VERSION 5.8 ;
BUSBITCHARS "[]" ;
DIVIDERCHAR "/" ;
UNITS
    DATABASE MICRONS 1000 ;
END UNITS

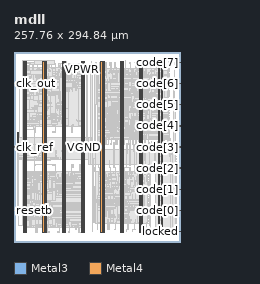
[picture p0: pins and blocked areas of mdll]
MACRO mdll
  FOREIGN mdll 0 0 ;
  CLASS BLOCK ;
  SIZE 257.76 BY 294.84 ;
  PIN clk_out
    DIRECTION OUTPUT ;
    USE SIGNAL ;
    PORT
      LAYER Metal3 ;
        RECT  0 245.5 0.4 245.9 ;
    END
  END clk_out
  PIN clk_ref
    DIRECTION INPUT ;
    USE SIGNAL ;
    PORT
      LAYER Metal3 ;
        RECT  0 147.22 0.4 147.62 ;
    END
  END clk_ref
  PIN code[0]
    DIRECTION OUTPUT ;
    USE SIGNAL ;
    PORT
      LAYER Metal3 ;
        RECT  257.36 48.94 257.76 49.34 ;
    END
  END code[0]
  PIN code[1]
    DIRECTION OUTPUT ;
    USE SIGNAL ;
    PORT
      LAYER Metal3 ;
        RECT  257.36 81.7 257.76 82.1 ;
    END
  END code[1]
  PIN code[2]
    DIRECTION OUTPUT ;
    USE SIGNAL ;
    PORT
      LAYER Metal3 ;
        RECT  257.36 114.46 257.76 114.86 ;
    END
  END code[2]
  PIN code[3]
    DIRECTION OUTPUT ;
    USE SIGNAL ;
    PORT
      LAYER Metal3 ;
        RECT  257.36 147.22 257.76 147.62 ;
    END
  END code[3]
  PIN code[4]
    DIRECTION OUTPUT ;
    USE SIGNAL ;
    PORT
      LAYER Metal3 ;
        RECT  257.36 179.98 257.76 180.38 ;
    END
  END code[4]
  PIN code[5]
    DIRECTION OUTPUT ;
    USE SIGNAL ;
    PORT
      LAYER Metal3 ;
        RECT  257.36 212.74 257.76 213.14 ;
    END
  END code[5]
  PIN code[6]
    DIRECTION OUTPUT ;
    USE SIGNAL ;
    PORT
      LAYER Metal3 ;
        RECT  257.36 245.5 257.76 245.9 ;
    END
  END code[6]
  PIN code[7]
    DIRECTION OUTPUT ;
    USE SIGNAL ;
    PORT
      LAYER Metal3 ;
        RECT  257.36 278.26 257.76 278.66 ;
    END
  END code[7]
  PIN locked
    DIRECTION OUTPUT ;
    USE SIGNAL ;
    PORT
      LAYER Metal3 ;
        RECT  257.36 16.18 257.76 16.58 ;
    END
  END locked
  PIN resetb
    DIRECTION INPUT ;
    USE SIGNAL ;
    PORT
      LAYER Metal3 ;
        RECT  0 48.94 0.4 49.34 ;
    END
  END resetb
  PIN VPWR
    DIRECTION INOUT ;
    USE POWER ;
    PORT
      LAYER Metal4 ;
        RECT  5.92 154.76 7.52 170.32 ;
        RECT  224.96 14.9 226.56 279.94 ;
        RECT  194.96 14.9 196.56 279.94 ;
        RECT  164.96 14.9 166.56 279.94 ;
        RECT  134.96 14.9 136.56 279.94 ;
        RECT  104.96 14.9 106.56 279.94 ;
        RECT  74.96 14.9 76.56 279.94 ;
        RECT  44.96 14.9 46.56 279.94 ;
        RECT  14.96 14.9 16.56 279.94 ;
    END
  END VPWR
  PIN VGND
    DIRECTION INOUT ;
    USE GROUND ;
    PORT
      LAYER Metal4 ;
        RECT  228.16 14.9 229.76 279.94 ;
        RECT  198.16 14.9 199.76 279.94 ;
        RECT  168.16 14.9 169.76 279.94 ;
        RECT  138.16 14.9 139.76 279.94 ;
        RECT  108.16 14.9 109.76 279.94 ;
        RECT  78.16 14.9 79.76 279.94 ;
        RECT  48.16 14.9 49.76 279.94 ;
        RECT  18.16 14.9 19.76 279.94 ;
    END
  END VGND
  OBS
    LAYER GatPoly ;
     RECT  86.2 26.26 92.36 30.24 ;
     RECT  83.8 30.04 92.36 30.44 ;
     RECT  63.64 26.26 69.8 34.22 ;
     RECT  83.8 30.24 89.96 34.22 ;
     RECT  93.88 26.26 100.04 34.22 ;
     RECT  74.2 33.82 80.36 37.8 ;
     RECT  72.28 37.6 80.36 38 ;
     RECT  91 37.6 97.16 41.58 ;
     RECT  72.28 37.8 78.44 41.78 ;
     RECT  91 41.38 100.04 41.78 ;
     RECT  46.36 41.38 52.52 45.36 ;
     RECT  43.96 45.16 52.52 45.56 ;
     RECT  54.04 33.82 60.2 45.56 ;
     RECT  93.88 41.58 100.04 45.56 ;
     RECT  43.96 45.36 50.12 49.14 ;
     RECT  71.32 45.16 77.48 49.14 ;
     RECT  43.96 48.94 53.96 49.34 ;
     RECT  66.52 48.94 77.48 49.34 ;
     RECT  47.8 49.14 53.96 53.12 ;
     RECT  54.04 48.94 60.2 53.12 ;
     RECT  66.52 49.14 72.68 53.12 ;
     RECT  33.88 52.72 40.04 56.9 ;
     RECT  83.8 48.94 89.96 56.9 ;
     RECT  93.88 52.72 100.04 56.9 ;
     RECT  48.76 56.5 54.92 60.68 ;
     RECT  30.52 60.28 36.68 64.46 ;
     RECT  23.8 52.72 29.96 68.24 ;
     RECT  93.88 64.06 100.04 68.24 ;
     RECT  23.8 71.62 29.96 75.6 ;
     RECT  23.8 75.4 30.92 75.8 ;
     RECT  93.88 71.62 100.04 75.8 ;
     RECT  24.76 75.6 30.92 79.38 ;
     RECT  23.8 79.18 30.92 79.58 ;
     RECT  50.68 75.4 56.84 79.58 ;
     RECT  63.64 79.18 69.8 83.36 ;
     RECT  73.24 79.18 79.4 83.36 ;
     RECT  84.76 79.18 90.92 83.36 ;
     RECT  93.88 79.18 100.04 83.36 ;
     RECT  30.52 82.96 36.68 87.14 ;
     RECT  43.96 82.96 50.12 87.14 ;
     RECT  23.8 79.38 29.96 90.72 ;
     RECT  23.8 90.52 32.36 90.92 ;
     RECT  74.2 86.74 80.36 90.92 ;
     RECT  92.92 86.74 99.08 90.92 ;
     RECT  26.2 90.72 32.36 94.5 ;
     RECT  23.8 94.3 32.36 94.7 ;
     RECT  33.88 90.52 40.04 94.7 ;
     RECT  43.96 90.52 50.12 94.7 ;
     RECT  63.64 90.52 69.8 94.7 ;
     RECT  83.8 90.52 89.96 94.7 ;
     RECT  23.8 94.5 29.96 98.28 ;
     RECT  23.8 98.08 32.36 98.48 ;
     RECT  51.16 98.08 57.32 102.06 ;
     RECT  73.72 98.08 79.88 102.06 ;
     RECT  93.88 94.3 100.04 102.06 ;
     RECT  26.2 98.28 32.36 102.26 ;
     RECT  51.16 101.86 60.2 102.26 ;
     RECT  70.36 101.86 79.88 102.26 ;
     RECT  83.8 101.86 100.04 102.26 ;
     RECT  33.88 101.86 40.04 105.84 ;
     RECT  28.6 105.64 40.04 106.04 ;
     RECT  43.96 101.86 50.12 106.04 ;
     RECT  54.04 102.06 60.2 106.04 ;
     RECT  63.64 101.86 69.8 106.04 ;
     RECT  70.36 102.06 76.52 106.04 ;
     RECT  83.8 102.06 95.72 106.04 ;
     RECT  28.6 105.84 34.76 109.82 ;
     RECT  34.84 197.76 40.04 201.74 ;
     RECT  68.92 201.54 74.12 209.3 ;
     RECT  30.04 201.54 40.04 213.28 ;
     RECT  64.12 209.1 78.92 213.28 ;
     RECT  34.84 213.08 40.04 217.06 ;
     RECT  64.12 213.08 74.12 217.06 ;
     RECT  68.92 216.86 74.12 220.84 ;
    LAYER Metal1 ;
     RECT  5.66 135.76 6.035 136.4 ;
     RECT  5.66 143.32 6.035 143.96 ;
     RECT  5.66 150.88 6.035 151.52 ;
     RECT  5.66 158.44 6.035 159.08 ;
     RECT  5.66 131.98 6.045 132.62 ;
     RECT  5.835 134.99 6.045 137.17 ;
     RECT  5.66 139.54 6.045 140.18 ;
     RECT  5.835 142.55 6.045 144.73 ;
     RECT  5.66 147.1 6.045 147.74 ;
     RECT  5.835 150.11 6.045 152.29 ;
     RECT  5.66 154.66 6.045 155.3 ;
     RECT  5.835 157.67 6.045 159.08 ;
     RECT  5.66 128.2 6.075 128.84 ;
     RECT  5.845 131.98 6.075 159.08 ;
     RECT  5.875 128.2 6.1 130.085 ;
     RECT  5.875 131.98 6.1 160.325 ;
     RECT  5.66 162.22 6.1 162.86 ;
     RECT  15.64 44.94 15.97 45.78 ;
     RECT  15.64 48.72 15.97 49.56 ;
     RECT  15.64 52.5 15.97 53.34 ;
     RECT  15.64 56.28 15.97 57.12 ;
     RECT  15.64 101.64 15.97 102.48 ;
     RECT  15.64 105.42 15.97 106.26 ;
     RECT  15.64 224 15.97 224.84 ;
     RECT  15.64 227.78 15.97 228.62 ;
     RECT  15.64 37.38 16.015 38.22 ;
     RECT  15.77 44.94 16.015 57.12 ;
     RECT  15.64 60.06 16.015 60.9 ;
     RECT  15.64 67.62 16.015 68.46 ;
     RECT  15.64 75.18 16.015 76.02 ;
     RECT  15.64 82.74 16.015 83.58 ;
     RECT  15.64 90.3 16.015 91.14 ;
     RECT  15.77 101.64 16.015 106.26 ;
     RECT  15.64 178.64 16.015 179.48 ;
     RECT  15.64 186.2 16.015 187.04 ;
     RECT  15.64 193.76 16.015 194.6 ;
     RECT  15.64 201.32 16.015 202.16 ;
     RECT  15.64 208.88 16.015 209.72 ;
     RECT  15.64 216.44 16.015 217.28 ;
     RECT  15.77 224 16.015 228.62 ;
     RECT  15.64 239.12 16.015 239.96 ;
     RECT  15.64 246.68 16.015 247.52 ;
     RECT  15.64 254.24 16.015 255.08 ;
     RECT  15.64 261.8 16.015 262.64 ;
     RECT  15.64 33.6 16.025 34.44 ;
     RECT  15.815 36.61 16.025 38.22 ;
     RECT  15.64 41.16 16.025 42 ;
     RECT  15.815 44.17 16.025 57.12 ;
     RECT  15.815 60.06 16.025 61.67 ;
     RECT  15.64 63.84 16.025 64.68 ;
     RECT  15.815 67.62 16.025 69.23 ;
     RECT  15.64 71.4 16.025 72.24 ;
     RECT  15.815 74.41 16.025 76.02 ;
     RECT  15.64 78.96 16.025 79.8 ;
     RECT  15.815 81.97 16.025 83.58 ;
     RECT  15.64 86.52 16.025 87.36 ;
     RECT  15.815 89.53 16.025 91.91 ;
     RECT  15.64 94.08 16.025 94.92 ;
     RECT  15.815 101.64 16.025 107.03 ;
     RECT  15.64 109.2 16.025 110.04 ;
     RECT  15.815 178.64 16.025 180.25 ;
     RECT  15.64 182.42 16.025 183.26 ;
     RECT  15.815 185.43 16.025 187.81 ;
     RECT  15.64 189.98 16.025 190.82 ;
     RECT  15.815 192.99 16.025 195.37 ;
     RECT  15.64 197.54 16.025 198.38 ;
     RECT  15.815 200.55 16.025 202.93 ;
     RECT  15.64 205.1 16.025 205.94 ;
     RECT  15.815 208.11 16.025 210.49 ;
     RECT  15.64 212.66 16.025 213.5 ;
     RECT  15.815 215.67 16.025 218.05 ;
     RECT  15.64 220.22 16.025 221.06 ;
     RECT  15.815 223.23 16.025 228.62 ;
     RECT  15.64 235.34 16.025 236.18 ;
     RECT  15.815 238.35 16.025 240.73 ;
     RECT  15.64 242.9 16.025 243.74 ;
     RECT  15.815 245.91 16.025 248.29 ;
     RECT  15.64 250.46 16.025 251.3 ;
     RECT  15.815 253.47 16.025 255.85 ;
     RECT  15.64 258.02 16.025 258.86 ;
     RECT  15.815 261.03 16.025 263.41 ;
     RECT  15.64 265.58 16.025 266.42 ;
     RECT  15.825 33.6 16.195 38.22 ;
     RECT  15.825 41.16 16.195 57.12 ;
     RECT  15.825 235.34 16.535 266.42 ;
     RECT  15.64 269.36 16.535 270.2 ;
     RECT  15.825 178.64 16.64 228.62 ;
     RECT  15.64 231.56 16.64 232.4 ;
     RECT  15.64 22.26 16.935 23.1 ;
     RECT  15.64 26.04 16.935 26.88 ;
     RECT  15.995 33.6 17.005 57.12 ;
     RECT  15.825 60.06 17.005 64.68 ;
     RECT  15.825 67.62 17.005 76.02 ;
     RECT  15.825 78.96 17.005 83.58 ;
     RECT  15.825 86.52 17.005 94.92 ;
     RECT  16.44 178.64 17.005 232.4 ;
     RECT  16.335 235.34 17.005 270.2 ;
     RECT  15.64 29.82 17.155 30.66 ;
     RECT  16.805 33.6 17.155 94.92 ;
     RECT  15.64 97.86 17.155 98.7 ;
     RECT  16.955 29.82 17.545 98.7 ;
     RECT  15.825 101.64 17.545 110.04 ;
     RECT  16.735 22.26 17.615 26.88 ;
     RECT  17.345 29.82 17.615 110.04 ;
     RECT  17.415 22.26 104.23 110.04 ;
     RECT  104.03 22.26 105.19 45.78 ;
     RECT  104.03 48.72 105.19 87.36 ;
     RECT  104.03 90.3 105.19 102.48 ;
     RECT  104.03 105.42 105.19 110.04 ;
     RECT  104.99 22.26 105.32 23.1 ;
     RECT  104.99 26.04 105.32 26.88 ;
     RECT  104.99 29.82 105.32 30.66 ;
     RECT  104.99 33.6 105.32 34.44 ;
     RECT  104.99 37.38 105.32 38.22 ;
     RECT  104.99 41.16 105.32 42 ;
     RECT  104.99 44.94 105.32 45.78 ;
     RECT  104.99 48.72 105.32 49.56 ;
     RECT  104.99 52.5 105.32 53.34 ;
     RECT  104.99 56.28 105.32 57.12 ;
     RECT  104.99 60.06 105.32 60.9 ;
     RECT  104.99 63.84 105.32 64.68 ;
     RECT  104.99 67.62 105.32 68.46 ;
     RECT  104.99 71.4 105.32 72.24 ;
     RECT  104.99 75.18 105.32 76.02 ;
     RECT  104.99 78.96 105.32 79.8 ;
     RECT  104.99 82.74 105.32 83.58 ;
     RECT  104.99 86.52 105.32 87.36 ;
     RECT  104.99 90.3 105.32 91.14 ;
     RECT  104.99 94.08 105.32 94.92 ;
     RECT  104.99 97.86 105.32 98.7 ;
     RECT  104.99 101.64 105.32 102.48 ;
     RECT  104.99 105.42 105.32 106.26 ;
     RECT  104.99 109.2 105.32 110.04 ;
     RECT  16.805 178.64 106.065 270.2 ;
     RECT  105.865 178.64 106.125 266.42 ;
     RECT  105.925 178.64 106.545 202.16 ;
     RECT  105.925 254.24 106.545 266.42 ;
     RECT  105.925 205.1 106.605 243.74 ;
     RECT  105.925 246.68 106.605 251.3 ;
     RECT  106.345 254.24 106.605 262.64 ;
     RECT  106.405 208.88 106.63 221.06 ;
     RECT  106.405 224 106.63 228.62 ;
     RECT  106.345 182.42 107.085 202.16 ;
     RECT  106.885 193.76 107.11 198.38 ;
     RECT  106.43 216.44 107.565 221.06 ;
     RECT  106.405 231.56 107.565 239.96 ;
     RECT  106.885 182.42 107.59 190.82 ;
     RECT  106.43 208.88 107.59 213.5 ;
     RECT  106.345 178.64 107.72 179.48 ;
     RECT  107.39 182.42 107.72 183.26 ;
     RECT  107.39 186.2 107.72 187.04 ;
     RECT  107.39 189.98 107.72 190.82 ;
     RECT  106.91 193.76 107.72 194.6 ;
     RECT  106.91 197.54 107.72 198.38 ;
     RECT  106.885 201.32 107.72 202.16 ;
     RECT  106.405 205.1 107.72 205.94 ;
     RECT  107.39 208.88 107.72 209.72 ;
     RECT  107.39 212.66 107.72 213.5 ;
     RECT  107.365 216.44 107.72 217.28 ;
     RECT  107.365 220.22 107.72 221.06 ;
     RECT  106.43 224 107.72 224.84 ;
     RECT  106.43 227.78 107.72 228.62 ;
     RECT  107.365 231.56 107.72 232.4 ;
     RECT  107.365 235.34 107.72 236.18 ;
     RECT  107.365 239.12 107.72 239.96 ;
     RECT  106.405 242.9 107.72 243.74 ;
     RECT  106.405 246.68 107.72 247.52 ;
     RECT  106.405 250.46 107.72 251.3 ;
     RECT  106.405 254.24 107.72 255.08 ;
     RECT  106.405 258.02 107.72 258.86 ;
     RECT  106.405 261.8 107.72 262.64 ;
     RECT  106.345 265.58 107.72 266.42 ;
     RECT  105.865 269.36 107.72 270.2 ;
     RECT  116.06 120.64 116.435 121.28 ;
     RECT  5.9 128.2 116.435 162.86 ;
     RECT  116.235 120.64 116.445 122.05 ;
     RECT  116.06 124.42 116.445 125.06 ;
     RECT  116.235 127.43 116.445 162.86 ;
     RECT  116.245 120.64 118.495 162.86 ;
     RECT  118.295 160.87 118.505 162.86 ;
     RECT  118.295 120.64 118.53 159.08 ;
     RECT  118.33 147.1 118.66 147.74 ;
     RECT  118.33 150.88 118.66 151.52 ;
     RECT  118.33 154.66 118.66 155.3 ;
     RECT  118.33 158.44 118.66 159.08 ;
     RECT  118.305 162.22 118.66 162.86 ;
     RECT  126.52 28.56 126.85 29.4 ;
     RECT  126.52 32.34 126.85 33.18 ;
     RECT  126.65 28.56 126.895 33.18 ;
     RECT  126.52 39.9 126.895 40.74 ;
     RECT  126.52 47.46 126.895 48.3 ;
     RECT  126.52 55.02 126.895 55.86 ;
     RECT  126.52 62.58 126.895 63.42 ;
     RECT  126.52 70.14 126.895 70.98 ;
     RECT  126.52 77.7 126.895 78.54 ;
     RECT  126.52 85.26 126.895 86.1 ;
     RECT  126.52 92.82 126.895 93.66 ;
     RECT  126.52 100.38 126.895 101.22 ;
     RECT  126.52 107.94 126.895 108.78 ;
     RECT  126.695 28.56 126.905 33.95 ;
     RECT  126.52 36.12 126.905 36.96 ;
     RECT  126.695 39.13 126.905 41.51 ;
     RECT  126.52 43.68 126.905 44.52 ;
     RECT  126.695 46.69 126.905 49.07 ;
     RECT  126.52 51.24 126.905 52.08 ;
     RECT  126.695 54.25 126.905 56.63 ;
     RECT  126.52 58.8 126.905 59.64 ;
     RECT  126.695 62.58 126.905 64.19 ;
     RECT  126.52 66.36 126.905 67.2 ;
     RECT  126.695 69.37 126.905 71.75 ;
     RECT  126.52 73.92 126.905 74.76 ;
     RECT  126.695 76.93 126.905 79.31 ;
     RECT  126.52 81.48 126.905 82.32 ;
     RECT  126.695 84.49 126.905 86.87 ;
     RECT  126.52 89.04 126.905 89.88 ;
     RECT  126.695 92.05 126.905 94.43 ;
     RECT  126.52 96.6 126.905 97.44 ;
     RECT  126.695 99.61 126.905 101.99 ;
     RECT  126.52 104.16 126.905 105 ;
     RECT  126.695 107.17 126.905 108.78 ;
     RECT  126.705 28.56 127.4 59.64 ;
     RECT  126.705 62.58 127.4 108.78 ;
     RECT  129.4 181.02 129.73 181.86 ;
     RECT  129.4 184.8 129.73 185.64 ;
     RECT  129.4 188.58 129.73 189.42 ;
     RECT  129.4 192.36 129.73 193.2 ;
     RECT  129.4 196.14 129.73 196.98 ;
     RECT  129.4 199.92 129.73 200.76 ;
     RECT  129.4 211.26 129.73 212.1 ;
     RECT  129.4 215.04 129.73 215.88 ;
     RECT  129.4 218.82 129.73 219.66 ;
     RECT  129.4 222.6 129.73 223.44 ;
     RECT  129.4 230.16 129.73 231 ;
     RECT  129.4 233.94 129.73 234.78 ;
     RECT  129.4 241.5 129.73 242.34 ;
     RECT  129.4 245.28 129.73 246.12 ;
     RECT  129.4 264.18 129.73 265.02 ;
     RECT  129.4 267.96 129.73 268.8 ;
     RECT  129.4 165.9 129.775 166.74 ;
     RECT  129.4 173.46 129.775 174.3 ;
     RECT  129.53 211.26 129.775 215.88 ;
     RECT  129.53 230.16 129.775 234.78 ;
     RECT  129.4 249.06 129.775 249.9 ;
     RECT  129.4 256.62 129.775 257.46 ;
     RECT  129.53 264.18 129.775 268.8 ;
     RECT  129.4 162.12 129.785 162.96 ;
     RECT  129.575 165.13 129.785 167.51 ;
     RECT  129.4 169.68 129.785 170.52 ;
     RECT  129.575 173.46 129.785 175.07 ;
     RECT  129.4 177.24 129.785 178.08 ;
     RECT  129.4 207.48 129.785 208.32 ;
     RECT  129.575 210.49 129.785 215.88 ;
     RECT  129.575 230.16 129.785 235.55 ;
     RECT  129.4 237.72 129.785 238.56 ;
     RECT  129.53 241.5 129.785 246.12 ;
     RECT  129.575 248.29 129.785 250.67 ;
     RECT  129.4 252.84 129.785 253.68 ;
     RECT  129.575 255.85 129.785 258.23 ;
     RECT  129.4 260.4 129.785 261.24 ;
     RECT  129.575 263.41 129.785 268.8 ;
     RECT  129.4 158.34 129.815 159.18 ;
     RECT  129.585 162.12 129.815 170.52 ;
     RECT  129.585 173.46 129.92 178.08 ;
     RECT  129.53 181.02 129.92 189.42 ;
     RECT  129.585 230.16 129.92 238.56 ;
     RECT  129.585 241.5 129.92 268.8 ;
     RECT  129.4 203.7 129.95 204.54 ;
     RECT  129.585 207.48 129.95 215.88 ;
     RECT  129.53 192.36 130.21 200.76 ;
     RECT  129.75 203.7 130.21 215.88 ;
     RECT  129.615 158.34 130.26 170.52 ;
     RECT  129.72 173.46 130.26 189.42 ;
     RECT  129.4 226.38 130.32 227.22 ;
     RECT  130.01 192.36 130.4 215.88 ;
     RECT  129.53 218.82 130.4 223.44 ;
     RECT  130.12 226.38 130.4 228.21 ;
     RECT  130.2 192.36 130.42 228.21 ;
     RECT  129.72 230.16 130.42 268.8 ;
     RECT  130.06 158.34 131.34 189.42 ;
     RECT  130.22 192.36 131.34 268.8 ;
     RECT  127.2 28.56 207.405 108.78 ;
     RECT  207.205 28.56 207.43 78.54 ;
     RECT  207.205 81.48 207.43 108.78 ;
     RECT  207.23 43.68 207.79 67.2 ;
     RECT  207.23 70.14 207.79 74.76 ;
     RECT  207.23 85.26 207.79 108.78 ;
     RECT  207.23 28.56 207.825 40.74 ;
     RECT  207.59 85.26 207.825 97.44 ;
     RECT  207.59 100.38 207.825 108.78 ;
     RECT  207.625 85.26 207.83 94.29 ;
     RECT  207.625 100.38 207.83 101.85 ;
     RECT  207.59 43.68 207.885 52.08 ;
     RECT  207.625 32.34 207.91 40.74 ;
     RECT  207.625 104.16 208.305 108.78 ;
     RECT  207.63 85.26 208.365 93.66 ;
     RECT  207.71 36.12 208.39 40.74 ;
     RECT  207.685 43.68 208.39 48.3 ;
     RECT  207.59 55.02 208.39 59.64 ;
     RECT  207.59 62.58 208.39 67.2 ;
     RECT  208.165 89.04 208.39 93.66 ;
     RECT  207.625 28.56 208.52 29.4 ;
     RECT  207.71 32.34 208.52 33.18 ;
     RECT  208.19 36.12 208.52 36.96 ;
     RECT  208.19 39.9 208.52 40.74 ;
     RECT  208.19 43.68 208.52 44.52 ;
     RECT  208.19 47.46 208.52 48.3 ;
     RECT  207.685 51.24 208.52 52.08 ;
     RECT  208.19 55.02 208.52 55.86 ;
     RECT  208.19 58.8 208.52 59.64 ;
     RECT  208.19 62.58 208.52 63.42 ;
     RECT  208.19 66.36 208.52 67.2 ;
     RECT  207.59 70.14 208.52 70.98 ;
     RECT  207.59 73.92 208.52 74.76 ;
     RECT  207.23 77.7 208.52 78.54 ;
     RECT  207.23 81.48 208.52 82.32 ;
     RECT  208.165 85.26 208.52 86.1 ;
     RECT  208.19 89.04 208.52 89.88 ;
     RECT  208.19 92.82 208.52 93.66 ;
     RECT  207.625 96.6 208.52 97.44 ;
     RECT  207.63 100.38 208.52 101.22 ;
     RECT  208.105 104.16 208.52 105 ;
     RECT  208.105 107.94 208.52 108.78 ;
     RECT  219.74 14.8 220.115 15.44 ;
     RECT  219.74 22.36 220.115 23 ;
     RECT  219.74 29.92 220.115 30.56 ;
     RECT  219.74 37.48 220.115 38.12 ;
     RECT  219.74 45.04 220.115 45.68 ;
     RECT  219.74 52.6 220.115 53.24 ;
     RECT  219.74 60.16 220.115 60.8 ;
     RECT  219.74 67.72 220.115 68.36 ;
     RECT  219.74 75.28 220.115 75.92 ;
     RECT  219.74 82.84 220.115 83.48 ;
     RECT  219.74 90.4 220.115 91.04 ;
     RECT  219.74 97.96 220.115 98.6 ;
     RECT  219.74 105.52 220.115 106.16 ;
     RECT  219.74 113.08 220.115 113.72 ;
     RECT  118.33 120.64 220.115 143.96 ;
     RECT  219.915 14.8 220.125 16.21 ;
     RECT  219.74 18.58 220.125 19.22 ;
     RECT  219.915 21.59 220.125 23.77 ;
     RECT  219.74 26.14 220.125 26.78 ;
     RECT  219.915 29.15 220.125 31.33 ;
     RECT  219.74 33.7 220.125 34.34 ;
     RECT  219.915 36.71 220.125 38.89 ;
     RECT  219.74 41.26 220.125 41.9 ;
     RECT  219.915 44.27 220.125 46.45 ;
     RECT  219.74 48.82 220.125 49.46 ;
     RECT  219.915 51.83 220.125 54.01 ;
     RECT  219.74 56.38 220.125 57.02 ;
     RECT  219.915 59.39 220.125 61.57 ;
     RECT  219.74 63.94 220.125 64.58 ;
     RECT  219.915 66.95 220.125 69.13 ;
     RECT  219.74 71.5 220.125 72.14 ;
     RECT  219.915 74.51 220.125 76.69 ;
     RECT  219.74 79.06 220.125 79.7 ;
     RECT  219.915 82.07 220.125 84.25 ;
     RECT  219.74 86.62 220.125 87.26 ;
     RECT  219.915 89.63 220.125 91.81 ;
     RECT  219.74 94.18 220.125 94.82 ;
     RECT  219.915 97.19 220.125 99.37 ;
     RECT  219.74 101.74 220.125 102.38 ;
     RECT  219.915 104.75 220.125 106.93 ;
     RECT  219.74 109.3 220.125 109.94 ;
     RECT  219.915 112.31 220.125 114.49 ;
     RECT  219.74 116.86 220.125 117.5 ;
     RECT  219.915 119.87 220.125 143.96 ;
     RECT  131.14 158.34 239.86 268.8 ;
     RECT  239.66 199.92 239.915 268.8 ;
     RECT  239.66 158.34 240.045 196.98 ;
     RECT  239.715 203.7 240.045 268.8 ;
     RECT  239.845 177.24 240.525 196.98 ;
     RECT  239.845 203.7 240.525 208.32 ;
     RECT  239.845 211.26 240.525 215.88 ;
     RECT  239.845 218.82 240.525 234.78 ;
     RECT  239.845 237.72 240.525 268.8 ;
     RECT  240.325 249.06 240.55 261.24 ;
     RECT  240.325 181.02 241.005 193.2 ;
     RECT  240.325 226.38 241.005 234.78 ;
     RECT  240.325 237.72 241.005 246.12 ;
     RECT  239.845 158.34 241.03 174.3 ;
     RECT  240.805 188.58 241.03 193.2 ;
     RECT  240.83 158.34 241.32 170.52 ;
     RECT  241.12 162.12 241.425 170.52 ;
     RECT  240.325 264.18 241.425 268.8 ;
     RECT  240.805 241.5 241.485 246.12 ;
     RECT  240.35 252.84 241.485 261.24 ;
     RECT  241.12 158.34 241.64 159.18 ;
     RECT  241.225 162.12 241.64 162.96 ;
     RECT  241.225 165.9 241.64 166.74 ;
     RECT  241.225 169.68 241.64 170.52 ;
     RECT  240.83 173.46 241.64 174.3 ;
     RECT  240.325 177.24 241.64 178.08 ;
     RECT  240.805 181.02 241.64 181.86 ;
     RECT  240.805 184.8 241.64 185.64 ;
     RECT  240.83 188.58 241.64 189.42 ;
     RECT  240.83 192.36 241.64 193.2 ;
     RECT  240.325 196.14 241.64 196.98 ;
     RECT  239.715 199.92 241.64 200.76 ;
     RECT  240.325 203.7 241.64 204.54 ;
     RECT  240.325 207.48 241.64 208.32 ;
     RECT  240.325 211.26 241.64 212.1 ;
     RECT  240.325 215.04 241.64 215.88 ;
     RECT  240.325 218.82 241.64 219.66 ;
     RECT  240.325 222.6 241.64 223.44 ;
     RECT  240.805 226.38 241.64 227.22 ;
     RECT  240.805 230.16 241.64 231 ;
     RECT  240.805 233.94 241.64 234.78 ;
     RECT  240.805 237.72 241.64 238.56 ;
     RECT  241.285 241.5 241.64 242.34 ;
     RECT  241.285 245.28 241.64 246.12 ;
     RECT  240.35 249.06 241.64 249.9 ;
     RECT  241.285 252.84 241.64 253.68 ;
     RECT  241.285 256.62 241.64 257.46 ;
     RECT  241.285 260.4 241.64 261.24 ;
     RECT  241.225 264.18 241.64 265.02 ;
     RECT  241.225 267.96 241.64 268.8 ;
     RECT  219.925 14.8 243.775 143.96 ;
     RECT  243.575 138.19 243.785 143.96 ;
     RECT  243.575 14.8 245.755 136.4 ;
     RECT  243.585 139.54 245.755 143.96 ;
     RECT  245.555 14.8 250.495 143.96 ;
     RECT  250.295 123.07 250.505 126.41 ;
     RECT  250.295 128.2 250.975 143.96 ;
     RECT  250.775 130.63 250.985 133.97 ;
     RECT  250.295 14.8 251.78 121.28 ;
     RECT  250.775 135.76 251.78 143.96 ;
     RECT  251.58 18.58 251.97 49.46 ;
     RECT  251.58 52.6 251.97 83.48 ;
     RECT  251.58 86.62 251.97 113.72 ;
     RECT  251.58 116.86 251.97 121.28 ;
     RECT  251.58 14.8 252.1 15.44 ;
     RECT  251.77 18.58 252.1 19.22 ;
     RECT  251.77 22.36 252.1 23 ;
     RECT  251.77 26.14 252.1 26.78 ;
     RECT  251.77 29.92 252.1 30.56 ;
     RECT  251.77 33.7 252.1 34.34 ;
     RECT  251.77 37.48 252.1 38.12 ;
     RECT  251.77 41.26 252.1 41.9 ;
     RECT  251.77 45.04 252.1 45.68 ;
     RECT  251.77 48.82 252.1 49.46 ;
     RECT  251.77 52.6 252.1 53.24 ;
     RECT  251.77 56.38 252.1 57.02 ;
     RECT  251.77 60.16 252.1 60.8 ;
     RECT  251.77 63.94 252.1 64.58 ;
     RECT  251.77 67.72 252.1 68.36 ;
     RECT  251.77 71.5 252.1 72.14 ;
     RECT  251.77 75.28 252.1 75.92 ;
     RECT  251.77 79.06 252.1 79.7 ;
     RECT  251.77 82.84 252.1 83.48 ;
     RECT  251.77 86.62 252.1 87.26 ;
     RECT  251.77 90.4 252.1 91.04 ;
     RECT  251.77 94.18 252.1 94.82 ;
     RECT  251.77 97.96 252.1 98.6 ;
     RECT  251.77 101.74 252.1 102.38 ;
     RECT  251.77 105.52 252.1 106.16 ;
     RECT  251.77 109.3 252.1 109.94 ;
     RECT  251.77 113.08 252.1 113.72 ;
     RECT  251.77 116.86 252.1 117.5 ;
     RECT  251.77 120.64 252.1 121.28 ;
     RECT  250.305 124.42 252.1 125.06 ;
     RECT  250.775 128.2 252.1 128.84 ;
     RECT  250.785 131.98 252.1 132.62 ;
     RECT  251.58 135.76 252.1 136.4 ;
     RECT  251.58 139.54 252.1 140.18 ;
     RECT  251.58 143.32 252.1 143.96 ;
    LAYER Metal2 ;
     RECT  195.155 14.455 195.565 14.945 ;
     RECT  84.37 14.455 84.78 15.22 ;
     RECT  100.5 15.02 101.1 15.225 ;
     RECT  102.995 14.875 103.405 15.225 ;
     RECT  100.5 15.025 103.405 15.365 ;
     RECT  203.315 14.875 203.725 15.365 ;
     RECT  228.145 14.875 229.775 15.365 ;
     RECT  67.86 15.02 70.86 15.375 ;
     RECT  84.18 15.02 86.22 15.395 ;
     RECT  18.9 15.02 19.5 15.415 ;
     RECT  35.22 15.02 35.82 15.415 ;
     RECT  51.54 15.02 52.14 15.415 ;
     RECT  100.5 15.165 103.4 15.425 ;
     RECT  16.6 15.215 19.5 15.615 ;
     RECT  32.92 15.215 35.82 15.615 ;
     RECT  51.54 15.215 54.44 15.615 ;
     RECT  67 15.175 70.86 15.84 ;
     RECT  84.175 15.195 86.22 15.885 ;
     RECT  251.32 15.29 251.72 15.915 ;
     RECT  251.315 15.715 251.725 16.205 ;
     RECT  54.035 15.415 54.44 16.335 ;
     RECT  54.035 16.135 54.445 16.625 ;
     RECT  174.515 16.135 174.925 16.625 ;
     RECT  67 15.64 67.405 16.755 ;
     RECT  66.995 16.555 67.405 17.045 ;
     RECT  184.115 16.555 184.525 17.045 ;
     RECT  248.92 16.55 250.765 17.175 ;
     RECT  121.715 16.975 122.125 17.465 ;
     RECT  248.915 16.975 250.765 17.465 ;
     RECT  195.16 14.745 195.56 19 ;
     RECT  174.52 16.425 174.92 19.005 ;
     RECT  176.82 18.8 177.42 19.005 ;
     RECT  184.12 16.845 184.52 19.005 ;
     RECT  186.42 18.8 187.02 19.005 ;
     RECT  203.32 15.165 203.72 19.005 ;
     RECT  205.62 18.8 206.22 19.005 ;
     RECT  224.945 18.655 226.575 19.145 ;
     RECT  166.26 18.8 167.82 19.155 ;
     RECT  138.42 18.8 139.02 19.195 ;
     RECT  148.02 18.8 148.62 19.195 ;
     RECT  157.62 18.8 158.22 19.195 ;
     RECT  174.52 18.805 177.42 19.195 ;
     RECT  184.12 18.805 187.02 19.195 ;
     RECT  195.16 18.8 196.62 19.195 ;
     RECT  203.32 18.805 206.22 19.195 ;
     RECT  174.52 18.995 178.28 19.205 ;
     RECT  184.12 18.995 187.88 19.205 ;
     RECT  203.32 18.995 207.56 19.205 ;
     RECT  195.16 18.995 198.92 19.245 ;
     RECT  155.32 18.995 158.22 19.275 ;
     RECT  186.42 19.005 187.88 19.275 ;
     RECT  136.12 18.995 139.02 19.395 ;
     RECT  145.72 18.995 148.62 19.395 ;
     RECT  155.315 19.075 158.22 19.395 ;
     RECT  196.02 19.045 198.92 19.395 ;
     RECT  155.315 19.195 155.725 19.565 ;
     RECT  186.42 19.075 187.885 19.565 ;
     RECT  100.5 15.225 101.1 20.015 ;
     RECT  95.695 19.815 96.305 20.505 ;
     RECT  100.495 19.815 101.105 20.505 ;
     RECT  198.515 19.195 198.92 20.955 ;
     RECT  198.515 20.755 198.925 21.245 ;
     RECT  219.155 20.755 219.565 21.245 ;
     RECT  205.62 19.005 207.56 21.375 ;
     RECT  205.62 21.175 207.565 21.665 ;
     RECT  211.955 21.175 212.365 21.665 ;
     RECT  18.9 15.415 19.5 22.46 ;
     RECT  85.62 15.685 86.22 22.46 ;
     RECT  228.145 22.435 229.775 22.925 ;
     RECT  95.7 20.305 96.3 23.355 ;
     RECT  18.9 22.26 24.04 23.79 ;
     RECT  16.6 15.415 17 24.215 ;
     RECT  18.9 23.59 24.78 24.215 ;
     RECT  40.04 22.26 44.04 24.215 ;
     RECT  51.54 15.415 52.14 24.215 ;
     RECT  60.04 22.26 64.04 24.215 ;
     RECT  66.9 23.155 67.5 24.215 ;
     RECT  95.7 23.155 97.26 24.215 ;
     RECT  51.54 24.015 52.62 24.26 ;
     RECT  66.9 24.015 68.46 24.26 ;
     RECT  70.26 15.64 70.86 24.26 ;
     RECT  74.58 24.015 76.62 24.26 ;
     RECT  89.46 24.015 90.06 24.26 ;
     RECT  73.14 24.06 76.62 24.68 ;
     RECT  16.6 24.015 26.7 24.705 ;
     RECT  73.14 24.48 78.06 24.705 ;
     RECT  93.78 24.015 98.22 25.05 ;
     RECT  100.04 22.26 104.04 25.05 ;
     RECT  89.46 24.06 90.54 25.055 ;
     RECT  93.78 24.85 104.04 25.055 ;
     RECT  80.04 22.26 86.22 25.125 ;
     RECT  176.82 19.005 178.28 25.155 ;
     RECT  211.96 21.465 212.36 25.155 ;
     RECT  176.82 24.955 178.285 25.445 ;
     RECT  210.515 24.955 212.36 25.445 ;
     RECT  35.22 15.415 35.82 25.475 ;
     RECT  38.1 24.015 44.04 25.475 ;
     RECT  47.22 24.85 47.82 25.475 ;
     RECT  51.54 24.06 53.1 25.475 ;
     RECT  66.9 24.06 70.86 25.475 ;
     RECT  73.14 24.505 73.74 25.475 ;
     RECT  89.455 24.855 90.54 25.475 ;
     RECT  92.335 24.855 104.04 25.475 ;
     RECT  196.02 19.195 196.62 25.52 ;
     RECT  16.6 24.505 24.04 25.545 ;
     RECT  89.455 25.275 104.04 25.545 ;
     RECT  16.6 25.345 17.005 25.575 ;
     RECT  6.515 25.375 6.925 25.865 ;
     RECT  16.595 25.375 17.005 25.865 ;
     RECT  196.02 25.32 197.1 25.92 ;
     RECT  35.22 25.275 47.825 25.965 ;
     RECT  50.575 25.275 53.1 25.965 ;
     RECT  89.46 25.345 104.04 25.965 ;
     RECT  89.46 25.765 98.22 25.97 ;
     RECT  32.92 15.415 33.32 25.995 ;
     RECT  13.715 25.795 14.125 26.285 ;
     RECT  32.915 25.795 33.325 26.285 ;
     RECT  75.54 24.505 78.06 26.315 ;
     RECT  224.945 26.215 226.575 26.705 ;
     RECT  18.9 25.345 24.04 27.62 ;
     RECT  30.42 24.015 31.02 27.62 ;
     RECT  37.62 25.765 44.04 27.995 ;
     RECT  45.78 25.765 46.38 27.995 ;
     RECT  89.94 25.77 98.22 28.205 ;
     RECT  89.7 28.005 98.22 28.315 ;
     RECT  66.9 25.275 73.74 28.415 ;
     RECT  75.54 26.115 78.065 28.415 ;
     RECT  80.04 24.925 85.26 28.415 ;
     RECT  50.58 25.765 53.1 28.46 ;
     RECT  128.82 18.8 129.42 28.76 ;
     RECT  136.12 19.195 136.52 28.76 ;
     RECT  196.5 25.72 197.1 28.76 ;
     RECT  17.46 27.42 24.04 28.835 ;
     RECT  26.1 24.505 26.7 28.835 ;
     RECT  35.22 25.765 35.82 28.835 ;
     RECT  37.62 27.795 46.38 28.835 ;
     RECT  48.18 28.205 48.78 28.835 ;
     RECT  56.34 24.015 64.04 28.835 ;
     RECT  66.9 28.215 85.26 28.835 ;
     RECT  89.46 28.115 98.22 28.835 ;
     RECT  121.72 17.265 122.12 28.935 ;
     RECT  128.82 28.56 136.52 28.935 ;
     RECT  121.235 28.735 122.12 29.225 ;
     RECT  128.82 28.735 136.525 29.225 ;
     RECT  17.46 28.635 26.705 29.325 ;
     RECT  56.335 28.635 64.04 29.325 ;
     RECT  66.9 28.635 85.265 29.325 ;
     RECT  138.42 19.195 139.02 29.675 ;
     RECT  148.02 19.195 148.62 29.675 ;
     RECT  157.62 19.195 158.22 29.675 ;
     RECT  176.82 25.245 177.42 29.675 ;
     RECT  186.42 19.365 187.02 29.675 ;
     RECT  205.62 21.465 206.22 29.675 ;
     RECT  166.26 18.955 168.68 29.775 ;
     RECT  124.115 29.575 124.525 30.065 ;
     RECT  128.82 29.025 134.92 30.12 ;
     RECT  138.42 29.475 139.5 30.12 ;
     RECT  148.02 29.475 149.1 30.12 ;
     RECT  157.62 29.475 158.7 30.12 ;
     RECT  186.42 29.475 187.5 30.12 ;
     RECT  205.62 29.475 206.7 30.12 ;
     RECT  129.3 29.92 134.92 30.165 ;
     RECT  138.9 29.92 139.5 30.165 ;
     RECT  148.5 29.92 149.1 30.165 ;
     RECT  158.1 29.92 158.7 30.165 ;
     RECT  186.9 29.92 187.5 30.165 ;
     RECT  190.92 28.56 197.1 30.165 ;
     RECT  206.1 29.92 206.7 30.165 ;
     RECT  228.145 29.995 229.775 30.485 ;
     RECT  17.46 29.125 24.78 30.51 ;
     RECT  150.92 28.56 154.92 30.515 ;
     RECT  166.26 29.575 168.685 30.515 ;
     RECT  170.92 28.56 174.92 30.515 ;
     RECT  176.82 29.475 177.9 30.515 ;
     RECT  16.98 30.31 24.78 30.935 ;
     RECT  35.22 28.635 48.785 30.935 ;
     RECT  58.26 29.125 64.04 30.935 ;
     RECT  66.9 29.125 84.04 30.935 ;
     RECT  89.455 28.635 98.22 30.935 ;
     RECT  100.04 25.765 104.04 30.935 ;
     RECT  159.055 30.305 159.66 30.935 ;
     RECT  165.3 30.315 177.9 30.935 ;
     RECT  165.3 30.735 180.3 31.005 ;
     RECT  197.455 30.315 198.065 31.005 ;
     RECT  28.5 27.42 31.02 31.2 ;
     RECT  16.975 30.735 24.78 31.35 ;
     RECT  28.02 31 31.02 31.35 ;
     RECT  89.455 30.735 104.04 31.35 ;
     RECT  16.975 31.15 31.02 31.355 ;
     RECT  178.26 30.805 180.3 31.355 ;
     RECT  207.055 30.315 207.66 31.355 ;
     RECT  16.975 31.155 31.025 31.425 ;
     RECT  35.215 30.735 48.785 31.425 ;
     RECT  58.26 30.735 84.04 31.425 ;
     RECT  159.055 30.735 159.665 31.425 ;
     RECT  197.46 30.805 198.06 31.43 ;
     RECT  17.46 31.225 31.025 31.775 ;
     RECT  58.26 31.225 73.745 31.775 ;
     RECT  88.98 31.15 104.04 31.775 ;
     RECT  17.46 31.575 32.94 31.845 ;
     RECT  86.095 31.155 86.705 31.845 ;
     RECT  178.26 31.155 181.265 31.845 ;
     RECT  207.055 31.155 207.665 31.845 ;
     RECT  165.3 30.805 176.46 31.85 ;
     RECT  86.1 31.645 86.705 32.105 ;
     RECT  88.975 31.575 104.04 32.105 ;
     RECT  17.46 31.645 29.1 32.265 ;
     RECT  50.58 28.26 54.06 32.265 ;
     RECT  76.015 31.225 84.04 32.265 ;
     RECT  52.02 32.065 54.06 32.685 ;
     RECT  57.78 31.575 73.745 32.685 ;
     RECT  165.3 31.65 168.305 33.035 ;
     RECT  57.78 32.485 72.78 33.08 ;
     RECT  17.46 32.065 25.74 33.525 ;
     RECT  35.215 31.225 48.78 33.525 ;
     RECT  32.34 31.645 32.94 33.875 ;
     RECT  170.92 31.65 176.46 33.875 ;
     RECT  178.26 31.645 181.26 33.875 ;
     RECT  187.86 30.315 188.46 33.875 ;
     RECT  159.06 31.225 159.66 33.945 ;
     RECT  224.945 33.775 226.575 34.265 ;
     RECT  165.295 32.835 168.305 34.285 ;
     RECT  20.04 33.325 25.74 34.295 ;
     RECT  27.54 32.065 29.1 34.295 ;
     RECT  32.335 33.675 32.945 34.295 ;
     RECT  76.02 32.065 84.04 34.295 ;
     RECT  159.535 34.085 160.14 34.295 ;
     RECT  164.34 34.085 168.305 34.295 ;
     RECT  170.92 33.675 181.745 34.295 ;
     RECT  159.535 34.095 181.745 34.365 ;
     RECT  187.855 33.675 188.465 34.365 ;
     RECT  149.46 30.315 154.92 34.715 ;
     RECT  35.22 33.325 48.78 34.76 ;
     RECT  32.335 34.095 33.425 34.785 ;
     RECT  159.535 34.165 181.74 34.79 ;
     RECT  124.12 29.865 124.52 34.815 ;
     RECT  145.72 19.195 146.12 34.815 ;
     RECT  145.715 34.615 146.125 35.105 ;
     RECT  20.04 34.095 29.1 35.135 ;
     RECT  52.5 32.485 54.06 35.135 ;
     RECT  57.3 32.88 72.78 35.135 ;
     RECT  75.055 34.095 84.04 35.135 ;
     RECT  35.22 34.56 50.22 35.205 ;
     RECT  148.975 34.515 154.92 35.205 ;
     RECT  159.535 34.59 164.945 35.205 ;
     RECT  166.74 34.59 180.78 35.21 ;
     RECT  160.495 35.005 163.5 35.625 ;
     RECT  166.74 35.01 178.86 35.625 ;
     RECT  17.46 33.325 18.06 35.975 ;
     RECT  20.04 34.935 30.06 35.975 ;
     RECT  32.335 34.585 33.42 35.975 ;
     RECT  49.62 35.005 50.22 35.975 ;
     RECT  52.495 34.935 54.06 35.975 ;
     RECT  57.3 34.935 84.04 35.975 ;
     RECT  86.1 31.905 104.04 35.975 ;
     RECT  124.12 34.615 126.445 36 ;
     RECT  57.3 35.775 104.04 36.135 ;
     RECT  124.12 35.8 126.92 36.2 ;
     RECT  20.04 35.775 33.42 36.42 ;
     RECT  17.455 35.775 18.065 36.465 ;
     RECT  30.9 36.22 33.42 36.465 ;
     RECT  35.22 35.005 47.34 36.465 ;
     RECT  49.62 35.775 54.06 36.465 ;
     RECT  35.22 36.265 46.86 36.815 ;
     RECT  35.215 36.615 46.86 37.305 ;
     RECT  79.375 35.935 104.04 37.305 ;
     RECT  228.145 37.555 229.775 38.045 ;
     RECT  166.74 35.425 168.78 38.075 ;
     RECT  148.98 35.005 154.92 38.495 ;
     RECT  160.5 35.425 163.5 38.495 ;
     RECT  166.74 37.875 168.785 38.495 ;
     RECT  170.92 35.425 175.5 38.495 ;
     RECT  178.26 35.425 178.86 38.495 ;
     RECT  16.02 38.295 16.62 38.54 ;
     RECT  16.02 38.34 18.06 38.91 ;
     RECT  20.04 36.22 29.1 38.91 ;
     RECT  49.62 36.265 50.7 38.91 ;
     RECT  30.9 36.265 32.94 38.915 ;
     RECT  35.22 37.105 46.86 38.915 ;
     RECT  147.055 38.295 157.265 38.915 ;
     RECT  16.02 38.71 29.1 38.985 ;
     RECT  147.055 38.715 158.225 38.985 ;
     RECT  35.22 38.715 46.865 39.335 ;
     RECT  49.62 38.71 51.18 39.335 ;
     RECT  52.98 36.265 54.06 39.335 ;
     RECT  57.3 35.935 76.62 39.335 ;
     RECT  79.38 37.105 104.04 39.335 ;
     RECT  30.895 38.715 32.94 39.405 ;
     RECT  35.215 39.135 46.865 39.405 ;
     RECT  147.06 38.785 158.225 39.405 ;
     RECT  160.5 38.295 178.86 39.405 ;
     RECT  147.06 39.205 158.22 39.41 ;
     RECT  167.22 39.205 177.9 39.41 ;
     RECT  35.215 39.205 45.9 39.825 ;
     RECT  49.62 39.135 55.025 39.825 ;
     RECT  157.62 39.21 158.22 39.83 ;
     RECT  57.3 39.135 104.04 39.97 ;
     RECT  31.855 39.205 32.94 40.175 ;
     RECT  139.86 30.315 140.46 40.22 ;
     RECT  16.495 38.785 29.1 40.245 ;
     RECT  139.86 40.02 143.34 40.62 ;
     RECT  147.06 39.21 155.82 40.62 ;
     RECT  39.055 39.625 44.945 40.665 ;
     RECT  57.3 39.77 75.66 41.015 ;
     RECT  31.855 39.975 33.905 41.505 ;
     RECT  56.815 40.815 75.66 41.505 ;
     RECT  224.945 41.335 226.575 41.825 ;
     RECT  149.94 40.42 155.82 41.855 ;
     RECT  160.5 39.205 165.42 41.855 ;
     RECT  167.7 39.21 176.94 41.855 ;
     RECT  31.86 41.305 33.905 42.32 ;
     RECT  149.94 41.655 155.825 42.345 ;
     RECT  160.015 41.655 178.385 42.345 ;
     RECT  31.86 42.12 35.34 42.72 ;
     RECT  39.06 40.465 44.94 42.765 ;
     RECT  160.02 42.145 162.06 42.77 ;
     RECT  165.3 42.145 178.38 42.77 ;
     RECT  56.82 41.305 75.66 43.115 ;
     RECT  77.46 39.77 104.04 43.115 ;
     RECT  18.42 40.045 26.705 43.535 ;
     RECT  28.5 40.045 29.1 43.535 ;
     RECT  31.86 42.52 32.945 43.535 ;
     RECT  18.42 43.335 32.945 43.98 ;
     RECT  18.42 43.78 28.62 44.025 ;
     RECT  30.415 43.78 32.945 44.025 ;
     RECT  39.54 42.565 44.94 44.375 ;
     RECT  39.54 44.175 45.9 44.865 ;
     RECT  56.82 42.915 104.04 44.885 ;
     RECT  49.62 39.625 55.02 45.26 ;
     RECT  56.82 44.685 68.94 45.26 ;
     RECT  228.145 45.115 229.775 45.605 ;
     RECT  167.7 42.57 178.38 46.055 ;
     RECT  39.54 44.665 45.42 46.475 ;
     RECT  49.62 45.06 68.94 46.475 ;
     RECT  34.74 42.52 35.34 46.545 ;
     RECT  167.7 45.855 179.34 46.545 ;
     RECT  18.42 43.825 26.22 46.895 ;
     RECT  70.74 44.685 76.62 46.895 ;
     RECT  37.615 46.275 45.42 46.965 ;
     RECT  47.695 46.275 68.94 46.965 ;
     RECT  167.7 46.345 168.3 46.965 ;
     RECT  170.1 46.345 179.34 46.97 ;
     RECT  18.42 46.695 27.18 47.315 ;
     RECT  30.42 43.825 32.46 47.315 ;
     RECT  18.42 47.115 32.46 47.385 ;
     RECT  47.7 46.765 68.94 47.53 ;
     RECT  70.74 46.695 77.1 47.53 ;
     RECT  26.1 47.185 32.46 48.155 ;
     RECT  37.615 46.765 38.22 48.575 ;
     RECT  190.92 29.965 194.92 48.575 ;
     RECT  182.58 48.375 183.18 48.62 ;
     RECT  187.38 48.375 187.98 48.62 ;
     RECT  190.26 48.375 194.92 48.62 ;
     RECT  26.1 47.955 34.38 48.645 ;
     RECT  40.04 46.765 45.42 48.995 ;
     RECT  130.26 29.965 134.92 49.04 ;
     RECT  136.98 48.795 137.58 49.04 ;
     RECT  26.1 48.445 33.42 49.065 ;
     RECT  36.175 48.375 38.22 49.065 ;
     RECT  6.52 25.665 6.92 49.095 ;
     RECT  182.58 48.42 184.62 49.35 ;
     RECT  6.035 48.895 6.92 49.385 ;
     RECT  224.945 48.895 226.575 49.385 ;
     RECT  251.315 48.895 251.725 49.385 ;
     RECT  130.26 48.84 137.58 49.415 ;
     RECT  142.74 40.42 143.34 49.415 ;
     RECT  147.06 40.42 147.66 49.415 ;
     RECT  187.38 48.42 194.92 49.415 ;
     RECT  177.78 46.77 179.34 49.46 ;
     RECT  182.1 49.15 184.62 49.46 ;
     RECT  186.9 49.215 194.92 49.46 ;
     RECT  130.26 49.215 147.66 49.485 ;
     RECT  40.04 48.795 45.905 49.835 ;
     RECT  49.14 47.33 68.94 49.835 ;
     RECT  76.02 47.33 77.1 49.835 ;
     RECT  78.9 44.685 104.04 49.835 ;
     RECT  177.78 49.26 194.92 49.86 ;
     RECT  183.06 49.66 194.92 49.905 ;
     RECT  251.315 49.185 251.72 50.225 ;
     RECT  40.04 49.635 68.94 50.28 ;
     RECT  187.86 49.705 194.92 50.28 ;
     RECT  70.74 47.33 74.22 50.3 ;
     RECT  76.02 49.635 104.04 50.3 ;
     RECT  36.18 48.865 38.22 50.325 ;
     RECT  40.04 50.08 47.82 50.325 ;
     RECT  137.46 49.285 147.66 50.33 ;
     RECT  18.42 47.185 24.04 50.67 ;
     RECT  26.1 48.865 27.18 50.67 ;
     RECT  149.94 42.145 154.92 50.675 ;
     RECT  141.295 50.13 147.66 50.745 ;
     RECT  210.52 25.245 212.36 50.775 ;
     RECT  250.36 50.15 250.765 50.775 ;
     RECT  49.62 50.08 68.94 50.95 ;
     RECT  70.74 50.1 104.04 50.95 ;
     RECT  210.52 50.575 212.365 51.065 ;
     RECT  250.355 50.575 250.765 51.065 ;
     RECT  49.62 50.75 104.04 51.255 ;
     RECT  18.42 50.47 27.18 51.585 ;
     RECT  59.22 51.055 104.04 51.585 ;
     RECT  26.575 51.385 27.18 51.935 ;
     RECT  30.42 48.865 33.42 51.935 ;
     RECT  26.575 51.735 27.185 52.425 ;
     RECT  30.415 51.735 33.42 52.425 ;
     RECT  60.04 51.385 89.1 52.425 ;
     RECT  141.78 50.545 147.66 52.775 ;
     RECT  149.46 50.475 154.92 52.775 ;
     RECT  170.92 46.77 175.5 52.775 ;
     RECT  177.78 49.66 180.78 52.775 ;
     RECT  183.06 49.705 186.06 52.775 ;
     RECT  141.78 52.575 147.665 52.82 ;
     RECT  149.46 52.575 157.265 52.82 ;
     RECT  170.92 52.575 187.02 52.82 ;
     RECT  188.82 50.08 194.92 52.82 ;
     RECT  228.145 52.675 229.775 53.165 ;
     RECT  60.04 52.225 76.625 53.265 ;
     RECT  141.78 52.62 157.265 53.265 ;
     RECT  207.055 52.575 207.665 53.265 ;
     RECT  40.04 50.125 46.385 53.595 ;
     RECT  40.04 53.395 47.34 53.615 ;
     RECT  49.62 51.055 57.42 53.615 ;
     RECT  130.26 49.285 135.66 53.615 ;
     RECT  137.46 50.13 138.06 53.615 ;
     RECT  141.78 53.065 157.26 53.615 ;
     RECT  78.9 52.225 89.1 53.66 ;
     RECT  90.895 51.385 104.04 53.66 ;
     RECT  170.92 52.62 194.92 53.685 ;
     RECT  207.06 53.065 207.66 53.69 ;
     RECT  37.62 50.125 38.22 54.03 ;
     RECT  40.04 53.415 57.42 54.03 ;
     RECT  187.38 53.485 194.92 54.035 ;
     RECT  196.98 53.415 197.58 54.035 ;
     RECT  170.92 53.485 185.1 54.06 ;
     RECT  179.22 53.86 185.1 54.105 ;
     RECT  18.42 51.385 24.04 54.455 ;
     RECT  183.54 53.905 184.62 54.53 ;
     RECT  18.42 54.255 24.78 54.785 ;
     RECT  27.055 54.255 27.665 54.785 ;
     RECT  37.62 53.83 57.42 54.875 ;
     RECT  18.42 54.585 27.665 54.9 ;
     RECT  18.895 54.7 27.665 54.945 ;
     RECT  30.42 52.225 33.42 54.945 ;
     RECT  37.62 54.675 57.425 54.945 ;
     RECT  37.62 54.745 52.62 55.09 ;
     RECT  78.9 53.46 104.04 55.09 ;
     RECT  160.02 42.57 160.62 55.34 ;
     RECT  38.575 54.89 52.62 55.365 ;
     RECT  54.42 54.745 57.425 55.365 ;
     RECT  179.22 53.905 181.74 56.135 ;
     RECT  183.54 54.33 184.14 56.135 ;
     RECT  130.26 53.415 138.06 56.18 ;
     RECT  141.3 53.415 157.26 56.18 ;
     RECT  159.06 55.14 160.62 56.555 ;
     RECT  224.945 56.455 226.575 56.945 ;
     RECT  159.06 56.355 161.1 56.965 ;
     RECT  159.06 56.765 163.02 56.975 ;
     RECT  165.3 42.57 165.9 56.975 ;
     RECT  170.92 53.86 176.94 56.975 ;
     RECT  179.22 55.935 184.14 56.975 ;
     RECT  16.98 56.77 17.58 57.395 ;
     RECT  19.375 54.745 27.66 57.395 ;
     RECT  30.42 54.745 32.46 57.395 ;
     RECT  78.9 54.89 87.18 57.395 ;
     RECT  88.98 54.89 104.04 57.395 ;
     RECT  130.26 55.98 157.26 57.395 ;
     RECT  159.06 56.775 165.9 57.395 ;
     RECT  167.695 56.775 168.305 57.465 ;
     RECT  187.38 53.835 197.58 57.475 ;
     RECT  16.975 57.195 17.585 57.815 ;
     RECT  19.375 57.195 32.46 57.815 ;
     RECT  78.9 57.195 104.04 57.815 ;
     RECT  78.42 57.615 104.04 57.84 ;
     RECT  60.04 53.065 76.62 57.86 ;
     RECT  78.42 57.64 87.66 57.86 ;
     RECT  16.975 57.615 32.945 57.885 ;
     RECT  60.04 57.66 87.66 57.885 ;
     RECT  130.26 57.195 165.9 57.89 ;
     RECT  170.92 56.775 184.14 57.89 ;
     RECT  38.58 55.165 52.62 58.225 ;
     RECT  54.42 55.165 57.42 58.225 ;
     RECT  178.735 57.69 184.14 58.28 ;
     RECT  18.415 57.685 32.945 58.305 ;
     RECT  178.735 58.08 185.58 58.305 ;
     RECT  18.42 58.105 32.945 58.645 ;
     RECT  178.74 58.105 185.58 58.7 ;
     RECT  187.38 57.275 194.92 58.7 ;
     RECT  18.42 58.445 33.42 59.075 ;
     RECT  38.58 58.025 57.42 59.075 ;
     RECT  170.92 57.69 175.985 59.075 ;
     RECT  18.42 58.875 33.425 59.145 ;
     RECT  38.575 58.875 57.42 59.145 ;
     RECT  130.26 57.69 154.92 59.495 ;
     RECT  167.7 57.265 168.3 59.495 ;
     RECT  170.095 58.875 175.985 59.495 ;
     RECT  30.42 58.945 33.425 59.565 ;
     RECT  38.575 58.945 52.62 59.565 ;
     RECT  207.055 58.875 207.665 59.565 ;
     RECT  54.42 58.945 57.42 59.785 ;
     RECT  54.42 59.585 57.9 59.915 ;
     RECT  60.04 57.685 87.185 59.915 ;
     RECT  89.455 57.64 104.04 59.915 ;
     RECT  129.775 59.295 154.92 59.985 ;
     RECT  157.615 57.69 165.9 59.985 ;
     RECT  157.62 59.785 165.9 60.38 ;
     RECT  167.7 59.295 175.985 60.38 ;
     RECT  207.06 59.365 207.66 60.405 ;
     RECT  228.145 60.235 229.775 60.725 ;
     RECT  33.295 59.585 33.9 60.755 ;
     RECT  126.52 36 126.92 61.175 ;
     RECT  129.775 59.785 141.9 61.175 ;
     RECT  157.62 60.18 175.985 61.175 ;
     RECT  178.74 58.5 194.92 61.175 ;
     RECT  196.98 57.275 197.58 61.22 ;
     RECT  33.295 60.555 33.905 61.245 ;
     RECT  54.42 59.715 104.04 61.245 ;
     RECT  38.58 59.365 52.62 61.595 ;
     RECT  54.42 61.045 55.02 61.595 ;
     RECT  157.62 60.975 194.92 61.595 ;
     RECT  196.98 61.02 199.5 61.595 ;
     RECT  157.62 61.395 199.5 61.62 ;
     RECT  177.3 61.42 199.5 61.665 ;
     RECT  33.775 61.395 34.385 62.015 ;
     RECT  38.58 61.395 55.02 62.015 ;
     RECT  157.62 61.42 174.92 62.015 ;
     RECT  33.775 61.815 36.3 62.06 ;
     RECT  38.1 61.815 55.02 62.06 ;
     RECT  143.7 59.785 154.92 62.06 ;
     RECT  156.66 61.815 174.92 62.06 ;
     RECT  33.775 61.86 55.02 62.085 ;
     RECT  16.975 61.815 17.585 62.505 ;
     RECT  126.52 60.975 141.9 62.505 ;
     RECT  143.7 61.86 174.92 62.505 ;
     RECT  198.415 61.465 199.5 62.505 ;
     RECT  33.78 61.885 55.02 62.925 ;
     RECT  224.945 64.015 226.575 64.505 ;
     RECT  30.42 59.365 31.5 64.535 ;
     RECT  130.26 62.305 141.9 64.535 ;
     RECT  143.7 62.305 160.62 64.535 ;
     RECT  177.3 61.465 196.14 64.535 ;
     RECT  198.42 62.305 199.5 64.535 ;
     RECT  162.9 62.305 174.92 64.955 ;
     RECT  130.26 64.335 160.62 65.025 ;
     RECT  177.3 64.335 199.5 65.025 ;
     RECT  19.38 58.945 27.66 65.375 ;
     RECT  30.42 64.335 31.985 65.375 ;
     RECT  33.78 62.725 44.04 65.375 ;
     RECT  45.775 62.725 55.02 65.375 ;
     RECT  126.52 62.305 127.98 65.375 ;
     RECT  162.895 64.755 174.92 65.375 ;
     RECT  16.98 62.305 17.58 65.42 ;
     RECT  19.38 65.175 55.02 65.42 ;
     RECT  16.98 65.22 55.02 65.445 ;
     RECT  130.26 64.825 155.825 65.445 ;
     RECT  162.895 65.175 175.505 65.445 ;
     RECT  180.655 64.825 199.5 65.445 ;
     RECT  130.26 65.245 146.22 65.45 ;
     RECT  177.78 64.825 178.86 65.45 ;
     RECT  182.58 65.245 199.5 65.82 ;
     RECT  126.52 65.175 127.985 65.865 ;
     RECT  148.975 65.245 155.825 65.865 ;
     RECT  163.375 65.245 175.505 65.865 ;
     RECT  183.54 65.62 186.54 65.865 ;
     RECT  158.1 64.825 160.62 66.215 ;
     RECT  164.82 65.665 175.5 66.285 ;
     RECT  148.98 65.665 155.82 66.29 ;
     RECT  183.54 65.665 185.1 66.29 ;
     RECT  158.1 66.015 160.625 67.52 ;
     RECT  162.42 67.275 163.02 67.52 ;
     RECT  158.1 67.32 163.02 67.94 ;
     RECT  164.82 66.085 168.78 67.94 ;
     RECT  228.145 67.795 229.775 68.285 ;
     RECT  17.94 65.245 55.02 68.735 ;
     RECT  57.3 61.045 104.04 68.735 ;
     RECT  130.26 65.25 145.74 68.735 ;
     RECT  158.1 67.74 168.78 68.735 ;
     RECT  183.54 66.09 184.62 68.735 ;
     RECT  130.26 68.535 145.745 68.805 ;
     RECT  136.98 68.605 145.745 69.225 ;
     RECT  156.655 68.535 168.78 69.225 ;
     RECT  183.54 68.535 184.625 69.225 ;
     RECT  136.98 69.025 141.9 69.65 ;
     RECT  183.54 69.025 184.62 70.02 ;
     RECT  143.7 69.025 145.26 71.255 ;
     RECT  139.38 69.45 141.9 71.3 ;
     RECT  143.7 71.055 145.265 71.3 ;
     RECT  177.78 65.25 178.38 71.3 ;
     RECT  170.92 66.085 175.5 71.67 ;
     RECT  177.3 71.1 178.38 71.67 ;
     RECT  156.66 69.025 167.82 71.675 ;
     RECT  17.94 68.535 104.04 71.745 ;
     RECT  224.945 71.575 226.575 72.065 ;
     RECT  130.26 68.605 134.92 72.095 ;
     RECT  136.98 69.45 137.58 72.095 ;
     RECT  148.98 66.09 154.92 72.095 ;
     RECT  156.66 71.475 168.305 72.095 ;
     RECT  139.38 71.1 145.265 72.14 ;
     RECT  148.495 71.895 168.78 72.14 ;
     RECT  170.92 71.47 178.38 72.14 ;
     RECT  139.38 71.94 146.22 72.515 ;
     RECT  148.02 71.94 168.78 72.515 ;
     RECT  184.02 69.82 184.62 72.515 ;
     RECT  130.255 71.895 137.58 72.585 ;
     RECT  17.94 71.545 66.545 72.96 ;
     RECT  139.38 72.315 168.785 73.005 ;
     RECT  184.015 72.315 184.625 73.005 ;
     RECT  207.055 72.315 207.665 73.005 ;
     RECT  139.38 72.805 168.78 73.01 ;
     RECT  139.38 72.81 165.42 73.38 ;
     RECT  139.38 73.18 157.745 73.425 ;
     RECT  160.02 73.18 165.42 73.425 ;
     RECT  167.215 72.81 168.78 73.425 ;
     RECT  207.06 72.805 207.66 73.43 ;
     RECT  49.62 72.76 66.545 73.845 ;
     RECT  161.94 73.225 165.42 73.845 ;
     RECT  167.22 73.225 168.78 74.64 ;
     RECT  17.94 72.76 47.825 75.455 ;
     RECT  49.62 73.645 66.06 75.455 ;
     RECT  68.34 71.545 104.04 75.455 ;
     RECT  157.135 73.225 157.745 75.525 ;
     RECT  228.145 75.355 229.775 75.845 ;
     RECT  17.94 75.255 66.06 75.9 ;
     RECT  38.575 75.7 66.06 75.945 ;
     RECT  68.335 75.255 104.04 76.295 ;
     RECT  170.92 71.94 180.78 76.295 ;
     RECT  188.34 65.62 199.5 76.295 ;
     RECT  201.3 53.415 201.9 76.295 ;
     RECT  130.92 72.385 137.58 76.715 ;
     RECT  139.38 73.225 154.92 76.715 ;
     RECT  67.86 76.095 104.04 76.785 ;
     RECT  170.92 76.095 181.745 77.21 ;
     RECT  17.94 75.7 36.785 77.55 ;
     RECT  16.98 77.35 36.785 77.625 ;
     RECT  16.98 77.425 30.06 77.975 ;
     RECT  188.34 76.095 201.9 77.975 ;
     RECT  31.86 77.425 36.785 78.045 ;
     RECT  188.34 77.775 201.905 78.395 ;
     RECT  16.975 77.775 30.06 78.465 ;
     RECT  186.895 78.195 201.905 79.23 ;
     RECT  186.895 79.03 202.86 79.235 ;
     RECT  68.34 76.585 104.04 79.305 ;
     RECT  130.92 76.515 154.92 79.305 ;
     RECT  170.92 77.01 179.82 79.305 ;
     RECT  224.945 79.135 226.575 79.625 ;
     RECT  17.94 78.265 30.06 79.655 ;
     RECT  31.86 77.845 36.78 79.655 ;
     RECT  163.86 73.645 165.42 79.655 ;
     RECT  167.22 74.44 167.82 79.655 ;
     RECT  182.575 77.775 183.185 79.655 ;
     RECT  185.455 79.035 202.86 79.655 ;
     RECT  182.575 79.455 203.82 79.7 ;
     RECT  170.92 79.105 175.985 79.725 ;
     RECT  139.86 79.105 154.92 79.73 ;
     RECT  17.94 79.455 36.78 80.075 ;
     RECT  68.34 79.105 74.7 80.075 ;
     RECT  143.22 79.53 154.92 80.145 ;
     RECT  163.86 79.455 167.82 80.145 ;
     RECT  164.34 79.945 164.94 80.57 ;
     RECT  182.1 79.5 203.82 80.57 ;
     RECT  40.04 75.745 66.06 80.905 ;
     RECT  68.335 79.875 74.7 80.905 ;
     RECT  160.02 79.455 160.62 80.915 ;
     RECT  166.74 79.945 167.82 80.915 ;
     RECT  190.92 80.37 203.82 80.985 ;
     RECT  159.54 80.715 160.62 81.755 ;
     RECT  170.92 79.525 175.98 81.755 ;
     RECT  203.215 80.785 203.82 81.755 ;
     RECT  76.5 79.105 104.04 81.83 ;
     RECT  251.315 81.655 251.725 82.145 ;
     RECT  17.94 79.875 38.225 82.175 ;
     RECT  40.04 80.705 74.7 82.175 ;
     RECT  139.86 79.53 140.94 82.175 ;
     RECT  143.7 79.945 154.92 82.175 ;
     RECT  178.74 79.105 179.82 82.175 ;
     RECT  182.1 80.37 188.94 82.175 ;
     RECT  143.7 81.975 155.825 82.245 ;
     RECT  170.92 81.555 176.945 82.245 ;
     RECT  203.215 81.555 203.825 82.245 ;
     RECT  17.94 81.975 74.7 82.25 ;
     RECT  170.92 82.045 176.94 83.085 ;
     RECT  228.145 82.915 229.775 83.405 ;
     RECT  37.14 82.05 74.7 83.435 ;
     RECT  139.855 81.975 140.94 83.845 ;
     RECT  143.7 82.045 148.14 83.845 ;
     RECT  159.055 81.555 160.62 83.845 ;
     RECT  130.92 79.105 137.58 83.855 ;
     RECT  139.855 83.645 148.14 83.855 ;
     RECT  150.92 82.045 155.825 83.855 ;
     RECT  159.055 83.645 162.06 83.855 ;
     RECT  91.375 81.63 104.04 83.925 ;
     RECT  219.16 21.045 219.56 83.955 ;
     RECT  248.92 83.33 249.32 83.955 ;
     RECT  251.315 81.945 251.72 83.955 ;
     RECT  219.155 83.755 219.565 84.245 ;
     RECT  248.915 83.755 251.72 84.245 ;
     RECT  37.14 83.235 74.705 84.27 ;
     RECT  76.5 81.63 89.58 84.27 ;
     RECT  150.92 83.655 162.06 84.275 ;
     RECT  150.92 84.075 162.065 84.345 ;
     RECT  170.92 82.885 175.98 84.345 ;
     RECT  17.94 82.05 35.34 84.695 ;
     RECT  37.14 84.07 89.58 84.695 ;
     RECT  178.74 81.975 188.94 84.72 ;
     RECT  130.92 83.655 148.14 84.765 ;
     RECT  157.14 84.145 162.065 84.765 ;
     RECT  178.74 84.52 184.14 84.765 ;
     RECT  166.74 80.715 168.3 85.115 ;
     RECT  190.92 80.785 200.94 85.115 ;
     RECT  190.92 84.915 200.945 85.14 ;
     RECT  16.975 84.495 89.58 85.185 ;
     RECT  40.04 84.985 89.58 85.33 ;
     RECT  250.36 84.045 250.76 85.505 ;
     RECT  49.62 85.13 89.58 85.605 ;
     RECT  197.94 84.94 200.945 85.605 ;
     RECT  16.98 84.985 17.58 86.025 ;
     RECT  33.3 84.985 38.22 86.025 ;
     RECT  170.92 84.145 175.505 86.375 ;
     RECT  121.24 29.025 122.12 86.4 ;
     RECT  124.12 36 124.52 86.4 ;
     RECT  170.92 86.175 176.46 86.42 ;
     RECT  178.74 84.565 181.26 86.42 ;
     RECT  121.24 86.2 124.52 86.6 ;
     RECT  49.62 85.405 68.945 86.865 ;
     RECT  170.92 86.22 181.26 86.865 ;
     RECT  224.945 86.695 226.575 87.185 ;
     RECT  157.14 84.565 162.06 87.215 ;
     RECT  165.295 84.915 168.3 87.215 ;
     RECT  170.92 86.665 175.505 87.215 ;
     RECT  185.94 84.52 188.94 87.215 ;
     RECT  20.04 84.985 31.5 87.26 ;
     RECT  33.3 85.825 35.345 87.26 ;
     RECT  143.7 84.565 148.14 87.635 ;
     RECT  150.92 84.145 154.92 87.635 ;
     RECT  157.14 87.015 175.505 87.635 ;
     RECT  49.62 86.665 68.94 87.68 ;
     RECT  150.92 87.435 175.505 87.705 ;
     RECT  177.295 86.665 181.26 87.705 ;
     RECT  185.935 87.015 188.94 87.705 ;
     RECT  40.04 85.13 47.34 88.045 ;
     RECT  49.14 87.48 68.94 88.045 ;
     RECT  20.04 87.06 35.345 88.05 ;
     RECT  37.14 85.825 38.22 88.05 ;
     RECT  71.22 85.405 89.58 88.05 ;
     RECT  91.38 83.725 104.04 88.05 ;
     RECT  143.7 87.435 148.145 88.125 ;
     RECT  150.92 87.505 161.585 88.125 ;
     RECT  163.38 87.505 175.505 88.125 ;
     RECT  177.3 87.505 177.9 88.13 ;
     RECT  180.18 87.505 181.26 88.545 ;
     RECT  163.38 87.925 175.5 88.55 ;
     RECT  20.04 87.85 38.22 88.895 ;
     RECT  40.04 87.845 68.94 88.895 ;
     RECT  20.04 88.695 68.94 89.36 ;
     RECT  71.22 87.85 104.04 89.36 ;
     RECT  20.04 89.16 104.04 89.385 ;
     RECT  150.92 87.925 161.58 89.39 ;
     RECT  163.38 88.35 174.92 90.6 ;
     RECT  130.92 84.565 140.94 90.645 ;
     RECT  164.34 90.4 174.92 90.645 ;
     RECT  228.145 90.475 229.775 90.965 ;
     RECT  136.98 90.445 140.94 91.415 ;
     RECT  143.7 87.925 146.22 91.415 ;
     RECT  190.92 84.94 194.92 91.415 ;
     RECT  197.94 85.405 199.98 91.415 ;
     RECT  20.04 89.185 28.145 91.485 ;
     RECT  29.94 89.185 91.98 91.835 ;
     RECT  29.94 91.635 91.985 91.905 ;
     RECT  143.7 91.215 148.14 91.905 ;
     RECT  190.92 91.215 202.86 92.325 ;
     RECT  164.82 90.445 174.92 92.7 ;
     RECT  36.18 91.705 45.42 92.745 ;
     RECT  47.7 91.705 91.985 92.745 ;
     RECT  165.78 92.5 174.92 92.745 ;
     RECT  52.975 92.545 91.985 92.955 ;
     RECT  47.7 92.545 50.7 93.585 ;
     RECT  130.92 90.445 134.92 93.935 ;
     RECT  136.98 91.215 141.9 93.935 ;
     RECT  143.7 91.705 147.18 93.935 ;
     RECT  67.38 92.755 91.985 93.98 ;
     RECT  93.78 89.185 104.04 93.98 ;
     RECT  130.92 93.735 141.905 94.425 ;
     RECT  143.695 93.735 147.665 94.425 ;
     RECT  160.98 89.19 161.58 94.425 ;
     RECT  167.22 92.545 174.92 94.425 ;
     RECT  180.18 88.345 180.78 94.425 ;
     RECT  224.945 94.255 226.575 94.745 ;
     RECT  145.14 94.225 147.665 94.765 ;
     RECT  20.04 91.285 27.18 94.77 ;
     RECT  29.94 91.705 34.38 94.775 ;
     RECT  36.18 92.545 38.22 94.775 ;
     RECT  145.14 94.565 148.14 94.775 ;
     RECT  150.92 89.19 157.74 94.775 ;
     RECT  182.575 94.155 183.185 94.775 ;
     RECT  186.42 87.505 188.94 94.775 ;
     RECT  190.92 92.125 197.1 94.775 ;
     RECT  181.135 94.575 183.185 94.845 ;
     RECT  130.92 94.225 140.945 94.85 ;
     RECT  18.9 94.57 27.18 95.195 ;
     RECT  52.975 92.755 65.58 95.195 ;
     RECT  67.38 93.78 104.04 95.195 ;
     RECT  145.14 94.575 158.705 95.265 ;
     RECT  168.655 94.225 174.92 95.265 ;
     RECT  181.135 94.645 183.18 95.265 ;
     RECT  181.14 95.065 183.18 95.275 ;
     RECT  205.14 94.575 207.66 95.615 ;
     RECT  145.14 95.065 158.7 95.685 ;
     RECT  149.46 95.485 158.7 95.69 ;
     RECT  168.66 95.065 174.92 95.69 ;
     RECT  181.14 95.075 181.74 95.69 ;
     RECT  52.015 94.995 104.04 95.78 ;
     RECT  47.7 93.385 49.26 96.035 ;
     RECT  29.94 94.575 38.22 96.08 ;
     RECT  40.04 92.545 45.42 96.08 ;
     RECT  186.42 94.575 197.1 96.105 ;
     RECT  205.14 95.415 207.665 96.105 ;
     RECT  17.455 94.995 27.18 96.455 ;
     RECT  67.86 95.58 104.04 96.525 ;
     RECT  190.26 95.905 197.1 96.875 ;
     RECT  198.9 92.125 202.86 96.875 ;
     RECT  17.455 96.255 27.185 96.945 ;
     RECT  52.015 95.58 66.065 96.945 ;
     RECT  17.455 96.745 18.06 97.295 ;
     RECT  198.9 96.675 202.865 97.295 ;
     RECT  52.015 96.745 52.625 97.365 ;
     RECT  54.415 96.745 66.06 97.365 ;
     RECT  68.34 96.325 104.04 97.365 ;
     RECT  198.895 97.095 202.865 97.365 ;
     RECT  161.46 94.575 162.06 97.715 ;
     RECT  168.175 97.095 168.785 97.715 ;
     RECT  136.98 94.65 140.945 97.76 ;
     RECT  145.14 95.485 147.18 97.76 ;
     RECT  16.98 97.095 18.06 97.785 ;
     RECT  198.895 97.165 201.9 97.785 ;
     RECT  47.695 95.835 49.26 97.895 ;
     RECT  161.455 97.515 162.065 98.205 ;
     RECT  186.42 95.905 187.5 98.205 ;
     RECT  205.14 95.905 207.66 98.205 ;
     RECT  228.145 98.035 229.775 98.525 ;
     RECT  136.98 97.56 147.18 98.555 ;
     RECT  29.94 95.88 45.42 98.625 ;
     RECT  167.215 97.515 168.785 98.63 ;
     RECT  29.94 98.425 32.94 98.975 ;
     RECT  52.015 97.165 52.62 98.975 ;
     RECT  136.975 98.355 147.18 98.975 ;
     RECT  168.175 98.43 168.785 98.975 ;
     RECT  170.92 95.49 174.92 98.975 ;
     RECT  186.42 98.005 187.025 98.975 ;
     RECT  190.26 96.675 197.105 98.975 ;
     RECT  205.14 98.005 207.18 98.975 ;
     RECT  136.975 98.775 148.62 99.045 ;
     RECT  168.175 98.775 174.92 99.045 ;
     RECT  68.34 97.165 97.26 99.13 ;
     RECT  68.34 98.93 70.38 99.175 ;
     RECT  47.695 97.695 48.785 99.39 ;
     RECT  145.135 98.845 148.62 99.395 ;
     RECT  168.18 98.845 174.92 99.395 ;
     RECT  176.815 98.775 177.425 99.395 ;
     RECT  29.935 98.775 32.94 99.465 ;
     RECT  47.22 99.19 48.785 99.465 ;
     RECT  51.535 98.775 52.62 99.465 ;
     RECT  165.295 98.775 165.905 99.465 ;
     RECT  168.18 99.195 177.425 99.465 ;
     RECT  180.175 98.775 181.74 99.465 ;
     RECT  186.415 98.775 187.025 99.465 ;
     RECT  190.26 98.775 197.585 99.465 ;
     RECT  200.82 97.585 201.9 99.465 ;
     RECT  205.135 98.775 207.18 99.465 ;
     RECT  137.94 98.845 142.865 99.47 ;
     RECT  72.18 98.93 97.26 99.475 ;
     RECT  47.22 99.265 48.78 99.75 ;
     RECT  47.22 99.55 48.3 99.815 ;
     RECT  100.04 97.165 104.04 99.815 ;
     RECT  145.135 99.195 149.105 99.815 ;
     RECT  150.92 95.49 158.7 99.815 ;
     RECT  168.18 99.265 177.42 99.89 ;
     RECT  190.26 99.265 197.58 99.89 ;
     RECT  55.38 97.165 66.06 100.145 ;
     RECT  29.94 99.265 32.94 100.26 ;
     RECT  17.46 97.585 18.06 100.305 ;
     RECT  29.94 100.06 31.98 100.305 ;
     RECT  34.74 98.425 45.42 100.305 ;
     RECT  47.215 99.615 48.3 100.305 ;
     RECT  54.9 99.945 66.06 100.305 ;
     RECT  68.34 98.975 69.905 100.305 ;
     RECT  73.14 99.275 97.26 100.305 ;
     RECT  99.055 99.615 104.04 100.305 ;
     RECT  142.255 99.27 142.865 100.305 ;
     RECT  145.135 99.615 158.7 100.305 ;
     RECT  168.18 99.69 175.5 100.305 ;
     RECT  76.98 100.105 92.94 100.405 ;
     RECT  95.7 100.105 97.26 100.45 ;
     RECT  20.04 96.745 27.18 100.65 ;
     RECT  36.66 100.105 45.42 100.65 ;
     RECT  73.14 100.105 75.18 100.725 ;
     RECT  68.34 100.105 69.42 101.075 ;
     RECT  18.895 100.45 27.18 101.565 ;
     RECT  36.66 100.45 46.385 101.565 ;
     RECT  67.38 100.875 69.42 101.565 ;
     RECT  77.46 100.205 92.94 101.565 ;
     RECT  130.92 94.65 134.92 101.915 ;
     RECT  137.94 99.27 139.98 101.915 ;
     RECT  142.26 100.105 142.865 101.915 ;
     RECT  161.46 98.005 162.06 101.915 ;
     RECT  165.3 99.265 165.9 101.915 ;
     RECT  180.18 99.265 181.74 101.915 ;
     RECT  200.82 99.265 201.42 101.915 ;
     RECT  130.92 101.715 139.98 101.985 ;
     RECT  146.58 100.105 158.7 101.985 ;
     RECT  190.26 99.69 197.1 101.985 ;
     RECT  224.945 101.815 226.575 102.305 ;
     RECT  77.46 101.365 85.265 102.33 ;
     RECT  168.18 100.105 168.78 102.335 ;
     RECT  170.92 100.105 175.5 102.335 ;
     RECT  180.18 101.715 181.745 102.335 ;
     RECT  205.14 99.265 207.18 102.335 ;
     RECT  87.055 101.365 92.94 102.38 ;
     RECT  96.18 100.25 97.26 102.38 ;
     RECT  130.92 101.785 136.625 102.405 ;
     RECT  138.415 101.785 139.98 102.405 ;
     RECT  142.26 101.715 144.305 102.405 ;
     RECT  146.58 101.785 157.74 102.405 ;
     RECT  161.455 101.715 162.065 102.405 ;
     RECT  163.855 101.715 165.9 102.405 ;
     RECT  184.495 101.715 185.105 102.405 ;
     RECT  200.815 101.715 201.425 102.405 ;
     RECT  36.66 101.365 45.42 102.755 ;
     RECT  54.9 100.105 64.04 102.755 ;
     RECT  76.98 102.13 85.265 102.755 ;
     RECT  87.055 102.18 97.26 102.78 ;
     RECT  168.18 102.135 175.98 102.825 ;
     RECT  205.14 102.135 207.66 102.825 ;
     RECT  142.26 102.205 144.3 102.835 ;
     RECT  163.86 102.205 165.9 102.835 ;
     RECT  184.5 102.205 185.1 102.835 ;
     RECT  200.82 102.205 201.42 102.835 ;
     RECT  51.54 99.265 52.62 103.175 ;
     RECT  178.26 102.135 181.745 103.22 ;
     RECT  87.055 102.58 91.5 103.245 ;
     RECT  68.82 101.365 69.42 103.585 ;
     RECT  93.295 102.58 97.26 103.59 ;
     RECT  99.06 100.105 104.04 103.59 ;
     RECT  178.26 103.02 182.7 103.62 ;
     RECT  190.92 101.785 197.1 103.62 ;
     RECT  29.94 100.105 31.5 103.64 ;
     RECT  76.975 102.555 85.265 103.665 ;
     RECT  19.375 101.365 27.18 104.015 ;
     RECT  29.94 103.44 31.98 104.015 ;
     RECT  36.655 102.555 45.42 104.015 ;
     RECT  47.7 103.385 48.3 104.015 ;
     RECT  50.1 102.975 52.62 104.015 ;
     RECT  54.895 102.555 64.04 104.015 ;
     RECT  67.38 103.385 69.42 104.015 ;
     RECT  73.62 100.525 75.18 104.015 ;
     RECT  76.975 103.465 84.04 104.015 ;
     RECT  190.92 103.42 196.86 104.04 ;
     RECT  93.295 103.39 104.04 104.085 ;
     RECT  54.42 103.815 64.04 104.175 ;
     RECT  130.92 102.205 136.62 104.435 ;
     RECT  142.26 102.635 142.865 104.435 ;
     RECT  47.695 103.815 52.62 104.46 ;
     RECT  19.375 103.815 27.185 104.505 ;
     RECT  29.935 103.815 31.98 104.505 ;
     RECT  36.175 103.815 45.42 104.505 ;
     RECT  47.695 104.26 49.74 104.505 ;
     RECT  51.54 104.26 52.62 104.505 ;
     RECT  67.375 103.815 69.42 104.505 ;
     RECT  73.62 103.815 84.04 104.505 ;
     RECT  87.535 103.045 91.5 104.505 ;
     RECT  36.18 104.305 38.22 104.515 ;
     RECT  93.3 103.885 104.04 104.515 ;
     RECT  19.375 104.305 27.18 104.855 ;
     RECT  90.415 104.305 91.5 104.855 ;
     RECT  18.42 104.655 27.18 104.9 ;
     RECT  78.415 104.305 84.04 104.925 ;
     RECT  130.92 104.235 137.585 104.925 ;
     RECT  142.255 104.235 142.865 104.925 ;
     RECT  54.42 103.975 55.02 105.145 ;
     RECT  170.1 102.625 175.98 105.275 ;
     RECT  16.98 104.7 27.18 105.345 ;
     RECT  73.62 104.305 76.62 105.345 ;
     RECT  87.535 104.305 88.62 105.345 ;
     RECT  90.415 104.655 91.505 105.345 ;
     RECT  79.38 104.725 84.04 105.365 ;
     RECT  146.58 102.205 149.1 105.72 ;
     RECT  52.495 104.945 55.02 105.765 ;
     RECT  90.415 105.145 91.025 105.765 ;
     RECT  147.06 105.52 149.1 105.765 ;
     RECT  150.92 102.205 157.74 105.765 ;
     RECT  179.215 103.42 179.825 105.765 ;
     RECT  182.1 103.42 182.7 105.765 ;
     RECT  52.5 105.565 55.02 106.065 ;
     RECT  228.145 105.595 229.775 106.085 ;
     RECT  56.82 103.975 64.04 106.11 ;
     RECT  150.92 105.565 154.92 106.115 ;
     RECT  161.46 102.205 162.06 106.115 ;
     RECT  165.3 102.635 165.9 106.115 ;
     RECT  170.1 105.075 175.985 106.115 ;
     RECT  179.22 105.565 179.825 106.115 ;
     RECT  190.92 103.84 195.665 106.115 ;
     RECT  203.22 105.495 203.82 106.115 ;
     RECT  206.58 102.625 207.66 106.115 ;
     RECT  187.86 105.915 188.46 106.16 ;
     RECT  202.26 105.915 203.82 106.16 ;
     RECT  206.58 105.915 208.14 106.16 ;
     RECT  210.52 50.865 212.36 106.16 ;
     RECT  179.22 105.915 180.78 106.19 ;
     RECT  31.38 104.305 31.98 106.535 ;
     RECT  33.78 100.875 34.38 106.535 ;
     RECT  56.82 105.91 64.62 106.535 ;
     RECT  73.62 105.145 74.225 106.535 ;
     RECT  76.015 105.145 76.62 106.535 ;
     RECT  139.38 102.205 139.98 106.535 ;
     RECT  161.46 105.915 165.9 106.535 ;
     RECT  187.38 105.96 188.46 106.535 ;
     RECT  201.78 105.96 212.36 106.56 ;
     RECT  169.14 105.915 176.465 106.605 ;
     RECT  179.7 105.99 180.78 106.605 ;
     RECT  186.895 106.335 188.46 106.605 ;
     RECT  190.92 105.915 196.62 106.605 ;
     RECT  201.78 106.36 202.86 106.605 ;
     RECT  207.54 106.36 212.36 106.605 ;
     RECT  160.98 106.335 165.9 106.945 ;
     RECT  160.98 106.745 167.825 106.98 ;
     RECT  36.18 104.315 37.26 107.025 ;
     RECT  73.615 106.335 74.225 107.025 ;
     RECT  76.015 106.335 76.625 107.025 ;
     RECT  87.54 105.145 88.62 107.025 ;
     RECT  130.92 104.725 137.58 107.025 ;
     RECT  139.38 106.335 141.905 107.025 ;
     RECT  160.98 106.78 161.58 107.025 ;
     RECT  163.38 106.78 167.825 107.025 ;
     RECT  182.575 106.335 183.185 107.025 ;
     RECT  186.895 106.405 187.98 107.025 ;
     RECT  170.1 106.405 176.46 107.03 ;
     RECT  139.38 106.825 141.9 107.4 ;
     RECT  140.34 107.2 141.9 107.45 ;
     RECT  182.58 106.825 183.18 107.45 ;
     RECT  56.815 106.335 64.625 107.795 ;
     RECT  93.78 104.315 104.04 107.795 ;
     RECT  20.04 105.145 27.18 107.82 ;
     RECT  31.38 106.335 34.38 107.865 ;
     RECT  36.66 106.825 37.26 107.865 ;
     RECT  56.815 107.595 65.58 107.865 ;
     RECT  92.82 107.595 104.04 107.865 ;
     RECT  167.215 106.825 167.825 107.865 ;
     RECT  170.1 106.83 175.505 107.865 ;
     RECT  186.9 106.825 187.98 107.865 ;
     RECT  201.78 106.405 202.38 107.895 ;
     RECT  209.46 106.405 212.36 107.895 ;
     RECT  31.38 107.665 32.94 108.01 ;
     RECT  199.955 107.695 202.38 108.185 ;
     RECT  209.46 107.695 212.365 108.185 ;
     RECT  88.5 107.595 90.06 108.21 ;
     RECT  92.82 107.665 96.3 108.24 ;
     RECT  54.42 105.865 55.02 108.26 ;
     RECT  56.815 107.665 57.42 108.26 ;
     RECT  60.04 107.665 65.58 108.285 ;
     RECT  74.58 107.595 75.66 108.285 ;
     RECT  95.7 108.04 96.3 108.285 ;
     RECT  170.1 107.665 175.5 108.29 ;
     RECT  88.5 108.01 91.02 108.635 ;
     RECT  92.82 108.04 93.425 108.635 ;
     RECT  20.04 107.62 26.22 108.66 ;
     RECT  54.42 108.06 57.42 108.66 ;
     RECT  20.04 108.46 24.78 108.705 ;
     RECT  56.82 108.46 57.42 108.705 ;
     RECT  99.06 107.665 104.04 108.705 ;
     RECT  130.92 106.825 135.66 108.78 ;
     RECT  149.46 105.915 154.92 108.78 ;
     RECT  170.1 108.09 174.92 108.78 ;
     RECT  190.92 106.405 195.66 108.78 ;
     RECT  88.5 108.435 91.025 109.125 ;
     RECT  92.815 108.435 93.425 109.125 ;
     RECT  88.5 108.925 89.58 109.475 ;
     RECT  126.52 65.665 126.92 109.475 ;
     RECT  135.055 108.58 135.66 109.475 ;
     RECT  224.945 109.375 226.575 109.865 ;
     RECT  88.495 109.275 89.58 109.965 ;
     RECT  124.975 109.275 126.92 109.965 ;
     RECT  135.055 109.275 135.665 109.965 ;
     RECT  20.04 108.505 24.04 110.04 ;
     RECT  40.04 104.305 45.42 110.04 ;
     RECT  60.04 108.085 64.62 110.04 ;
     RECT  80.04 105.165 84.04 110.04 ;
     RECT  100.04 108.505 104.04 110.04 ;
     RECT  170.1 108.58 170.7 110.78 ;
     RECT  170.1 110.58 171.66 111.18 ;
     RECT  228.145 113.155 229.775 113.645 ;
     RECT  251.32 113.57 251.72 114.195 ;
     RECT  251.315 113.995 251.725 114.485 ;
     RECT  179.7 106.405 180.3 114.98 ;
     RECT  187.38 107.665 187.98 114.98 ;
     RECT  195.06 108.58 195.66 114.98 ;
     RECT  178.74 114.78 180.3 115.38 ;
     RECT  186.42 114.78 187.98 115.38 ;
     RECT  149.46 108.58 150.06 115.4 ;
     RECT  157.14 105.565 157.74 115.4 ;
     RECT  91.475 115.255 91.885 115.745 ;
     RECT  121.24 86.4 122.6 115.815 ;
     RECT  124.98 109.765 126.92 115.815 ;
     RECT  132.66 108.58 133.26 115.815 ;
     RECT  155.7 115.2 157.74 115.815 ;
     RECT  171.06 110.98 171.66 115.815 ;
     RECT  178.74 115.18 179.34 115.815 ;
     RECT  194.1 114.78 195.66 115.815 ;
     RECT  199.96 107.985 202.38 115.815 ;
     RECT  219.16 84.045 219.56 115.875 ;
     RECT  121.24 115.615 126.92 116.015 ;
     RECT  130.36 115.615 133.26 116.015 ;
     RECT  171.06 115.615 179.34 116.015 ;
     RECT  194.1 115.615 197 116.015 ;
     RECT  199.96 115.615 204.68 116.015 ;
     RECT  124.98 115.815 126.92 116.02 ;
     RECT  132.66 115.815 133.26 116.02 ;
     RECT  140.34 107.25 140.94 116.02 ;
     RECT  148.02 115.2 150.06 116.02 ;
     RECT  154.84 115.615 157.74 116.02 ;
     RECT  163.38 106.825 163.98 116.02 ;
     RECT  171.06 115.815 174.44 116.02 ;
     RECT  178.74 115.815 179.34 116.02 ;
     RECT  186.42 115.18 187.02 116.02 ;
     RECT  194.1 115.815 194.7 116.02 ;
     RECT  199.96 115.815 202.38 116.02 ;
     RECT  209.46 107.985 210.92 116.02 ;
     RECT  172.595 115.82 174.44 116.165 ;
     RECT  218.195 115.675 219.56 116.165 ;
     RECT  224.945 116.935 226.575 117.425 ;
     RECT  59.315 118.195 59.725 118.685 ;
     RECT  59.32 118.485 59.725 118.76 ;
     RECT  250.36 115.255 250.76 118.815 ;
     RECT  105.875 118.615 106.285 119.105 ;
     RECT  179.795 118.615 180.205 119.105 ;
     RECT  189.395 118.615 189.805 119.105 ;
     RECT  250.355 118.615 250.765 119.105 ;
     RECT  44.82 109.84 45.42 119.135 ;
     RECT  101.94 109.84 102.54 119.135 ;
     RECT  59.32 118.56 61.74 119.18 ;
     RECT  64.02 109.84 64.62 119.18 ;
     RECT  121.24 115.815 123.08 119.235 ;
     RECT  88.98 109.765 89.58 119.49 ;
     RECT  91.48 115.545 91.88 119.49 ;
     RECT  101.935 118.935 103.985 119.495 ;
     RECT  105.875 118.905 106.28 119.495 ;
     RECT  121.235 119.035 123.08 119.525 ;
     RECT  166.835 119.035 167.245 119.525 ;
     RECT  59.32 118.98 64.62 119.58 ;
     RECT  44.815 118.935 46.385 119.625 ;
     RECT  101.935 119.295 106.28 119.625 ;
     RECT  31.38 107.81 31.98 119.655 ;
     RECT  13.72 26.085 14.12 119.685 ;
     RECT  16.98 105.145 17.58 119.685 ;
     RECT  59.32 119.38 63.66 119.69 ;
     RECT  88.98 119.29 91.88 119.69 ;
     RECT  103.38 119.425 106.28 119.695 ;
     RECT  13.72 119.485 17.58 119.885 ;
     RECT  16.98 119.685 17.58 119.89 ;
     RECT  31.38 119.455 33.325 119.89 ;
     RECT  45.78 119.425 46.38 119.89 ;
     RECT  60.18 119.49 63.66 119.89 ;
     RECT  74.58 108.085 75.18 119.89 ;
     RECT  88.98 119.49 89.58 119.89 ;
     RECT  103.38 119.495 104.84 119.89 ;
     RECT  31.48 119.69 33.325 119.945 ;
     RECT  130.36 115.815 130.76 120.075 ;
     RECT  130.355 119.875 130.765 120.365 ;
     RECT  103.535 119.69 104.84 120.74 ;
     RECT  45.97 119.69 46.38 120.785 ;
     RECT  118.355 120.295 118.765 120.785 ;
     RECT  126.52 115.82 126.92 120.915 ;
     RECT  74.77 119.69 75.18 121.205 ;
     RECT  126.515 120.715 126.925 121.205 ;
     RECT  228.145 120.715 229.775 121.205 ;
     RECT  224.945 124.495 226.575 124.985 ;
     RECT  13.72 119.685 15.08 125.955 ;
     RECT  148.12 115.82 148.52 125.955 ;
     RECT  204.28 115.815 204.68 125.955 ;
     RECT  13.715 125.755 15.08 126.245 ;
     RECT  56.435 125.755 56.845 126.245 ;
     RECT  148.115 125.755 148.525 126.245 ;
     RECT  202.355 125.755 204.68 126.245 ;
     RECT  140.44 115.82 140.84 128.475 ;
     RECT  166.84 119.325 167.24 128.475 ;
     RECT  196.6 115.815 197 128.475 ;
     RECT  199.96 115.82 200.36 128.475 ;
     RECT  138.145 128.275 140.84 128.765 ;
     RECT  166.84 128.275 169.775 128.765 ;
     RECT  196.6 128.275 200.36 128.765 ;
     RECT  228.145 128.275 229.775 128.765 ;
     RECT  6.04 49.185 6.92 129.735 ;
     RECT  14.68 126.045 15.08 129.735 ;
     RECT  56.44 126.045 56.84 129.735 ;
     RECT  66.04 129.11 66.44 129.735 ;
     RECT  121.72 119.325 123.08 129.735 ;
     RECT  126.52 121.005 126.92 129.735 ;
     RECT  5.075 129.535 6.92 130.025 ;
     RECT  14.675 129.535 15.085 130.025 ;
     RECT  56.435 129.535 56.845 130.025 ;
     RECT  66.035 129.535 66.445 130.025 ;
     RECT  78.995 129.535 79.405 130.025 ;
     RECT  43.48 129.53 43.88 130.155 ;
     RECT  72.28 129.53 72.68 130.155 ;
     RECT  34.355 129.955 34.765 130.445 ;
     RECT  41.08 129.955 45.8 130.445 ;
     RECT  49.72 129.955 51.085 130.445 ;
     RECT  65.555 129.955 65.965 130.445 ;
     RECT  72.275 129.955 72.685 130.445 ;
     RECT  5.08 129.825 6.92 130.575 ;
     RECT  34.36 130.245 34.765 130.575 ;
     RECT  38.2 129.95 38.6 130.575 ;
     RECT  38.195 130.375 38.605 130.865 ;
     RECT  56.44 129.825 56.84 130.865 ;
     RECT  79 129.825 79.4 130.865 ;
     RECT  34.36 130.375 35.24 130.995 ;
     RECT  44.945 130.245 45.8 130.995 ;
     RECT  67.955 129.955 68.36 130.995 ;
     RECT  34.36 130.795 35.725 131.285 ;
     RECT  67.955 130.795 68.365 131.285 ;
     RECT  5.08 130.375 6.925 131.415 ;
     RECT  38.2 130.665 38.605 131.415 ;
     RECT  41.08 130.245 42.92 131.415 ;
     RECT  65.555 130.245 65.96 131.415 ;
     RECT  64.595 131.215 65.96 131.705 ;
     RECT  140.44 128.565 140.84 131.835 ;
     RECT  140.435 131.635 140.845 132.125 ;
     RECT  44.945 130.795 45.805 132.255 ;
     RECT  163.48 115.82 163.88 132.255 ;
     RECT  166.84 128.565 167.24 132.255 ;
     RECT  196.6 128.565 197 132.255 ;
     RECT  14.945 132.055 16.575 132.545 ;
     RECT  44.945 132.055 46.575 132.545 ;
     RECT  74.945 132.055 76.575 132.545 ;
     RECT  104.945 132.055 106.575 132.545 ;
     RECT  134.945 132.055 136.575 132.545 ;
     RECT  163.48 132.055 167.24 132.545 ;
     RECT  194.945 132.055 197 132.545 ;
     RECT  224.945 132.055 226.575 132.545 ;
     RECT  209.56 115.82 210.92 133.095 ;
     RECT  49.72 130.245 51.08 133.385 ;
     RECT  64.6 131.505 65.96 133.385 ;
     RECT  209.555 132.895 210.92 133.385 ;
     RECT  241.715 132.895 242.125 133.385 ;
     RECT  31.48 119.745 31.88 133.515 ;
     RECT  34.36 131.085 34.76 133.515 ;
     RECT  31.48 133.315 34.76 133.93 ;
     RECT  46.36 132.345 46.575 133.935 ;
     RECT  46.36 133.735 46.76 133.98 ;
     RECT  46.36 133.78 47.72 134.225 ;
     RECT  5.08 131.215 7.4 134.355 ;
     RECT  31.48 133.73 35.72 134.355 ;
     RECT  38.2 131.215 42.92 134.355 ;
     RECT  49.72 133.185 50.125 134.355 ;
     RECT  5.08 134.155 7.405 134.645 ;
     RECT  31.48 134.155 35.725 134.645 ;
     RECT  38.195 134.155 42.92 134.645 ;
     RECT  47.32 134.025 47.72 134.645 ;
     RECT  49.715 134.155 50.125 134.645 ;
     RECT  64.6 133.185 65.485 134.645 ;
     RECT  166.84 132.345 167.24 136.035 ;
     RECT  196.6 132.345 197 136.035 ;
     RECT  199.96 128.565 200.36 136.035 ;
     RECT  18.145 135.835 19.775 136.325 ;
     RECT  48.145 135.835 49.775 136.325 ;
     RECT  78.145 135.835 79.775 136.325 ;
     RECT  108.145 135.835 109.775 136.325 ;
     RECT  138.145 135.835 139.775 136.325 ;
     RECT  166.84 135.835 169.775 136.325 ;
     RECT  196.6 135.835 200.36 136.325 ;
     RECT  228.145 135.835 229.775 136.325 ;
     RECT  64.6 134.445 65 136.8 ;
     RECT  174.04 115.965 174.44 136.875 ;
     RECT  64.6 136.6 65.48 137 ;
     RECT  174.04 136.675 175.405 137.165 ;
     RECT  40.12 134.445 42.92 137.29 ;
     RECT  246.995 136.675 247.405 137.59 ;
     RECT  250.355 136.675 250.765 137.71 ;
     RECT  40.12 137.09 44.84 137.715 ;
     RECT  40.115 137.515 44.845 138.005 ;
     RECT  166.84 136.125 167.245 138.135 ;
     RECT  245.56 137.51 245.965 138.135 ;
     RECT  245.555 137.935 245.965 138.425 ;
     RECT  248.435 137.51 250.765 138.425 ;
     RECT  248.92 138.225 250.765 138.975 ;
     RECT  248.92 138.775 251.72 139.265 ;
     RECT  163.48 132.345 163.88 139.815 ;
     RECT  166.835 137.935 167.245 139.815 ;
     RECT  196.6 136.125 197 139.815 ;
     RECT  14.945 139.615 16.575 140.105 ;
     RECT  44.945 139.615 46.575 140.105 ;
     RECT  74.945 139.615 76.575 140.105 ;
     RECT  104.945 139.615 106.575 140.105 ;
     RECT  134.945 139.615 136.575 140.105 ;
     RECT  163.48 139.615 167.245 140.105 ;
     RECT  194.945 139.615 197 140.105 ;
     RECT  224.945 139.615 226.575 140.105 ;
     RECT  41.08 137.805 42.92 140.235 ;
     RECT  121.72 129.535 126.92 140.235 ;
     RECT  166.84 139.905 167.245 140.235 ;
     RECT  186.52 115.82 186.92 140.235 ;
     RECT  210.52 133.185 210.92 140.235 ;
     RECT  41.08 140.035 42.925 140.525 ;
     RECT  46.835 140.035 47.245 140.525 ;
     RECT  121.72 140.035 126.925 140.525 ;
     RECT  186.035 140.035 186.92 140.525 ;
     RECT  210.515 140.035 210.925 140.525 ;
     RECT  241.72 133.185 242.12 140.65 ;
     RECT  174.04 136.965 175.4 140.655 ;
     RECT  179.8 118.905 180.2 140.655 ;
     RECT  241.72 140.45 242.6 140.655 ;
     RECT  245.075 140.035 245.485 140.655 ;
     RECT  248.92 139.065 251.24 140.655 ;
     RECT  174.04 140.455 175.405 140.945 ;
     RECT  179.795 140.455 180.205 140.945 ;
     RECT  41.08 140.325 41.485 141.075 ;
     RECT  74.2 140.45 74.605 141.075 ;
     RECT  241.72 140.455 245.485 141.075 ;
     RECT  248.435 140.455 251.24 141.075 ;
     RECT  41.075 140.875 41.485 141.365 ;
     RECT  65.08 136.8 65.48 141.365 ;
     RECT  74.195 140.875 74.605 141.365 ;
     RECT  166.84 140.035 168.205 141.365 ;
     RECT  241.72 140.875 251.24 141.365 ;
     RECT  241.72 141.165 244.04 141.375 ;
     RECT  246.52 141.165 251.24 141.795 ;
     RECT  247.48 141.595 251.24 142.755 ;
     RECT  46.84 140.325 47.24 143.595 ;
     RECT  18.145 143.395 19.775 143.885 ;
     RECT  46.84 143.395 49.775 143.885 ;
     RECT  78.145 143.395 79.775 143.885 ;
     RECT  108.145 143.395 109.775 143.885 ;
     RECT  202.36 126.045 204.68 144.015 ;
     RECT  202.36 143.815 204.685 144.305 ;
     RECT  237.875 143.815 238.285 144.305 ;
     RECT  5.08 134.445 6.92 147.375 ;
     RECT  46.84 143.685 47.24 147.375 ;
     RECT  247.48 142.555 251.72 147.375 ;
     RECT  5.08 147.175 6.925 147.665 ;
     RECT  14.945 147.175 16.575 147.665 ;
     RECT  44.945 147.175 47.24 147.665 ;
     RECT  74.945 147.175 76.575 147.665 ;
     RECT  104.945 147.175 106.575 147.665 ;
     RECT  247.48 147.175 251.725 147.665 ;
     RECT  237.88 144.105 238.28 149.52 ;
     RECT  241.72 141.175 242.12 149.52 ;
     RECT  237.495 149.32 238.28 149.72 ;
     RECT  241.72 149.32 242.505 149.72 ;
     RECT  218.2 115.965 219.56 149.895 ;
     RECT  218.2 149.695 219.565 150.185 ;
     RECT  46.84 147.465 47.24 151.155 ;
     RECT  196.6 139.905 197 151.155 ;
     RECT  124.6 140.325 125.48 151.3 ;
     RECT  154.84 115.82 155.24 151.3 ;
     RECT  163.48 139.905 163.88 151.3 ;
     RECT  166.84 141.165 168.2 151.3 ;
     RECT  174.04 140.745 175.4 151.3 ;
     RECT  179.8 140.745 180.2 151.3 ;
     RECT  186.04 140.325 186.92 151.3 ;
     RECT  189.4 118.905 189.8 151.3 ;
     RECT  194.29 149.695 194.7 151.3 ;
     RECT  199.96 136.125 200.36 151.3 ;
     RECT  202.36 144.105 202.76 151.3 ;
     RECT  218.2 149.985 218.7 151.3 ;
     RECT  237.495 149.52 237.9 151.3 ;
     RECT  242.1 149.52 242.505 151.3 ;
     RECT  163.48 151.1 168.2 151.305 ;
     RECT  170.1 151.1 170.7 151.305 ;
     RECT  230.195 150.955 230.605 151.305 ;
     RECT  232.5 151.1 233.1 151.305 ;
     RECT  18.145 150.955 19.775 151.445 ;
     RECT  46.84 150.955 49.775 151.445 ;
     RECT  78.145 150.955 79.775 151.445 ;
     RECT  108.145 150.955 109.775 151.445 ;
     RECT  196.595 150.955 197.005 151.445 ;
     RECT  230.195 151.105 233.1 151.445 ;
     RECT  154.84 151.1 158.7 151.45 ;
     RECT  124.6 151.1 132.3 151.495 ;
     RECT  141.3 151.1 141.9 151.495 ;
     RECT  146.1 151.1 146.7 151.495 ;
     RECT  150.9 151.1 151.5 151.495 ;
     RECT  153.875 151.25 158.7 151.495 ;
     RECT  160.5 151.1 161.1 151.495 ;
     RECT  208.5 151.1 209.1 151.495 ;
     RECT  213.3 151.1 213.9 151.495 ;
     RECT  222.9 151.1 223.5 151.495 ;
     RECT  227.7 151.1 228.3 151.495 ;
     RECT  163.48 151.105 170.7 151.505 ;
     RECT  198.9 151.1 200.36 151.505 ;
     RECT  202.36 151.1 204.3 151.505 ;
     RECT  230.2 151.245 233.1 151.505 ;
     RECT  184.5 151.1 186.92 151.575 ;
     RECT  143.8 151.295 146.7 151.695 ;
     RECT  208.5 151.295 213.9 151.695 ;
     RECT  222.9 151.295 228.3 151.695 ;
     RECT  13.715 151.375 14.125 151.865 ;
     RECT  184.5 151.375 186.925 151.865 ;
     RECT  222.9 151.495 225.805 151.865 ;
     RECT  163.48 151.305 165.9 151.92 ;
     RECT  136.5 151.1 137.1 151.94 ;
     RECT  139.96 151.295 141.9 151.94 ;
     RECT  124.6 151.295 133.16 152.34 ;
     RECT  136.5 151.74 141.9 152.34 ;
     RECT  153.875 151.295 161.1 152.34 ;
     RECT  174.04 151.1 180.3 152.34 ;
     RECT  118.36 120.585 118.76 152.415 ;
     RECT  150.04 151.295 151.5 152.415 ;
     RECT  163.48 151.72 164.94 152.415 ;
     RECT  118.36 152.215 119.725 152.705 ;
     RECT  150.035 152.215 151.5 152.705 ;
     RECT  163.475 152.215 164.94 152.705 ;
     RECT  208.5 151.495 211.405 152.705 ;
     RECT  174.04 152.14 174.445 152.835 ;
     RECT  158.1 152.14 161.1 153.125 ;
     RECT  174.035 152.635 174.445 153.125 ;
     RECT  222.9 151.665 224.365 153.125 ;
     RECT  153.875 152.14 155.24 153.545 ;
     RECT  198.9 151.305 199.5 153.575 ;
     RECT  203.7 151.305 204.3 153.575 ;
     RECT  237.3 151.1 237.9 154.04 ;
     RECT  198.895 153.375 199.505 154.065 ;
     RECT  203.215 153.375 204.3 154.065 ;
     RECT  237.3 153.84 239.82 154.44 ;
     RECT  154.835 153.345 155.24 154.515 ;
     RECT  154.835 154.315 155.245 154.805 ;
     RECT  208.5 152.505 209.965 154.805 ;
     RECT  222.9 152.925 223.505 154.835 ;
     RECT  5.08 147.465 5.48 154.935 ;
     RECT  13.72 151.665 14.12 154.935 ;
     RECT  46.84 151.245 47.24 154.935 ;
     RECT  5.08 154.735 7.535 155.225 ;
     RECT  13.72 154.735 16.575 155.225 ;
     RECT  44.945 154.735 47.24 155.225 ;
     RECT  74.945 154.735 76.575 155.225 ;
     RECT  104.945 154.735 106.575 155.225 ;
     RECT  213.3 151.495 213.9 155.255 ;
     RECT  222.895 154.635 223.505 155.325 ;
     RECT  213.295 155.055 213.905 155.745 ;
     RECT  237.775 154.24 239.82 155.745 ;
     RECT  194.1 151.1 194.7 156.14 ;
     RECT  193.14 155.94 194.7 156.54 ;
     RECT  227.7 151.495 228.3 156.935 ;
     RECT  237.78 155.545 239.82 156.935 ;
     RECT  242.1 151.1 242.7 156.935 ;
     RECT  218.1 151.1 218.7 157.355 ;
     RECT  232.5 151.305 233.1 157.355 ;
     RECT  203.22 153.865 204.3 157.4 ;
     RECT  227.695 156.735 228.305 157.425 ;
     RECT  231.055 157.155 233.1 157.845 ;
     RECT  129.78 152.14 133.16 157.875 ;
     RECT  143.8 151.495 144.2 158.295 ;
     RECT  129.78 157.675 133.165 158.54 ;
     RECT  137.94 152.14 141.9 158.54 ;
     RECT  158.1 152.925 158.7 158.54 ;
     RECT  177.78 152.14 180.3 158.54 ;
     RECT  193.14 156.34 193.74 158.54 ;
     RECT  218.095 157.155 218.705 158.54 ;
     RECT  231.06 157.645 233.1 158.54 ;
     RECT  237.78 156.735 242.7 158.54 ;
     RECT  113.075 158.095 113.485 158.585 ;
     RECT  143.795 158.095 144.205 158.585 ;
     RECT  46.84 155.025 47.24 158.715 ;
     RECT  18.145 158.515 19.775 159.005 ;
     RECT  46.84 158.515 49.775 159.005 ;
     RECT  78.145 158.515 79.775 159.005 ;
     RECT  108.145 158.515 109.775 159.005 ;
     RECT  150.9 152.505 151.5 159.03 ;
     RECT  153.8 158.34 158.7 159.03 ;
     RECT  208.5 154.605 209.1 159.03 ;
     RECT  203.22 157.2 204.78 159.035 ;
     RECT  170.1 151.305 170.7 159.435 ;
     RECT  213.8 158.34 218.705 159.45 ;
     RECT  184.5 151.665 185.1 159.455 ;
     RECT  208.02 158.83 209.1 159.455 ;
     RECT  203.22 158.835 205.745 159.525 ;
     RECT  168.66 159.235 170.7 159.72 ;
     RECT  168.18 159.52 170.7 159.87 ;
     RECT  189.3 151.1 189.9 159.87 ;
     RECT  203.22 159.325 205.74 159.87 ;
     RECT  208.015 159.255 209.1 159.87 ;
     RECT  211.38 159.25 211.98 159.87 ;
     RECT  164.34 152.505 164.94 159.875 ;
     RECT  167.7 159.67 170.7 159.875 ;
     RECT  208.015 159.67 211.98 159.875 ;
     RECT  213.8 159.25 219.66 159.875 ;
     RECT  231.06 158.34 242.7 159.9 ;
     RECT  150.9 158.83 158.7 159.945 ;
     RECT  208.015 159.675 211.985 159.945 ;
     RECT  231.06 159.7 241.26 159.945 ;
     RECT  160.5 152.925 161.1 160.295 ;
     RECT  188.82 159.67 189.9 160.295 ;
     RECT  193.14 158.34 197.8 160.295 ;
     RECT  201.3 159.67 205.74 160.295 ;
     RECT  213.8 159.675 219.665 160.295 ;
     RECT  227.22 160.095 227.82 160.34 ;
     RECT  160.5 160.095 162.065 160.71 ;
     RECT  164.34 159.675 170.7 160.71 ;
     RECT  173.8 158.34 180.3 160.71 ;
     RECT  129.78 158.34 141.9 160.715 ;
     RECT  146.1 151.495 146.7 160.715 ;
     RECT  164.34 160.51 180.3 160.715 ;
     RECT  182.575 159.255 185.1 160.715 ;
     RECT  187.38 160.095 189.9 160.715 ;
     RECT  193.14 160.095 205.74 160.715 ;
     RECT  192.175 160.515 205.74 160.785 ;
     RECT  226.74 160.14 227.82 160.785 ;
     RECT  5.08 155.025 5.48 160.815 ;
     RECT  5.08 160.615 6.44 161.06 ;
     RECT  153.8 159.745 158.7 161.13 ;
     RECT  160.5 160.51 162.54 161.13 ;
     RECT  208.5 159.745 211.985 161.13 ;
     RECT  213.8 160.095 223.5 161.13 ;
     RECT  153.8 160.93 162.54 161.135 ;
     RECT  182.575 160.515 190.38 161.135 ;
     RECT  192.175 160.585 200.465 161.135 ;
     RECT  150.9 159.745 151.98 161.16 ;
     RECT  129.78 160.515 143.345 161.205 ;
     RECT  151.38 160.96 151.98 161.205 ;
     RECT  164.34 160.515 180.78 161.205 ;
     RECT  146.1 160.515 147.18 161.555 ;
     RECT  153.8 160.935 162.545 161.555 ;
     RECT  164.34 161.005 179.34 161.555 ;
     RECT  182.575 160.935 200.465 161.555 ;
     RECT  202.74 160.585 205.74 161.555 ;
     RECT  231.06 159.745 240.78 161.555 ;
     RECT  208.5 160.93 223.5 161.625 ;
     RECT  142.74 161.005 143.345 161.635 ;
     RECT  5.905 160.86 6.44 161.655 ;
     RECT  5.905 161.455 7.4 161.7 ;
     RECT  202.74 161.355 205.745 162.045 ;
     RECT  230.095 161.355 240.78 162.045 ;
     RECT  5.905 161.5 7.88 162.12 ;
     RECT  208.5 161.425 211.025 162.395 ;
     RECT  181.14 161.355 200.465 162.465 ;
     RECT  118.36 152.505 119.72 162.495 ;
     RECT  121.72 140.325 122.12 162.495 ;
     RECT  5.905 161.92 8.36 162.785 ;
     RECT  133.14 161.005 140.365 162.785 ;
     RECT  146.1 161.355 148.14 162.86 ;
     RECT  208.495 162.195 211.025 162.885 ;
     RECT  130.26 161.005 131.34 163.7 ;
     RECT  133.14 162.585 139.98 163.7 ;
     RECT  143.22 162.66 148.14 163.7 ;
     RECT  153.8 161.355 179.34 163.7 ;
     RECT  181.14 162.265 199.98 163.7 ;
     RECT  209.46 162.685 211.025 163.7 ;
     RECT  212.815 161.425 223.5 163.7 ;
     RECT  230.1 161.845 240.78 164.075 ;
     RECT  226.74 160.585 227.34 164.34 ;
     RECT  230.1 163.875 241.26 164.34 ;
     RECT  143.22 163.5 148.62 164.495 ;
     RECT  150.42 164.29 151.02 164.495 ;
     RECT  153.8 163.5 199.98 164.495 ;
     RECT  202.74 161.845 204.78 164.495 ;
     RECT  209.46 163.5 223.5 164.495 ;
     RECT  143.22 164.295 200.94 164.54 ;
     RECT  202.74 164.295 205.26 164.54 ;
     RECT  143.22 164.34 205.74 164.985 ;
     RECT  226.74 164.14 241.26 164.985 ;
     RECT  201.78 164.785 205.74 165.36 ;
     RECT  143.22 164.785 199.98 165.405 ;
     RECT  202.255 165.16 205.74 165.405 ;
     RECT  226.74 164.785 228.785 165.405 ;
     RECT  143.22 165.205 149.1 167.01 ;
     RECT  151.855 165.205 199.98 167.015 ;
     RECT  142.26 166.81 149.1 167.43 ;
     RECT  151.855 166.815 199.985 167.43 ;
     RECT  141.78 167.23 149.1 167.855 ;
     RECT  151.38 167.23 199.985 167.855 ;
     RECT  202.74 165.205 205.74 167.855 ;
     RECT  209.46 164.295 224.46 167.855 ;
     RECT  226.74 165.205 228.78 167.855 ;
     RECT  141.775 167.655 149.58 167.9 ;
     RECT  151.375 167.655 205.74 167.9 ;
     RECT  232.02 164.785 241.26 168.275 ;
     RECT  141.775 167.7 205.74 168.345 ;
     RECT  130.26 163.5 139.98 168.695 ;
     RECT  141.775 168.145 150.06 168.695 ;
     RECT  226.74 167.655 229.265 168.695 ;
     RECT  231.055 168.075 241.26 168.695 ;
     RECT  226.74 168.495 241.26 169.115 ;
     RECT  151.86 168.145 205.74 169.56 ;
     RECT  151.86 169.36 167.82 169.605 ;
     RECT  169.615 169.36 205.74 169.605 ;
     RECT  226.74 168.915 241.265 169.605 ;
     RECT  172.5 169.405 183.18 169.61 ;
     RECT  185.46 169.405 205.74 169.955 ;
     RECT  207.535 167.655 224.46 169.955 ;
     RECT  226.74 169.405 240.785 169.955 ;
     RECT  169.615 169.405 170.705 170.025 ;
     RECT  172.975 169.41 183.18 170.025 ;
     RECT  207.535 169.755 224.465 170.025 ;
     RECT  31.48 134.445 31.88 170.2 ;
     RECT  46.84 158.805 47.24 170.2 ;
     RECT  13.72 155.025 14.12 170.395 ;
     RECT  17.94 170 18.54 170.395 ;
     RECT  61.14 170 64.62 170.395 ;
     RECT  75.54 170 76.14 170.395 ;
     RECT  104.34 170 104.94 170.395 ;
     RECT  151.86 169.405 166.86 170.4 ;
     RECT  31.48 170 32.94 170.405 ;
     RECT  169.615 169.825 170.7 170.445 ;
     RECT  185.46 169.755 205.745 170.445 ;
     RECT  226.255 169.755 240.785 170.445 ;
     RECT  13.72 170.195 18.54 170.595 ;
     RECT  75.54 170.195 78.44 170.595 ;
     RECT  104.34 170.195 107.24 170.595 ;
     RECT  187.86 170.245 190.38 170.82 ;
     RECT  130.26 168.495 150.06 171.215 ;
     RECT  151.86 170.2 159.18 171.215 ;
     RECT  130.26 171.015 159.18 171.285 ;
     RECT  163.855 170.2 166.86 171.285 ;
     RECT  192.175 170.245 205.745 171.285 ;
     RECT  207.54 169.825 224.465 171.285 ;
     RECT  226.26 170.245 240.785 171.285 ;
     RECT  60.28 170.195 64.62 171.38 ;
     RECT  164.34 171.085 166.86 171.63 ;
     RECT  213.8 171.085 224.465 171.705 ;
     RECT  60.28 171.18 60.685 171.735 ;
     RECT  113.08 158.385 113.48 171.735 ;
     RECT  60.275 171.535 60.685 172.025 ;
     RECT  113.08 171.535 113.965 172.025 ;
     RECT  164.34 171.43 167.34 172.055 ;
     RECT  169.62 170.245 170.7 172.055 ;
     RECT  172.98 169.825 183.18 172.055 ;
     RECT  164.34 171.855 167.345 172.545 ;
     RECT  169.62 171.855 183.18 172.545 ;
     RECT  193.8 171.085 205.745 172.545 ;
     RECT  226.26 171.085 238.86 172.545 ;
     RECT  13.72 170.395 16.04 172.575 ;
     RECT  106.84 170.395 107.24 172.575 ;
     RECT  13.235 172.375 16.045 172.865 ;
     RECT  106.835 172.375 107.245 172.865 ;
     RECT  164.34 172.345 166.38 172.965 ;
     RECT  164.34 172.765 165.9 173.385 ;
     RECT  149.46 171.085 159.18 173.76 ;
     RECT  207.54 171.085 211.98 174.15 ;
     RECT  213.8 171.505 217.8 174.15 ;
     RECT  219.54 171.505 224.465 174.155 ;
     RECT  226.26 172.345 229.26 174.155 ;
     RECT  188.815 170.62 190.38 174.2 ;
     RECT  207.54 173.95 217.8 174.2 ;
     RECT  219.54 173.955 229.26 174.2 ;
     RECT  161.935 173.535 162.545 174.225 ;
     RECT  207.54 174 229.26 174.57 ;
     RECT  231.54 172.345 238.86 174.57 ;
     RECT  171.06 172.345 183.18 174.575 ;
     RECT  193.8 172.345 204.78 174.575 ;
     RECT  171.055 174.375 183.18 174.62 ;
     RECT  185.46 170.245 186.06 174.62 ;
     RECT  17.94 170.395 18.54 174.715 ;
     RECT  32.34 170.205 32.94 174.715 ;
     RECT  130.26 171.085 147.66 174.99 ;
     RECT  149.46 173.56 150.54 174.99 ;
     RECT  152.34 173.56 159.18 174.99 ;
     RECT  187.86 174 190.38 174.995 ;
     RECT  193.8 174.375 205.74 174.995 ;
     RECT  171.055 174.42 186.06 175.065 ;
     RECT  207.54 174.37 238.86 175.065 ;
     RECT  17.935 174.515 18.545 175.205 ;
     RECT  30.895 174.515 32.94 175.205 ;
     RECT  187.86 174.795 205.74 175.405 ;
     RECT  207.54 174.865 211.985 175.405 ;
     RECT  152.34 174.79 160.14 175.415 ;
     RECT  161.94 174.025 162.545 175.415 ;
     RECT  164.34 173.185 165.42 175.415 ;
     RECT  172.98 174.865 186.06 175.415 ;
     RECT  187.86 175.205 211.985 175.415 ;
     RECT  152.34 175.215 160.145 175.905 ;
     RECT  172.98 175.215 211.985 175.905 ;
     RECT  213.8 174.865 238.86 175.905 ;
     RECT  191.7 175.705 209.58 175.915 ;
     RECT  130.26 174.79 150.54 176.255 ;
     RECT  152.34 175.705 159.665 176.255 ;
     RECT  192.66 175.715 209.58 176.325 ;
     RECT  78.04 170.395 78.44 176.355 ;
     RECT  30.9 175.005 32.94 176.44 ;
     RECT  78.035 176.155 78.445 176.645 ;
     RECT  130.26 176.055 159.665 176.745 ;
     RECT  213.8 175.705 224.46 176.745 ;
     RECT  226.255 175.705 229.26 176.745 ;
     RECT  168.655 176.475 169.265 177.165 ;
     RECT  226.74 176.545 228.785 177.165 ;
     RECT  231.055 175.705 238.86 177.165 ;
     RECT  130.26 176.545 140.46 177.515 ;
     RECT  161.94 175.215 165.42 177.56 ;
     RECT  172.98 175.705 189.42 177.93 ;
     RECT  143.22 176.545 159.66 177.96 ;
     RECT  172.5 177.73 189.42 178.355 ;
     RECT  192.66 176.125 204.3 178.77 ;
     RECT  206.1 176.125 209.58 178.77 ;
     RECT  143.7 177.76 159.66 178.775 ;
     RECT  161.94 177.36 166.38 178.775 ;
     RECT  168.655 176.965 169.26 178.775 ;
     RECT  213.8 176.545 221.58 178.775 ;
     RECT  64.02 171.18 64.62 178.84 ;
     RECT  104.34 170.395 104.94 178.84 ;
     RECT  211.375 178.575 221.58 178.845 ;
     RECT  130.255 177.315 140.46 179.19 ;
     RECT  192.66 178.57 209.58 179.19 ;
     RECT  226.74 176.965 228.78 179.195 ;
     RECT  129.78 178.99 140.46 179.615 ;
     RECT  172.495 178.155 189.42 179.615 ;
     RECT  191.22 178.99 209.58 179.615 ;
     RECT  211.375 178.645 220.625 179.615 ;
     RECT  226.74 178.995 228.785 179.615 ;
     RECT  231.06 176.965 238.86 179.615 ;
     RECT  143.7 178.575 169.26 179.66 ;
     RECT  171.06 179.415 189.42 179.66 ;
     RECT  191.215 179.415 220.625 179.685 ;
     RECT  226.74 179.415 238.86 179.685 ;
     RECT  75.54 170.395 76.14 179.755 ;
     RECT  89.94 170 90.54 179.755 ;
     RECT  100.04 178.64 104.94 179.755 ;
     RECT  129.775 179.415 140.46 180.105 ;
     RECT  143.7 179.46 189.42 180.105 ;
     RECT  191.215 179.485 220.62 180.105 ;
     RECT  226.74 179.485 227.82 180.105 ;
     RECT  229.615 179.485 238.86 180.105 ;
     RECT  75.54 179.555 76.62 180.2 ;
     RECT  89.94 179.555 91.02 180.2 ;
     RECT  90.42 180 91.02 180.245 ;
     RECT  100.04 179.555 105.42 180.245 ;
     RECT  143.7 179.905 166.38 180.455 ;
     RECT  168.175 179.905 189.42 180.455 ;
     RECT  168.175 180.255 189.9 180.48 ;
     RECT  130.255 179.905 140.46 180.525 ;
     RECT  191.7 179.905 220.62 180.53 ;
     RECT  180.18 180.28 189.9 180.535 ;
     RECT  60.04 178.64 64.62 180.595 ;
     RECT  180.18 180.335 181.74 180.9 ;
     RECT  76.02 180 76.62 181.015 ;
     RECT  80.04 178.64 84.04 181.015 ;
     RECT  142.74 180.255 166.38 181.365 ;
     RECT  30.9 176.24 33.42 181.435 ;
     RECT  28.5 181.235 33.42 181.48 ;
     RECT  76.02 180.815 77.58 181.505 ;
     RECT  79.375 180.815 84.04 181.505 ;
     RECT  91.375 180.815 91.985 181.505 ;
     RECT  131.22 180.325 140.46 181.71 ;
     RECT  142.74 181.165 160.145 181.71 ;
     RECT  59.22 180.395 64.62 181.855 ;
     RECT  35.7 181.655 36.3 181.9 ;
     RECT  58.74 181.655 65.58 181.9 ;
     RECT  26.58 181.28 33.42 181.925 ;
     RECT  91.38 181.305 91.98 181.93 ;
     RECT  161.94 181.165 166.38 182.115 ;
     RECT  168.175 180.28 177.8 182.115 ;
     RECT  35.7 181.7 37.74 182.345 ;
     RECT  131.22 181.51 160.145 182.555 ;
     RECT  130.735 182.355 160.145 182.625 ;
     RECT  212.815 180.33 220.62 182.975 ;
     RECT  223.86 176.545 224.46 182.975 ;
     RECT  183.54 180.335 189.9 183.02 ;
     RECT  191.7 180.33 210.54 183.02 ;
     RECT  223.86 182.775 225.105 183.02 ;
     RECT  227.22 179.905 227.82 183.02 ;
     RECT  130.735 182.425 160.14 183.045 ;
     RECT  212.34 182.775 220.62 183.045 ;
     RECT  223.86 182.82 227.82 183.42 ;
     RECT  130.74 182.845 160.14 183.465 ;
     RECT  183.54 182.82 210.54 183.465 ;
     RECT  223.86 183.22 225.105 183.465 ;
     RECT  161.94 181.915 177.8 183.475 ;
     RECT  26.58 181.725 27.18 183.535 ;
     RECT  185.935 183.265 210.54 183.84 ;
     RECT  46.74 170 47.34 183.955 ;
     RECT  143.22 183.265 160.14 184.095 ;
     RECT  191.22 183.64 204.3 184.26 ;
     RECT  206.58 183.64 210.54 184.26 ;
     RECT  191.7 184.06 204.3 184.305 ;
     RECT  46.74 183.755 47.82 184.375 ;
     RECT  26.095 183.335 27.18 184.45 ;
     RECT  37.14 182.145 37.74 184.795 ;
     RECT  46.26 184.175 47.82 184.84 ;
     RECT  50.58 184.595 51.18 184.84 ;
     RECT  185.935 183.64 186.545 185.145 ;
     RECT  193.8 184.105 204.3 185.145 ;
     RECT  30.42 181.725 33.42 185.285 ;
     RECT  35.22 184.595 37.74 185.285 ;
     RECT  46.26 184.64 51.18 185.285 ;
     RECT  130.74 183.265 141.425 185.565 ;
     RECT  20.04 178.64 24.04 185.635 ;
     RECT  40.04 178.64 44.04 185.635 ;
     RECT  46.26 185.085 49.26 185.635 ;
     RECT  53.46 185.015 55.98 185.635 ;
     RECT  57.78 181.7 67.02 185.635 ;
     RECT  161.94 183.275 170.225 185.96 ;
     RECT  172.015 183.275 177.8 185.96 ;
     RECT  53.46 185.435 67.98 186.055 ;
     RECT  143.7 183.895 160.14 186.36 ;
     RECT  161.94 185.76 177.8 186.36 ;
     RECT  183.54 183.265 184.14 186.38 ;
     RECT  185.935 184.945 186.54 186.38 ;
     RECT  53.455 185.855 67.98 186.475 ;
     RECT  53.455 186.275 69.905 186.545 ;
     RECT  206.58 184.06 208.14 186.75 ;
     RECT  209.94 184.06 210.54 186.75 ;
     RECT  55.38 186.345 69.905 186.965 ;
     RECT  180.66 180.7 181.74 187.175 ;
     RECT  183.54 186.18 186.54 187.175 ;
     RECT  193.8 184.945 197.8 187.175 ;
     RECT  201.3 184.945 204.3 187.175 ;
     RECT  212.34 182.845 217.8 187.175 ;
     RECT  223.86 183.265 224.94 187.175 ;
     RECT  40.04 185.435 49.26 187.315 ;
     RECT  100.04 180.045 104.04 187.315 ;
     RECT  105.78 180.815 106.38 187.315 ;
     RECT  212.335 186.975 217.8 187.585 ;
     RECT  220.02 182.845 220.62 187.585 ;
     RECT  206.58 186.55 210.54 187.59 ;
     RECT  212.335 187.385 220.62 187.59 ;
     RECT  130.74 185.365 139.98 187.595 ;
     RECT  147.06 186.16 160.14 187.595 ;
     RECT  206.58 187.39 220.62 187.665 ;
     RECT  222.895 186.975 224.94 187.665 ;
     RECT  20.04 185.435 24.78 187.735 ;
     RECT  26.58 184.25 27.18 187.735 ;
     RECT  30.42 185.085 31.02 187.735 ;
     RECT  39.055 187.115 49.26 187.805 ;
     RECT  76.02 181.305 76.62 187.805 ;
     RECT  105.775 187.115 106.385 187.805 ;
     RECT  206.58 187.465 208.14 188.015 ;
     RECT  193.8 186.975 204.3 188.04 ;
     RECT  130.74 187.395 139.985 188.085 ;
     RECT  147.06 187.395 160.145 188.085 ;
     RECT  193.8 187.84 200.94 188.085 ;
     RECT  20.04 187.535 27.18 188.155 ;
     RECT  30.415 187.535 31.025 188.155 ;
     RECT  32.82 185.085 33.42 188.155 ;
     RECT  39.06 187.605 49.26 188.155 ;
     RECT  69.3 186.765 69.905 188.155 ;
     RECT  20.04 187.955 28.62 188.2 ;
     RECT  30.415 187.955 33.42 188.2 ;
     RECT  20.04 188 33.42 188.225 ;
     RECT  39.06 187.955 51.185 188.23 ;
     RECT  98.095 187.115 104.04 188.23 ;
     RECT  180.66 186.975 186.54 188.435 ;
     RECT  206.095 187.815 208.14 188.505 ;
     RECT  20.04 188.025 29.1 188.645 ;
     RECT  32.335 188.025 33.42 188.645 ;
     RECT  40.04 188.03 51.185 188.645 ;
     RECT  26.1 188.445 29.1 188.65 ;
     RECT  40.04 188.445 51.18 188.65 ;
     RECT  193.8 187.885 199.5 188.855 ;
     RECT  227.215 188.235 227.825 188.925 ;
     RECT  35.22 185.085 35.82 188.995 ;
     RECT  55.38 186.765 66.545 189.065 ;
     RECT  97.135 188.375 97.745 189.065 ;
     RECT  32.34 188.445 33.42 189.07 ;
     RECT  46.26 188.45 51.18 189.07 ;
     RECT  143.7 186.16 145.26 189.27 ;
     RECT  147.06 187.885 159.18 189.27 ;
     RECT  193.135 188.655 199.5 189.275 ;
     RECT  161.94 186.16 169.74 189.32 ;
     RECT  130.74 187.885 139.505 189.345 ;
     RECT  202.735 187.84 204.3 189.345 ;
     RECT  35.215 188.795 35.825 189.485 ;
     RECT  97.14 188.865 97.74 189.49 ;
     RECT  192.655 189.075 199.5 189.69 ;
     RECT  209.94 187.465 211.025 189.69 ;
     RECT  212.815 187.465 220.62 189.69 ;
     RECT  143.7 189.07 159.18 189.695 ;
     RECT  161.46 189.12 169.74 189.695 ;
     RECT  171.535 186.16 177.8 189.695 ;
     RECT  180.655 188.235 186.545 189.695 ;
     RECT  222.9 187.465 224.94 189.72 ;
     RECT  69.3 187.955 70.86 189.835 ;
     RECT  161.46 189.495 186.545 189.96 ;
     RECT  143.695 189.495 159.18 190.11 ;
     RECT  192.18 189.49 199.5 190.11 ;
     RECT  161.46 189.76 187.98 190.115 ;
     RECT  192.18 189.91 199.98 190.115 ;
     RECT  143.695 189.91 159.66 190.16 ;
     RECT  161.46 189.915 187.985 190.16 ;
     RECT  143.695 189.96 187.985 190.185 ;
     RECT  69.3 189.635 71.825 190.325 ;
     RECT  130.74 189.145 139.5 190.535 ;
     RECT  192.175 189.915 199.98 190.535 ;
     RECT  206.1 188.305 208.14 190.535 ;
     RECT  209.94 189.49 220.62 190.535 ;
     RECT  130.255 190.335 139.5 191.025 ;
     RECT  144.175 189.985 179.82 191.025 ;
     RECT  189.775 190.335 199.985 191.025 ;
     RECT  206.1 190.335 221.1 191.025 ;
     RECT  229.62 179.905 238.86 191.025 ;
     RECT  227.22 188.725 227.82 191.37 ;
     RECT  229.62 190.825 230.22 191.37 ;
     RECT  55.38 188.865 66.06 191.515 ;
     RECT  69.3 190.125 71.82 191.515 ;
     RECT  73.62 183.755 74.22 191.515 ;
     RECT  79.38 181.305 84.04 191.585 ;
     RECT  181.62 189.985 187.985 191.795 ;
     RECT  189.775 190.825 199.5 191.795 ;
     RECT  212.82 190.825 221.1 191.795 ;
     RECT  222.9 189.52 224.46 191.795 ;
     RECT  144.175 190.825 170.225 191.865 ;
     RECT  172.015 190.825 177.8 191.865 ;
     RECT  212.82 191.595 225.42 191.865 ;
     RECT  40.04 188.45 44.04 191.935 ;
     RECT  46.26 188.87 49.26 191.935 ;
     RECT  213.3 191.665 225.42 192.285 ;
     RECT  227.22 191.17 230.22 192.285 ;
     RECT  26.58 188.45 29.1 192.355 ;
     RECT  32.82 188.87 33.42 192.355 ;
     RECT  40.04 191.735 49.26 192.355 ;
     RECT  55.38 191.315 71.82 192.355 ;
     RECT  222.895 192.085 225.42 192.635 ;
     RECT  227.22 192.085 227.82 192.635 ;
     RECT  144.175 191.665 169.26 192.68 ;
     RECT  32.34 192.155 33.42 192.8 ;
     RECT  26.1 192.155 29.1 192.845 ;
     RECT  32.34 192.6 32.94 192.845 ;
     RECT  40.04 192.155 49.745 192.845 ;
     RECT  53.455 192.155 71.82 192.845 ;
     RECT  73.615 191.315 74.225 192.845 ;
     RECT  40.04 192.645 46.38 193.195 ;
     RECT  28.02 192.645 29.1 193.27 ;
     RECT  53.46 192.645 54.06 193.27 ;
     RECT  73.62 192.645 74.22 193.27 ;
     RECT  232.02 190.825 238.86 193.475 ;
     RECT  142.74 192.48 169.26 193.895 ;
     RECT  181.62 191.595 199.5 193.965 ;
     RECT  130.26 190.825 139.5 194.31 ;
     RECT  213.3 192.085 221.1 194.73 ;
     RECT  222.895 192.435 227.82 194.73 ;
     RECT  130.26 194.11 139.98 194.735 ;
     RECT  142.26 193.695 169.26 194.735 ;
     RECT  203.7 189.145 204.3 194.735 ;
     RECT  39.06 192.995 46.38 194.875 ;
     RECT  48.66 192.645 49.74 194.875 ;
     RECT  56.34 192.645 66.54 194.875 ;
     RECT  35.215 194.675 35.825 194.92 ;
     RECT  142.255 194.535 169.26 195.155 ;
     RECT  172.02 191.665 177.8 195.155 ;
     RECT  191.215 193.765 199.5 195.155 ;
     RECT  202.74 194.535 204.3 195.155 ;
     RECT  232.02 193.275 238.865 195.155 ;
     RECT  130.26 194.535 139.985 195.225 ;
     RECT  142.255 194.955 169.265 195.225 ;
     RECT  181.62 193.765 189.425 195.225 ;
     RECT  213.3 194.53 227.82 195.225 ;
     RECT  34.74 194.72 35.825 195.295 ;
     RECT  38.1 194.675 46.38 195.295 ;
     RECT  48.66 194.675 51.185 195.365 ;
     RECT  56.335 194.675 66.54 195.365 ;
     RECT  130.26 195.025 139.5 195.575 ;
     RECT  213.3 195.025 225.9 195.575 ;
     RECT  185.46 195.025 189.425 195.645 ;
     RECT  191.215 194.955 204.3 195.645 ;
     RECT  212.82 195.375 225.9 195.645 ;
     RECT  232.02 194.955 239.345 195.645 ;
     RECT  185.46 195.445 189.42 195.65 ;
     RECT  34.74 195.095 46.38 195.715 ;
     RECT  130.255 195.375 139.5 196.065 ;
     RECT  70.26 192.645 71.82 196.125 ;
     RECT  28.5 193.07 29.1 196.135 ;
     RECT  56.815 195.165 66.54 196.135 ;
     RECT  69.3 195.925 71.82 196.135 ;
     RECT  56.815 195.935 67.02 196.18 ;
     RECT  69.3 195.935 74.7 196.18 ;
     RECT  232.02 195.445 239.34 196.415 ;
     RECT  28.495 195.935 29.105 196.625 ;
     RECT  48.66 195.165 51.18 196.625 ;
     RECT  56.815 195.98 74.7 196.625 ;
     RECT  34.26 195.515 46.38 196.63 ;
     RECT  229.62 192.085 230.22 196.83 ;
     RECT  232.015 196.215 239.34 196.83 ;
     RECT  56.82 196.425 74.7 196.975 ;
     RECT  34.26 196.43 44.04 197.045 ;
     RECT  48.66 196.425 50.225 197.045 ;
     RECT  56.82 196.775 74.705 197.045 ;
     RECT  56.82 196.845 67.985 197.055 ;
     RECT  142.26 195.025 163.5 197.255 ;
     RECT  165.3 195.025 169.265 197.255 ;
     RECT  172.015 194.955 177.8 197.255 ;
     RECT  181.62 195.025 182.22 197.255 ;
     RECT  57.3 196.855 67.985 197.465 ;
     RECT  70.26 196.845 74.705 197.465 ;
     RECT  48.66 196.845 50.22 197.47 ;
     RECT  142.26 197.055 177.8 197.7 ;
     RECT  206.1 190.825 211.02 197.7 ;
     RECT  142.26 197.5 163.98 197.745 ;
     RECT  181.615 197.055 182.225 197.745 ;
     RECT  191.695 195.445 204.3 197.745 ;
     RECT  209.46 197.5 211.02 197.745 ;
     RECT  57.3 197.265 67.98 197.89 ;
     RECT  229.62 196.63 239.34 198.095 ;
     RECT  212.82 195.445 221.1 198.14 ;
     RECT  222.9 195.445 225.9 198.14 ;
     RECT  229.62 197.895 239.82 198.14 ;
     RECT  142.26 197.545 163.025 198.165 ;
     RECT  45.775 196.43 46.38 198.235 ;
     RECT  212.82 197.94 225.9 198.53 ;
     RECT  165.78 197.5 177.8 198.54 ;
     RECT  142.26 197.965 147.66 198.585 ;
     RECT  149.455 197.965 163.025 198.585 ;
     RECT  212.82 198.33 223.505 198.585 ;
     RECT  48.66 197.27 49.745 198.725 ;
     RECT  149.455 198.385 151.5 199.005 ;
     RECT  153.3 198.385 159.185 199.005 ;
     RECT  171.535 198.34 177.8 199.005 ;
     RECT  45.775 198.035 46.385 199.075 ;
     RECT  48.66 198.525 49.74 199.075 ;
     RECT  38.1 196.845 44.04 199.12 ;
     RECT  45.775 198.875 49.74 199.12 ;
     RECT  57.3 197.69 66.54 199.145 ;
     RECT  34.26 196.845 34.86 199.96 ;
     RECT  38.1 198.92 49.74 199.985 ;
     RECT  65.94 198.945 66.54 199.985 ;
     RECT  34.26 199.76 36.06 200.095 ;
     RECT  38.1 199.785 45.42 200.095 ;
     RECT  34.26 199.895 45.42 200.36 ;
     RECT  185.94 195.45 189.42 200.61 ;
     RECT  35.46 200.16 45.42 200.78 ;
     RECT  146.1 198.385 147.66 201.03 ;
     RECT  184.98 200.41 189.42 201.03 ;
     RECT  184.98 200.83 189.9 201.035 ;
     RECT  191.7 197.545 204.3 201.035 ;
     RECT  172.98 198.805 177.8 201.45 ;
     RECT  130.26 195.865 139.5 201.455 ;
     RECT  145.62 200.83 147.66 201.455 ;
     RECT  153.3 198.805 159.18 201.455 ;
     RECT  181.14 200.88 182.7 201.455 ;
     RECT  184.975 200.835 204.3 201.455 ;
     RECT  213.3 198.385 223.505 201.455 ;
     RECT  225.3 198.33 225.9 201.455 ;
     RECT  229.62 197.94 240.3 201.455 ;
     RECT  150.42 198.805 151.5 201.5 ;
     RECT  153.295 201.255 159.18 201.5 ;
     RECT  181.14 201.255 204.3 201.5 ;
     RECT  70.26 197.265 73.26 201.64 ;
     RECT  165.78 198.34 169.74 201.87 ;
     RECT  172.98 201.25 178.86 201.87 ;
     RECT  180.66 201.3 204.3 201.87 ;
     RECT  150.42 201.3 159.18 201.875 ;
     RECT  213.3 201.255 225.9 201.875 ;
     RECT  228.175 201.255 240.3 201.875 ;
     RECT  149.455 201.675 159.18 201.92 ;
     RECT  130.26 201.255 139.985 201.945 ;
     RECT  142.26 198.385 143.34 202.295 ;
     RECT  145.615 201.255 147.66 202.295 ;
     RECT  149.445 201.72 159.18 202.295 ;
     RECT  206.1 197.5 206.7 202.295 ;
     RECT  165.78 201.67 204.3 202.365 ;
     RECT  35.7 200.58 45.42 202.435 ;
     RECT  206.1 202.095 207.66 202.74 ;
     RECT  180.175 202.165 204.3 202.785 ;
     RECT  207.06 202.54 207.66 202.785 ;
     RECT  213.3 201.675 240.3 202.785 ;
     RECT  223.38 202.585 231.18 202.795 ;
     RECT  213.3 202.585 221.1 203.135 ;
     RECT  212.82 202.935 221.1 203.21 ;
     RECT  35.7 202.235 46.86 203.275 ;
     RECT  165.78 202.165 178.38 203.58 ;
     RECT  70.26 201.44 73.5 203.585 ;
     RECT  34.015 203.075 46.86 203.605 ;
     RECT  181.14 202.585 201.9 203.625 ;
     RECT  32.58 203.405 46.86 203.695 ;
     RECT  72.9 203.385 73.5 204.115 ;
     RECT  32.575 203.495 46.865 204.185 ;
     RECT  72.9 203.915 74.7 204.605 ;
     RECT  130.26 201.745 139.98 204.815 ;
     RECT  142.26 202.095 159.18 204.815 ;
     RECT  203.7 202.585 204.3 204.815 ;
     RECT  228.18 202.595 231.18 204.815 ;
     RECT  232.98 202.585 240.3 204.815 ;
     RECT  203.7 204.615 205.265 204.86 ;
     RECT  219.535 203.01 221.1 205.305 ;
     RECT  228.18 204.615 240.3 205.305 ;
     RECT  130.26 204.615 140.465 205.655 ;
     RECT  142.26 204.615 159.665 205.655 ;
     RECT  161.46 198.385 163.02 205.655 ;
     RECT  165.78 203.38 168.78 205.655 ;
     RECT  170.58 203.38 178.38 205.655 ;
     RECT  181.14 203.425 182.22 205.655 ;
     RECT  203.7 204.66 208.14 205.655 ;
     RECT  209.94 197.545 211.02 205.655 ;
     RECT  219.54 205.105 221.1 205.655 ;
     RECT  223.38 202.595 225.9 205.655 ;
     RECT  228.18 205.105 228.78 205.655 ;
     RECT  181.14 205.455 183.18 205.7 ;
     RECT  184.98 203.425 201.9 205.7 ;
     RECT  181.14 205.5 201.9 206.145 ;
     RECT  32.575 203.985 44.945 206.285 ;
     RECT  181.14 205.945 185.1 206.52 ;
     RECT  181.14 206.32 184.14 206.565 ;
     RECT  67.38 203.915 67.98 206.635 ;
     RECT  70.26 203.385 70.86 206.635 ;
     RECT  72.9 204.405 74.22 206.635 ;
     RECT  80.04 191.385 84.04 206.635 ;
     RECT  129.78 205.455 163.02 206.94 ;
     RECT  181.14 206.365 183.18 206.94 ;
     RECT  186.9 205.945 201.9 206.94 ;
     RECT  188.82 206.74 201.9 206.985 ;
     RECT  66.415 206.435 84.04 207.125 ;
     RECT  129.78 206.74 146.22 207.335 ;
     RECT  230.58 205.105 231.66 207.335 ;
     RECT  32.58 206.085 44.945 207.475 ;
     RECT  48.66 199.785 49.26 207.475 ;
     RECT  51.54 203.915 52.14 207.475 ;
     RECT  66.42 206.925 84.04 207.55 ;
     RECT  32.58 207.275 49.26 207.635 ;
     RECT  165.78 205.455 178.38 207.755 ;
     RECT  203.7 205.455 211.02 207.755 ;
     RECT  212.82 203.01 217.8 207.755 ;
     RECT  148.5 206.74 163.02 207.8 ;
     RECT  165.78 207.555 178.385 207.8 ;
     RECT  129.775 207.135 146.22 207.825 ;
     RECT  219.54 205.455 228.78 207.825 ;
     RECT  230.575 207.135 231.66 207.825 ;
     RECT  34.02 207.435 49.26 207.92 ;
     RECT  51.535 207.275 53.1 207.965 ;
     RECT  67.38 207.35 84.04 207.965 ;
     RECT  231.06 207.625 231.66 208.17 ;
     RECT  233.8 205.105 237.8 208.17 ;
     RECT  130.26 207.625 146.22 208.2 ;
     RECT  148.5 207.6 178.385 208.2 ;
     RECT  167.695 208 178.385 208.245 ;
     RECT  29.46 206.435 30.06 208.315 ;
     RECT  203.7 207.555 217.8 208.595 ;
     RECT  219.54 207.625 221.585 208.595 ;
     RECT  167.695 208.045 177.8 208.665 ;
     RECT  27.535 208.115 30.06 208.735 ;
     RECT  27.535 208.535 30.065 208.805 ;
     RECT  148.5 208 165.42 209.085 ;
     RECT  203.7 208.395 221.585 209.085 ;
     RECT  27.54 208.605 30.065 209.225 ;
     RECT  27.54 209.025 28.14 209.23 ;
     RECT  67.38 207.765 76.38 209.575 ;
     RECT  148.5 208.885 149.105 209.855 ;
     RECT  223.38 207.625 228.78 209.855 ;
     RECT  231.06 207.97 237.8 209.855 ;
     RECT  239.7 205.105 240.3 209.855 ;
     RECT  186.895 209.655 187.505 209.9 ;
     RECT  189.3 206.785 201.9 209.9 ;
     RECT  186.895 209.7 201.9 209.925 ;
     RECT  34.02 207.72 48.78 209.995 ;
     RECT  66.655 209.375 76.38 210.065 ;
     RECT  203.7 208.885 221.1 210.3 ;
     RECT  148.495 209.655 149.105 210.345 ;
     RECT  186.895 209.725 190.385 210.345 ;
     RECT  192.18 209.725 201.9 210.345 ;
     RECT  239.695 209.655 240.305 210.345 ;
     RECT  52.5 207.765 53.1 210.415 ;
     RECT  32.575 209.795 48.78 210.485 ;
     RECT  52.495 210.215 53.105 210.905 ;
     RECT  46.26 210.285 48.78 210.91 ;
     RECT  150.9 208.885 165.42 211.115 ;
     RECT  167.7 208.465 177.8 211.115 ;
     RECT  186.895 210.145 189.42 211.115 ;
     RECT  32.58 210.285 44.04 211.145 ;
     RECT  66.66 209.865 76.38 211.145 ;
     RECT  34.02 210.945 36.06 211.16 ;
     RECT  150.9 210.915 177.8 211.535 ;
     RECT  66.66 210.945 75.18 211.7 ;
     RECT  182.58 206.74 183.18 211.95 ;
     RECT  150.9 211.335 178.385 211.955 ;
     RECT  181.62 211.75 183.18 211.955 ;
     RECT  150.9 211.755 183.18 212.375 ;
     RECT  203.7 210.1 220.62 212.375 ;
     RECT  185.935 210.915 189.42 212.42 ;
     RECT  192.18 210.145 199.5 212.42 ;
     RECT  150.895 212.175 183.18 212.865 ;
     RECT  247.48 147.465 251.24 212.895 ;
     RECT  247.48 212.695 251.245 213.185 ;
     RECT  124.6 152.14 125.96 213.215 ;
     RECT  185.935 212.22 199.5 213.215 ;
     RECT  201.3 210.145 201.9 213.215 ;
     RECT  203.7 212.175 221.585 213.215 ;
     RECT  223.38 209.655 237.8 213.215 ;
     RECT  172.015 212.665 183.18 213.26 ;
     RECT  185.46 213.015 199.5 213.26 ;
     RECT  124.6 213.015 127.505 213.705 ;
     RECT  151.38 212.665 169.74 213.705 ;
     RECT  201.3 213.015 237.8 213.705 ;
     RECT  201.3 213.505 211.5 213.715 ;
     RECT  151.38 213.505 168.785 214.545 ;
     RECT  172.015 213.06 199.5 214.545 ;
     RECT  213.3 213.505 237.8 214.545 ;
     RECT  38.1 210.945 44.04 214.705 ;
     RECT  66.66 211.5 72.3 215.035 ;
     RECT  74.58 211.5 75.18 215.035 ;
     RECT  66.66 214.835 75.18 215.195 ;
     RECT  48.18 210.71 48.78 215.455 ;
     RECT  68.095 214.995 75.18 215.525 ;
     RECT  201.3 213.515 211.02 215.73 ;
     RECT  213.3 214.345 230.22 215.73 ;
     RECT  201.3 215.53 230.22 215.76 ;
     RECT  52.5 214.835 53.1 215.875 ;
     RECT  68.1 215.325 75.18 215.875 ;
     RECT  46.255 215.255 48.78 215.945 ;
     RECT  68.1 215.675 76.145 215.95 ;
     RECT  37.38 214.505 44.04 216.34 ;
     RECT  52.495 215.675 53.105 216.365 ;
     RECT  70.26 215.75 76.145 216.365 ;
     RECT  46.26 215.745 48.78 216.37 ;
     RECT  172.02 214.345 178.86 216.575 ;
     RECT  180.66 214.345 185.58 216.575 ;
     RECT  151.38 214.345 168.3 216.645 ;
     RECT  207.54 215.56 230.22 216.645 ;
     RECT  36.66 216.14 44.04 216.74 ;
     RECT  70.26 216.165 76.14 216.79 ;
     RECT  172.02 216.375 185.58 216.99 ;
     RECT  187.86 214.345 199.5 216.99 ;
     RECT  201.3 215.56 205.74 216.99 ;
     RECT  172.02 216.79 186.06 217.065 ;
     RECT  151.38 216.445 162.06 217.415 ;
     RECT  184.98 216.865 186.06 217.415 ;
     RECT  172.02 216.865 182.705 217.46 ;
     RECT  187.86 216.79 205.74 217.485 ;
     RECT  184.98 217.215 186.065 217.845 ;
     RECT  187.86 217.285 200.465 217.845 ;
     RECT  163.86 216.445 168.3 217.905 ;
     RECT  184.98 217.645 200.465 217.905 ;
     RECT  202.255 217.285 205.74 217.905 ;
     RECT  211.38 216.445 230.22 217.905 ;
     RECT  70.26 216.59 74.22 218 ;
     RECT  130.26 208 145.74 218.255 ;
     RECT  48.18 216.17 48.78 218.395 ;
     RECT  211.38 217.705 225.9 218.7 ;
     RECT  227.7 217.705 230.22 218.7 ;
     RECT  70.26 217.8 73.5 218.72 ;
     RECT  171.54 217.26 182.705 218.745 ;
     RECT  184.98 217.705 199.5 218.745 ;
     RECT  36.66 216.54 37.26 218.885 ;
     RECT  52.5 216.165 53.1 218.885 ;
     RECT  164.815 217.705 168.3 219.56 ;
     RECT  46.26 218.195 48.78 219.655 ;
     RECT  150.9 217.215 162.06 219.935 ;
     RECT  164.815 219.36 169.26 219.935 ;
     RECT  30.415 219.455 31.025 220.145 ;
     RECT  37.615 219.455 38.225 220.145 ;
     RECT  46.255 219.455 48.78 220.145 ;
     RECT  50.575 219.455 51.185 220.145 ;
     RECT  130.26 218.055 145.745 220.35 ;
     RECT  130.26 220.15 146.7 220.355 ;
     RECT  184.98 218.545 191.34 220.38 ;
     RECT  207.54 216.445 208.62 220.4 ;
     RECT  211.38 218.5 224.46 220.4 ;
     RECT  171.54 218.545 181.745 220.425 ;
     RECT  185.94 220.18 191.34 220.425 ;
     RECT  37.62 219.945 38.22 220.57 ;
     RECT  130.26 220.155 148.145 220.765 ;
     RECT  149.94 219.735 169.26 220.765 ;
     RECT  130.26 220.565 169.26 220.775 ;
     RECT  171.54 220.225 181.74 220.775 ;
     RECT  193.14 218.545 199.5 220.775 ;
     RECT  233.8 214.345 237.8 220.775 ;
     RECT  186.9 220.225 191.34 220.78 ;
     RECT  193.135 220.575 199.5 220.78 ;
     RECT  202.26 217.705 202.86 221.195 ;
     RECT  204.66 217.705 205.74 221.195 ;
     RECT  130.26 220.575 181.74 221.265 ;
     RECT  232.975 220.575 237.8 221.265 ;
     RECT  146.58 221.065 181.74 221.685 ;
     RECT  146.58 221.485 148.14 222.06 ;
     RECT  147.54 221.86 148.14 222.105 ;
     RECT  207.54 220.2 224.46 222.525 ;
     RECT  149.94 221.485 181.74 222.53 ;
     RECT  230.095 222.255 230.705 222.945 ;
     RECT  207.54 222.325 217.8 222.95 ;
     RECT  70.26 218.52 72.78 223.48 ;
     RECT  69.3 223.28 72.78 223.88 ;
     RECT  232.98 221.065 237.8 224.205 ;
     RECT  209.94 222.75 217.8 224.545 ;
     RECT  220.02 222.325 224.46 224.545 ;
     RECT  186.9 220.58 199.5 224.975 ;
     RECT  202.26 220.995 205.74 224.975 ;
     RECT  20.04 188.445 24.04 225.115 ;
     RECT  130.26 221.065 144.78 225.465 ;
     RECT  186.895 224.775 205.74 225.465 ;
     RECT  17.94 224.915 24.04 225.955 ;
     RECT  40.04 216.54 44.04 225.955 ;
     RECT  48.18 219.945 48.78 225.955 ;
     RECT  17.94 225.755 26.7 226 ;
     RECT  162.42 222.33 181.74 226.28 ;
     RECT  40.04 225.755 48.78 226.375 ;
     RECT  209.94 224.345 224.46 226.7 ;
     RECT  227.22 224.775 227.82 226.7 ;
     RECT  16.98 225.8 26.7 226.795 ;
     RECT  39.055 226.175 48.785 226.795 ;
     RECT  36.18 226.595 48.785 226.84 ;
     RECT  35.22 226.64 48.785 226.865 ;
     RECT  209.94 226.5 227.82 227.1 ;
     RECT  187.38 225.265 205.74 227.12 ;
     RECT  207.54 222.75 208.14 227.12 ;
     RECT  57.3 198.945 64.04 227.215 ;
     RECT  56.34 227.015 64.04 227.26 ;
     RECT  16.98 226.595 26.705 227.285 ;
     RECT  35.22 226.665 46.865 227.285 ;
     RECT  130.26 225.265 137.8 227.495 ;
     RECT  149.94 222.33 160.62 227.495 ;
     RECT  162.42 226.08 182.22 227.495 ;
     RECT  53.94 227.06 64.04 227.66 ;
     RECT  56.34 227.46 64.04 227.705 ;
     RECT  38.1 227.085 46.86 227.71 ;
     RECT  130.255 227.295 137.8 227.91 ;
     RECT  139.86 225.265 144.78 227.91 ;
     RECT  187.38 226.92 208.14 227.915 ;
     RECT  209.94 226.9 225.9 227.915 ;
     RECT  149.94 227.295 182.22 227.985 ;
     RECT  230.1 222.745 230.7 227.985 ;
     RECT  147.54 227.71 148.14 228.325 ;
     RECT  149.94 227.785 160.62 228.325 ;
     RECT  130.255 227.71 144.78 228.335 ;
     RECT  147.54 228.125 160.62 228.335 ;
     RECT  162.42 227.785 182.22 228.335 ;
     RECT  184.495 227.715 185.105 228.335 ;
     RECT  162.42 228.135 185.105 228.405 ;
     RECT  187.38 227.715 225.9 228.405 ;
     RECT  162.42 228.205 185.1 228.825 ;
     RECT  57.3 227.505 64.04 229.36 ;
     RECT  66.42 229.115 67.02 229.36 ;
     RECT  38.575 227.51 46.86 229.385 ;
     RECT  130.255 228.135 160.62 229.665 ;
     RECT  187.38 228.205 217.8 229.665 ;
     RECT  57.3 229.16 67.02 229.805 ;
     RECT  38.58 229.185 46.86 229.81 ;
     RECT  201.78 229.465 217.8 230.04 ;
     RECT  187.38 229.465 199.98 230.09 ;
     RECT  39.06 229.61 46.86 230.155 ;
     RECT  53.94 227.46 54.54 230.155 ;
     RECT  57.3 229.605 66.06 230.155 ;
     RECT  69.3 223.68 69.9 230.155 ;
     RECT  16.98 227.085 26.7 230.2 ;
     RECT  30.42 219.945 31.02 230.2 ;
     RECT  50.58 219.945 51.18 230.2 ;
     RECT  16.98 230 27.66 230.645 ;
     RECT  29.94 230 31.02 230.645 ;
     RECT  39.06 229.955 46.865 230.645 ;
     RECT  50.58 230 51.66 230.645 ;
     RECT  53.94 229.955 66.06 230.645 ;
     RECT  162.42 228.625 179.34 230.88 ;
     RECT  162.42 230.68 166.865 230.925 ;
     RECT  29.94 230.445 30.54 230.995 ;
     RECT  35.22 227.085 35.82 230.995 ;
     RECT  16.98 230.445 24.78 231.07 ;
     RECT  130.26 229.465 160.62 231.32 ;
     RECT  162.42 230.725 166.86 231.32 ;
     RECT  29.455 230.795 30.54 231.485 ;
     RECT  35.22 230.795 36.78 231.485 ;
     RECT  58.74 230.445 66.06 231.485 ;
     RECT  168.66 230.68 179.34 231.695 ;
     RECT  181.14 228.625 185.1 231.695 ;
     RECT  187.38 229.89 191.82 231.695 ;
     RECT  212.34 229.84 217.8 231.765 ;
     RECT  219.54 228.205 225.9 231.765 ;
     RECT  168.66 231.495 191.82 232.115 ;
     RECT  193.8 229.89 199.98 232.115 ;
     RECT  201.78 229.84 209.1 232.115 ;
     RECT  53.94 230.445 55.98 232.28 ;
     RECT  168.66 231.915 191.825 232.535 ;
     RECT  193.8 231.915 209.1 232.535 ;
     RECT  67.86 229.955 69.9 232.94 ;
     RECT  130.26 231.12 166.86 232.98 ;
     RECT  130.26 232.78 148.14 233.025 ;
     RECT  150.9 232.78 166.86 233.025 ;
     RECT  168.66 232.335 209.1 233.025 ;
     RECT  219.54 231.565 224.94 233.025 ;
     RECT  16.98 230.87 24.04 233.095 ;
     RECT  51.06 230.445 51.66 233.095 ;
     RECT  53.94 232.08 55.02 233.095 ;
     RECT  80.04 207.765 84.04 233.095 ;
     RECT  53.455 232.895 55.02 233.165 ;
     RECT  168.66 232.825 201.905 233.4 ;
     RECT  168.66 233.2 190.38 233.445 ;
     RECT  192.66 233.2 201.905 233.445 ;
     RECT  239.695 232.755 240.305 233.445 ;
     RECT  151.38 232.825 165.9 233.45 ;
     RECT  27.06 230.445 27.66 233.515 ;
     RECT  35.22 231.285 36.3 233.515 ;
     RECT  39.06 230.445 46.86 233.515 ;
     RECT  50.575 232.895 51.66 233.515 ;
     RECT  53.455 232.965 54.545 233.515 ;
     RECT  58.74 231.285 65.58 233.515 ;
     RECT  67.375 232.74 69.9 233.515 ;
     RECT  72.18 223.68 72.78 233.515 ;
     RECT  77.935 232.895 84.04 233.515 ;
     RECT  39.06 233.315 47.345 233.56 ;
     RECT  57.775 233.315 69.9 233.56 ;
     RECT  71.7 233.315 72.78 233.56 ;
     RECT  16.98 232.895 25.265 233.585 ;
     RECT  50.575 233.315 54.545 233.585 ;
     RECT  130.26 232.825 146.22 233.82 ;
     RECT  151.38 233.25 162.545 233.865 ;
     RECT  168.66 233.245 177.8 233.865 ;
     RECT  221.935 232.825 224.94 233.865 ;
     RECT  140.82 233.62 145.26 233.885 ;
     RECT  77.935 233.315 86.7 233.935 ;
     RECT  57.775 233.36 72.78 233.96 ;
     RECT  27.055 233.315 27.665 234.005 ;
     RECT  34.255 233.315 36.78 234.005 ;
     RECT  50.58 233.385 54.545 234.005 ;
     RECT  57.775 233.76 72.3 234.005 ;
     RECT  50.58 233.805 54.06 234.01 ;
     RECT  51.06 233.81 54.06 234.015 ;
     RECT  34.26 233.805 36.78 234.43 ;
     RECT  57.78 233.805 70.86 234.43 ;
     RECT  192.66 233.245 201.9 234.66 ;
     RECT  39.06 233.36 47.82 234.775 ;
     RECT  16.98 233.385 25.26 234.845 ;
     RECT  151.38 233.665 162.54 235.895 ;
     RECT  168.66 233.665 171.66 235.895 ;
     RECT  173.8 233.665 177.8 235.895 ;
     RECT  180.18 233.245 190.38 235.895 ;
     RECT  203.7 232.825 209.1 235.895 ;
     RECT  219.54 232.825 220.14 235.895 ;
     RECT  221.935 233.665 224.46 235.895 ;
     RECT  77.455 233.735 86.7 236.03 ;
     RECT  151.38 235.695 162.545 236.315 ;
     RECT  193.135 234.46 201.9 236.315 ;
     RECT  203.7 235.695 209.585 236.315 ;
     RECT  213.3 231.565 217.8 236.315 ;
     RECT  149.455 236.115 162.545 236.34 ;
     RECT  160.5 236.14 162.545 236.385 ;
     RECT  180.175 235.695 190.38 236.385 ;
     RECT  193.135 236.115 209.585 236.385 ;
     RECT  219.535 235.695 224.46 236.385 ;
     RECT  226.74 232.335 227.34 236.385 ;
     RECT  39.06 234.575 48.3 236.455 ;
     RECT  76.98 235.83 86.7 236.455 ;
     RECT  149.455 236.14 157.8 236.805 ;
     RECT  193.8 236.185 209.58 236.805 ;
     RECT  213.295 236.115 217.8 236.805 ;
     RECT  39.055 236.255 48.305 236.865 ;
     RECT  51.06 233.815 52.14 236.865 ;
     RECT  39.055 236.665 52.14 236.945 ;
     RECT  233.8 224.005 237.8 237.155 ;
     RECT  96.18 234.575 96.78 237.285 ;
     RECT  18.42 234.645 25.26 237.295 ;
     RECT  27.06 233.805 27.66 237.295 ;
     RECT  29.46 231.285 30.54 237.295 ;
     RECT  90.42 233.315 91.02 237.295 ;
     RECT  96.18 237.085 97.26 237.295 ;
     RECT  55.855 236.675 56.465 237.365 ;
     RECT  161.46 236.185 162.545 237.62 ;
     RECT  55.855 237.165 56.46 237.715 ;
     RECT  58.26 234.23 70.86 237.715 ;
     RECT  76.975 236.255 86.7 237.715 ;
     RECT  88.495 237.095 91.505 237.715 ;
     RECT  96.175 237.095 97.26 237.715 ;
     RECT  100.04 188.03 104.04 237.715 ;
     RECT  18.415 237.095 30.54 237.785 ;
     RECT  40.04 236.745 51.66 237.785 ;
     RECT  76.975 237.515 91.505 237.785 ;
     RECT  35.22 234.23 36.78 238.135 ;
     RECT  40.04 237.585 48.785 238.205 ;
     RECT  58.26 237.515 71.345 238.205 ;
     RECT  96.175 237.515 104.04 238.205 ;
     RECT  76.975 237.585 91.5 238.21 ;
     RECT  141.3 233.685 145.26 238.415 ;
     RECT  184.5 236.185 187.5 238.415 ;
     RECT  222.9 236.185 224.46 238.46 ;
     RECT  76.975 238.01 91.02 238.555 ;
     RECT  96.175 238.005 96.785 238.555 ;
     RECT  35.22 237.935 36.785 238.625 ;
     RECT  19.375 237.585 30.54 238.63 ;
     RECT  40.04 238.005 48.78 238.63 ;
     RECT  130.26 233.62 138.54 238.835 ;
     RECT  140.335 238.215 145.26 238.835 ;
     RECT  29.455 238.43 30.54 239.045 ;
     RECT  182.1 236.185 182.7 239.25 ;
     RECT  149.46 236.605 157.8 239.255 ;
     RECT  161.46 237.42 163.5 239.255 ;
     RECT  184.5 238.215 187.985 239.3 ;
     RECT  189.78 236.185 190.38 239.3 ;
     RECT  220.02 236.185 221.1 239.3 ;
     RECT  222.9 238.26 224.94 239.3 ;
     RECT  19.375 238.43 27.66 239.465 ;
     RECT  76.015 238.355 91.02 239.465 ;
     RECT  95.7 238.355 96.785 239.465 ;
     RECT  181.14 239.05 182.7 239.67 ;
     RECT  184.5 239.1 190.38 239.67 ;
     RECT  213.8 236.605 217.8 239.67 ;
     RECT  212.82 239.47 217.8 240.085 ;
     RECT  130.26 238.635 145.26 240.095 ;
     RECT  149.46 239.055 159.665 240.095 ;
     RECT  161.455 239.055 163.5 240.095 ;
     RECT  168.66 235.695 177.8 240.095 ;
     RECT  180.66 239.47 191.34 240.095 ;
     RECT  193.8 236.605 201.9 240.095 ;
     RECT  212.34 239.885 217.8 240.095 ;
     RECT  220.02 239.1 224.94 240.095 ;
     RECT  230.1 239.465 230.7 240.095 ;
     RECT  58.26 238.005 64.04 240.235 ;
     RECT  65.935 238.005 71.34 240.235 ;
     RECT  80.04 239.265 91.02 240.235 ;
     RECT  211.86 239.895 217.8 240.51 ;
     RECT  203.7 236.605 209.58 240.515 ;
     RECT  211.38 240.31 217.8 240.515 ;
     RECT  219.535 239.895 224.94 240.515 ;
     RECT  203.7 240.315 224.94 240.53 ;
     RECT  168.66 239.895 201.9 240.585 ;
     RECT  230.095 239.895 230.705 240.585 ;
     RECT  37.615 240.035 38.225 240.725 ;
     RECT  58.255 240.035 71.34 240.725 ;
     RECT  76.015 239.265 76.625 240.725 ;
     RECT  80.04 240.035 91.025 240.725 ;
     RECT  92.815 240.035 93.425 240.725 ;
     RECT  129.78 239.895 145.26 240.935 ;
     RECT  181.615 240.385 201.9 240.935 ;
     RECT  203.7 240.33 223.985 240.935 ;
     RECT  181.615 240.735 223.985 241.005 ;
     RECT  35.22 238.425 35.82 241.075 ;
     RECT  37.62 240.525 38.225 241.075 ;
     RECT  40.04 238.43 48.3 241.075 ;
     RECT  51.06 237.585 51.66 241.075 ;
     RECT  58.735 240.525 71.34 241.145 ;
     RECT  76.02 240.525 76.62 241.15 ;
     RECT  181.62 240.805 223.985 241.38 ;
     RECT  129.775 240.735 145.26 241.425 ;
     RECT  50.58 240.875 51.66 241.52 ;
     RECT  35.215 240.875 35.825 241.565 ;
     RECT  98.58 238.005 104.04 241.565 ;
     RECT  168.66 240.385 179.825 241.845 ;
     RECT  189.775 241.18 223.985 241.845 ;
     RECT  226.735 239.895 227.345 242.195 ;
     RECT  189.775 241.645 223.98 242.265 ;
     RECT  54.42 237.515 56.46 242.335 ;
     RECT  131.7 241.225 145.26 242.615 ;
     RECT  168.66 241.645 177.8 242.615 ;
     RECT  232.5 236.955 237.8 242.615 ;
     RECT  189.775 242.065 201.9 242.685 ;
     RECT  226.255 241.995 228.305 242.685 ;
     RECT  131.7 242.415 145.745 243.105 ;
     RECT  54.42 242.135 56.94 243.175 ;
     RECT  149.46 239.895 163.5 243.455 ;
     RECT  165.3 233.25 165.9 243.455 ;
     RECT  168.655 242.415 177.8 243.455 ;
     RECT  226.26 242.485 228.305 243.455 ;
     RECT  232.495 242.415 237.8 243.455 ;
     RECT  54.415 242.975 56.945 243.665 ;
     RECT  132.18 242.905 145.74 243.945 ;
     RECT  167.7 243.255 177.8 243.945 ;
     RECT  181.62 241.18 187.98 243.945 ;
     RECT  203.7 242.065 223.98 243.945 ;
     RECT  95.7 239.265 96.78 244.06 ;
     RECT  100.04 241.365 104.04 244.06 ;
     RECT  167.7 243.745 170.22 244.715 ;
     RECT  189.78 242.485 201.9 244.715 ;
     RECT  203.7 243.745 221.105 244.715 ;
     RECT  167.695 244.515 170.22 245.205 ;
     RECT  189.78 244.515 221.105 245.205 ;
     RECT  226.26 243.255 237.8 245.205 ;
     RECT  29.94 238.845 30.54 245.275 ;
     RECT  95.7 243.86 104.04 245.345 ;
     RECT  167.7 245.005 170.22 245.63 ;
     RECT  7.96 162.585 8.36 245.655 ;
     RECT  247.48 212.985 249.32 245.655 ;
     RECT  20.04 239.265 27.66 245.72 ;
     RECT  29.94 245.075 31.02 245.72 ;
     RECT  20.04 245.52 26.7 245.765 ;
     RECT  30.42 245.52 31.02 245.765 ;
     RECT  50.58 241.32 51.18 245.765 ;
     RECT  7.955 245.455 8.365 245.945 ;
     RECT  247.475 245.455 249.32 245.945 ;
     RECT  35.22 241.365 35.82 246.115 ;
     RECT  37.62 240.875 48.3 246.115 ;
     RECT  95.7 245.145 98.22 246.14 ;
     RECT  80.04 240.525 91.02 246.955 ;
     RECT  92.82 240.525 93.42 246.955 ;
     RECT  149.46 243.255 165.9 247.23 ;
     RECT  149.46 247.03 166.38 247.235 ;
     RECT  169.62 245.43 170.22 247.235 ;
     RECT  172.02 243.745 177.8 247.235 ;
     RECT  189.78 245.005 217.8 247.235 ;
     RECT  220.02 245.005 221.1 247.235 ;
     RECT  222.9 243.745 223.98 247.235 ;
     RECT  226.26 245.005 231.66 247.235 ;
     RECT  133.8 243.745 144.78 247.28 ;
     RECT  148.975 247.035 166.38 247.28 ;
     RECT  133.8 247.08 166.38 247.655 ;
     RECT  169.62 247.035 177.8 247.655 ;
     RECT  181.62 243.745 182.22 247.655 ;
     RECT  187.38 243.745 187.98 247.655 ;
     RECT  189.78 247.035 223.98 247.655 ;
     RECT  225.775 247.035 231.66 247.725 ;
     RECT  59.22 240.945 71.34 247.84 ;
     RECT  133.8 247.455 167.34 248.075 ;
     RECT  187.38 247.455 223.98 248.075 ;
     RECT  133.8 247.875 167.825 248.145 ;
     RECT  185.935 247.875 223.98 248.145 ;
     RECT  181.62 247.455 183.18 248.495 ;
     RECT  185.935 247.945 204.3 248.495 ;
     RECT  225.78 247.525 231.66 248.495 ;
     RECT  233.8 245.005 237.8 248.495 ;
     RECT  133.8 247.945 161.105 248.57 ;
     RECT  20.04 245.565 26.22 248.635 ;
     RECT  55.86 243.465 56.94 248.635 ;
     RECT  58.74 247.64 71.34 248.635 ;
     RECT  96.18 245.94 98.22 248.635 ;
     RECT  100.04 245.145 104.04 248.635 ;
     RECT  133.8 248.37 142.38 248.72 ;
     RECT  140.335 248.52 142.38 248.985 ;
     RECT  144.66 248.37 161.105 248.99 ;
     RECT  35.22 245.915 48.3 249.055 ;
     RECT  20.04 248.435 26.705 249.125 ;
     RECT  80.04 246.755 93.42 249.125 ;
     RECT  181.62 248.295 204.3 249.335 ;
     RECT  76.015 249.275 76.625 249.52 ;
     RECT  35.22 248.855 49.745 249.545 ;
     RECT  20.04 248.925 26.7 249.55 ;
     RECT  163.38 247.945 167.825 249.755 ;
     RECT  169.62 247.455 178.38 249.755 ;
     RECT  180.175 249.135 204.3 249.755 ;
     RECT  206.1 247.945 223.98 249.825 ;
     RECT  55.86 248.435 71.34 249.965 ;
     RECT  75.54 249.32 76.625 249.965 ;
     RECT  35.22 249.345 49.74 249.97 ;
     RECT  206.1 249.625 221.105 250.175 ;
     RECT  147.54 248.79 161.105 250.245 ;
     RECT  35.22 249.77 48.785 250.385 ;
     RECT  75.54 249.765 76.62 250.39 ;
     RECT  163.38 249.555 204.3 250.59 ;
     RECT  206.095 249.975 221.105 250.59 ;
     RECT  223.38 249.625 223.98 250.59 ;
     RECT  225.78 248.295 237.8 250.59 ;
     RECT  144.66 248.79 145.745 250.665 ;
     RECT  35.22 250.185 48.78 250.81 ;
     RECT  141.78 248.785 142.38 251.015 ;
     RECT  163.38 250.39 221.105 251.015 ;
     RECT  145.135 250.465 145.745 251.085 ;
     RECT  223.38 250.39 237.8 251.46 ;
     RECT  141.775 250.815 142.385 251.505 ;
     RECT  147.54 250.045 161.1 251.505 ;
     RECT  163.375 250.815 221.105 251.505 ;
     RECT  223.38 251.26 231.66 251.505 ;
     RECT  145.14 250.885 145.74 251.515 ;
     RECT  96.18 248.435 104.04 251.57 ;
     RECT  163.38 251.305 165.425 251.925 ;
     RECT  167.695 251.305 182.22 251.925 ;
     RECT  212.815 251.305 221.105 251.925 ;
     RECT  58.26 249.765 71.34 251.995 ;
     RECT  88.02 248.925 92.94 251.995 ;
     RECT  95.22 251.37 104.04 251.995 ;
     RECT  35.22 250.61 47.34 252.065 ;
     RECT  223.38 251.305 223.98 252.275 ;
     RECT  147.54 251.305 158.7 252.3 ;
     RECT  88.02 251.795 92.945 252.415 ;
     RECT  58.255 251.795 71.34 252.485 ;
     RECT  40.04 251.865 47.34 252.49 ;
     RECT  184.5 251.305 211.02 252.72 ;
     RECT  212.815 251.725 221.1 252.765 ;
     RECT  226.255 251.305 230.225 252.765 ;
     RECT  35.22 251.865 37.74 252.835 ;
     RECT  55.86 249.765 56.46 252.835 ;
     RECT  80.04 248.925 85.26 252.835 ;
     RECT  88.02 252.215 93.425 252.835 ;
     RECT  50.575 252.215 51.185 252.905 ;
     RECT  58.735 252.285 71.34 252.905 ;
     RECT  80.04 252.635 93.425 252.905 ;
     RECT  95.215 251.795 104.04 252.905 ;
     RECT  226.26 252.565 230.22 253.19 ;
     RECT  45.775 252.29 47.34 253.325 ;
     RECT  55.855 252.635 56.465 253.325 ;
     RECT  80.04 252.705 93.42 253.325 ;
     RECT  95.215 252.705 98.225 253.325 ;
     RECT  50.575 252.705 51.18 253.33 ;
     RECT  92.82 253.125 93.42 253.335 ;
     RECT  233.8 251.26 237.8 253.535 ;
     RECT  55.855 253.125 56.46 253.675 ;
     RECT  58.74 252.705 71.34 253.675 ;
     RECT  49.615 253.475 50.225 253.72 ;
     RECT  95.22 253.125 98.225 253.745 ;
     RECT  58.74 253.475 71.345 253.75 ;
     RECT  80.04 253.125 91.025 253.75 ;
     RECT  95.22 253.545 98.22 253.75 ;
     RECT  212.82 252.565 221.1 253.955 ;
     RECT  222.895 252.075 223.98 253.955 ;
     RECT  232.015 253.335 237.8 254.025 ;
     RECT  34.26 252.635 37.74 254.12 ;
     RECT  16.495 253.475 17.105 254.165 ;
     RECT  49.14 253.52 50.225 254.165 ;
     RECT  54.415 253.475 56.46 254.165 ;
     RECT  66.9 253.55 71.345 254.165 ;
     RECT  80.04 253.55 88.145 254.165 ;
     RECT  90.415 253.55 91.025 254.165 ;
     RECT  96.175 253.55 98.22 254.165 ;
     RECT  97.14 253.965 98.22 254.175 ;
     RECT  169.14 251.725 182.22 254.785 ;
     RECT  184.5 252.52 210.54 254.785 ;
     RECT  169.14 254.585 210.54 254.79 ;
     RECT  147.54 252.1 148.14 254.795 ;
     RECT  169.14 254.59 211.02 254.795 ;
     RECT  153.3 252.1 158.7 255.215 ;
     RECT  160.5 251.305 161.1 255.215 ;
     RECT  168.655 254.595 211.02 255.215 ;
     RECT  212.82 253.755 223.985 255.215 ;
     RECT  147.535 254.595 148.145 255.285 ;
     RECT  168.655 255.015 223.985 255.285 ;
     RECT  153.3 255.015 161.1 255.705 ;
     RECT  20.04 249.35 25.74 255.775 ;
     RECT  54.42 253.965 56.46 255.775 ;
     RECT  168.66 255.085 223.985 255.8 ;
     RECT  226.26 252.99 228.78 256.055 ;
     RECT  221.46 255.6 223.985 256.1 ;
     RECT  225.78 255.855 228.78 256.1 ;
     RECT  143.695 255.435 144.305 256.125 ;
     RECT  168.66 255.6 218.7 256.13 ;
     RECT  20.04 255.575 25.745 256.195 ;
     RECT  29.94 252.635 30.54 256.195 ;
     RECT  34.26 253.92 36.3 256.195 ;
     RECT  49.14 253.965 50.22 256.195 ;
     RECT  54.42 255.575 56.94 256.195 ;
     RECT  58.74 253.55 65.1 256.195 ;
     RECT  66.9 253.965 69.9 256.195 ;
     RECT  80.04 253.965 88.14 256.195 ;
     RECT  49.14 255.995 50.705 256.24 ;
     RECT  53.455 255.995 56.94 256.265 ;
     RECT  58.74 255.995 70.865 256.265 ;
     RECT  168.66 255.93 178.38 256.5 ;
     RECT  221.46 255.9 228.78 256.5 ;
     RECT  58.74 256.065 64.04 256.615 ;
     RECT  29.94 255.995 31.02 256.64 ;
     RECT  33.295 255.995 36.3 256.685 ;
     RECT  53.455 256.065 55.02 256.685 ;
     RECT  65.935 256.065 70.865 256.685 ;
     RECT  72.655 255.995 73.265 256.685 ;
     RECT  180.175 255.93 218.7 256.965 ;
     RECT  58.26 256.415 64.04 257.105 ;
     RECT  65.935 256.485 70.86 257.11 ;
     RECT  33.3 256.485 36.3 257.455 ;
     RECT  40.04 252.29 44.04 257.455 ;
     RECT  45.78 253.125 47.34 257.455 ;
     RECT  75.54 250.19 76.14 257.455 ;
     RECT  97.14 253.975 97.74 257.455 ;
     RECT  100.04 252.705 104.04 257.455 ;
     RECT  33.3 257.255 36.78 257.5 ;
     RECT  40.04 257.255 47.34 257.5 ;
     RECT  75.54 257.255 76.62 257.5 ;
     RECT  80.04 255.995 89.58 257.5 ;
     RECT  59.215 256.905 64.04 257.525 ;
     RECT  65.935 256.91 68.94 257.525 ;
     RECT  153.3 255.505 157.8 257.73 ;
     RECT  160.02 255.505 161.1 257.73 ;
     RECT  186.895 256.765 218.7 257.735 ;
     RECT  221.46 256.3 227.825 257.735 ;
     RECT  33.3 257.3 47.34 257.945 ;
     RECT  75.54 257.3 89.58 257.945 ;
     RECT  59.22 257.325 64.04 257.95 ;
     RECT  232.02 253.825 237.8 258.15 ;
     RECT  152.82 257.53 161.1 258.155 ;
     RECT  168.66 256.3 171.18 258.155 ;
     RECT  230.58 257.95 237.8 258.57 ;
     RECT  149.46 257.95 150.06 258.575 ;
     RECT  163.38 251.725 164.94 258.575 ;
     RECT  167.215 257.955 171.18 258.575 ;
     RECT  172.98 256.3 178.38 258.575 ;
     RECT  180.175 256.765 182.22 258.575 ;
     RECT  152.815 257.955 161.1 258.645 ;
     RECT  172.98 258.375 182.22 258.645 ;
     RECT  186.895 257.535 227.825 258.645 ;
     RECT  166.735 258.375 171.18 258.995 ;
     RECT  230.1 258.37 237.8 258.995 ;
     RECT  186.895 258.445 209.1 259.02 ;
     RECT  140.815 258.375 141.425 259.065 ;
     RECT  149.455 258.375 150.065 259.065 ;
     RECT  163.38 258.375 164.945 259.065 ;
     RECT  166.735 258.795 171.185 259.065 ;
     RECT  184.015 256.765 185.1 259.065 ;
     RECT  186.895 258.82 188.46 259.065 ;
     RECT  190.74 258.82 209.1 259.065 ;
     RECT  211.375 258.445 227.82 259.065 ;
     RECT  202.74 258.865 209.1 259.075 ;
     RECT  166.74 258.865 171.185 259.485 ;
     RECT  213.8 258.865 227.82 259.485 ;
     RECT  230.095 258.795 237.8 259.485 ;
     RECT  77.94 257.745 89.58 259.625 ;
     RECT  105.775 258.935 106.385 259.625 ;
     RECT  191.215 258.865 200.465 259.905 ;
     RECT  202.74 258.875 206.705 259.905 ;
     RECT  211.375 258.865 211.985 259.905 ;
     RECT  220.495 259.285 223.5 259.905 ;
     RECT  226.255 259.285 227.82 259.905 ;
     RECT  20.04 255.995 26.7 259.975 ;
     RECT  30.42 256.44 31.02 259.975 ;
     RECT  66.9 257.325 68.94 260.3 ;
     RECT  220.5 259.705 223.5 260.325 ;
     RECT  220.5 260.125 221.58 260.33 ;
     RECT  226.26 259.705 227.82 260.33 ;
     RECT  93.3 255.995 93.9 260.385 ;
     RECT  20.04 259.775 26.705 260.395 ;
     RECT  28.975 259.775 31.02 260.395 ;
     RECT  33.3 257.745 36.3 260.395 ;
     RECT  38.1 257.745 47.34 260.395 ;
     RECT  49.14 256.04 51.18 260.395 ;
     RECT  66.48 260.1 68.94 260.395 ;
     RECT  72.66 256.485 73.26 260.395 ;
     RECT  75.54 257.745 76.14 260.395 ;
     RECT  86.1 259.425 89.58 260.395 ;
     RECT  93.3 260.185 95.34 260.395 ;
     RECT  97.14 257.255 104.04 260.395 ;
     RECT  20.04 260.195 31.02 260.44 ;
     RECT  33.3 260.195 36.305 260.44 ;
     RECT  20.04 260.24 36.305 260.84 ;
     RECT  33.3 260.64 36.305 260.885 ;
     RECT  53.46 256.485 54.06 260.885 ;
     RECT  66.42 260.195 68.94 260.885 ;
     RECT  72.66 260.195 76.14 260.885 ;
     RECT  86.1 260.195 91.025 260.885 ;
     RECT  93.295 260.195 104.04 260.885 ;
     RECT  20.04 260.64 31.02 260.895 ;
     RECT  34.26 260.685 36.305 261.235 ;
     RECT  38.1 260.195 51.18 261.235 ;
     RECT  60.04 257.75 64.04 261.235 ;
     RECT  93.3 260.685 95.345 261.305 ;
     RECT  20.04 260.695 27.66 261.31 ;
     RECT  34.26 261.035 51.18 261.31 ;
     RECT  86.1 260.685 91.02 261.31 ;
     RECT  29.455 260.695 31.02 261.725 ;
     RECT  34.26 261.11 48.785 261.725 ;
     RECT  98.1 260.685 104.04 261.725 ;
     RECT  159.54 258.445 161.1 261.935 ;
     RECT  172.98 258.445 177.8 261.935 ;
     RECT  179.7 258.445 182.22 261.935 ;
     RECT  191.215 259.705 200.46 261.935 ;
     RECT  140.82 258.865 141.42 262.005 ;
     RECT  191.215 261.735 200.465 262.005 ;
     RECT  166.74 259.285 169.26 262.355 ;
     RECT  202.74 259.705 205.74 262.355 ;
     RECT  208.5 258.875 209.1 262.355 ;
     RECT  220.98 260.13 221.58 262.355 ;
     RECT  147.055 262.155 147.665 262.4 ;
     RECT  159.535 261.735 161.1 262.425 ;
     RECT  171.055 261.735 177.8 262.425 ;
     RECT  179.695 261.735 182.22 262.425 ;
     RECT  191.215 261.805 197.8 262.425 ;
     RECT  199.855 261.805 200.465 262.425 ;
     RECT  208.015 262.155 209.1 262.775 ;
     RECT  146.58 262.2 147.665 262.82 ;
     RECT  150.895 261.735 151.505 262.82 ;
     RECT  166.735 262.155 169.26 262.845 ;
     RECT  208.015 262.575 210.54 262.845 ;
     RECT  220.98 262.155 223.505 262.845 ;
     RECT  146.58 262.62 151.505 263.195 ;
     RECT  153.3 258.445 157.8 263.195 ;
     RECT  146.58 262.995 157.8 263.265 ;
     RECT  166.74 262.645 169.26 263.265 ;
     RECT  171.06 262.225 177.8 263.265 ;
     RECT  186.9 258.865 188.46 263.265 ;
     RECT  191.22 262.225 197.8 263.265 ;
     RECT  202.735 262.155 205.74 263.265 ;
     RECT  208.02 262.645 210.54 263.265 ;
     RECT  220.98 262.645 223.5 263.265 ;
     RECT  227.22 260.13 227.82 263.265 ;
     RECT  208.02 263.065 208.62 263.275 ;
     RECT  222.9 263.065 223.5 263.275 ;
     RECT  67.86 260.685 68.94 263.335 ;
     RECT  73.62 260.685 76.14 263.335 ;
     RECT  77.94 259.425 84.04 263.335 ;
     RECT  86.1 261.11 89.58 263.335 ;
     RECT  159.54 262.225 161.1 263.615 ;
     RECT  20.04 261.11 26.7 263.825 ;
     RECT  34.26 261.525 48.78 263.825 ;
     RECT  67.38 263.135 70.385 263.825 ;
     RECT  73.615 263.135 76.14 263.825 ;
     RECT  59.22 261.035 64.04 264.175 ;
     RECT  68.34 263.625 70.38 264.2 ;
     RECT  26.1 263.625 26.7 264.245 ;
     RECT  46.26 263.625 48.78 264.245 ;
     RECT  50.58 261.11 51.18 264.245 ;
     RECT  73.62 263.625 76.14 264.25 ;
     RECT  199.86 262.225 200.46 264.5 ;
     RECT  202.735 263.065 203.34 264.5 ;
     RECT  34.26 263.625 44.04 264.665 ;
     RECT  59.22 263.975 66.06 264.665 ;
     RECT  105.78 259.425 106.38 264.665 ;
     RECT  133.8 248.52 137.8 264.875 ;
     RECT  159.54 263.415 161.58 264.875 ;
     RECT  205.135 263.065 205.74 264.875 ;
     RECT  199.86 264.3 203.34 264.9 ;
     RECT  211.375 264.675 211.985 264.92 ;
     RECT  213.8 259.285 217.8 264.92 ;
     RECT  98.58 261.525 104.04 265.015 ;
     RECT  29.46 261.525 31.02 265.04 ;
     RECT  56.34 264.815 56.94 265.06 ;
     RECT  148.5 263.065 150.065 265.295 ;
     RECT  152.82 263.065 157.8 265.295 ;
     RECT  159.54 264.675 161.585 265.295 ;
     RECT  187.86 263.065 188.46 265.295 ;
     RECT  148.5 265.095 161.585 265.365 ;
     RECT  172.015 263.065 177.8 265.365 ;
     RECT  205.135 264.675 205.745 265.365 ;
     RECT  211.375 264.72 217.8 265.365 ;
     RECT  53.94 264.86 56.94 265.46 ;
     RECT  56.34 265.26 56.94 265.505 ;
     RECT  148.5 265.165 160.14 265.74 ;
     RECT  187.86 265.095 189.42 265.74 ;
     RECT  143.7 255.925 144.3 265.785 ;
     RECT  148.5 265.54 151.98 265.785 ;
     RECT  153.8 265.54 159.66 265.785 ;
     RECT  188.82 265.54 189.42 265.785 ;
     RECT  199.86 264.7 201.42 265.785 ;
     RECT  211.86 265.165 217.8 265.785 ;
     RECT  232.02 259.285 237.8 265.785 ;
     RECT  239.7 233.245 240.3 265.785 ;
     RECT  98.58 264.815 105.905 266.345 ;
     RECT  133.135 264.675 137.8 266.555 ;
     RECT  167.22 263.065 169.26 266.555 ;
     RECT  181.62 262.225 182.22 266.555 ;
     RECT  191.7 263.065 197.8 266.555 ;
     RECT  199.86 265.585 200.46 266.555 ;
     RECT  227.22 266.35 227.82 266.555 ;
     RECT  181.62 266.355 182.7 266.6 ;
     RECT  184.5 258.865 185.1 266.6 ;
     RECT  205.135 265.165 205.74 266.97 ;
     RECT  227.22 266.355 228.78 266.975 ;
     RECT  181.62 266.4 185.1 267 ;
     RECT  149.46 265.585 151.02 267.045 ;
     RECT  166.74 266.355 169.26 267.045 ;
     RECT  172.02 265.165 177.8 267.045 ;
     RECT  181.62 266.8 182.7 267.045 ;
     RECT  189.78 266.355 200.46 267.045 ;
     RECT  220.5 266.355 221.1 267.385 ;
     RECT  181.62 266.845 182.225 267.395 ;
     RECT  204.18 266.77 205.74 267.395 ;
     RECT  163.38 258.865 163.98 267.44 ;
     RECT  165.78 267.195 166.38 267.44 ;
     RECT  181.14 267.195 182.225 267.44 ;
     RECT  227.215 266.775 228.78 267.465 ;
     RECT  16.5 253.965 17.1 267.535 ;
     RECT  20.04 263.625 24.04 267.535 ;
     RECT  34.26 264.465 37.26 267.535 ;
     RECT  39.06 264.465 44.04 267.535 ;
     RECT  163.38 267.24 166.38 267.815 ;
     RECT  219.54 267.185 221.1 267.815 ;
     RECT  163.375 267.615 166.38 267.885 ;
     RECT  189.78 266.845 199.5 267.885 ;
     RECT  204.175 267.195 205.74 267.885 ;
     RECT  69.3 264 70.38 267.955 ;
     RECT  75.54 264.05 76.14 267.955 ;
     RECT  77.94 263.135 89.58 267.955 ;
     RECT  16.5 267.335 24.785 268.025 ;
     RECT  34.26 267.335 45.905 268.025 ;
     RECT  48.18 264.045 48.78 268.025 ;
     RECT  53.94 265.26 54.54 268.025 ;
     RECT  74.095 267.755 89.585 268.025 ;
     RECT  98.58 266.145 105.9 268.025 ;
     RECT  168.655 266.845 169.26 268.235 ;
     RECT  163.375 267.685 165.9 268.305 ;
     RECT  219.535 267.615 221.1 268.305 ;
     RECT  29.46 264.84 30.54 268.445 ;
     RECT  34.26 267.825 37.74 268.445 ;
     RECT  69.295 267.755 70.38 268.445 ;
     RECT  74.095 267.825 77.58 268.445 ;
     RECT  80.04 267.825 89.585 268.445 ;
     RECT  93.3 261.105 93.9 268.445 ;
     RECT  17.46 267.825 24.78 268.45 ;
     RECT  40.04 267.825 45.905 268.45 ;
     RECT  168.655 268.035 169.265 268.725 ;
     RECT  59.22 264.465 65.1 268.795 ;
     RECT  132.18 266.355 137.8 268.8 ;
     RECT  153.8 265.585 158.7 268.8 ;
     RECT  172.98 266.845 177.8 268.8 ;
     RECT  193.8 267.685 199.5 268.8 ;
     RECT  212.82 265.585 217.8 268.8 ;
     RECT  232.98 265.585 237.8 268.8 ;
     RECT  52.98 268.595 53.58 268.84 ;
     RECT  74.1 268.245 74.7 268.87 ;
     RECT  88.98 268.245 89.585 268.87 ;
     RECT  180.66 267.24 182.225 269.145 ;
     RECT  124.6 213.505 127.5 269.175 ;
     RECT  17.46 268.25 24.04 269.285 ;
     RECT  35.7 268.245 37.74 269.285 ;
     RECT  46.74 268.595 47.82 269.285 ;
     RECT  52.5 268.64 53.58 269.285 ;
     RECT  92.815 268.595 93.425 269.285 ;
     RECT  124.595 268.975 127.5 269.465 ;
     RECT  135.635 268.6 136.045 269.465 ;
     RECT  113.08 171.825 113.96 269.595 ;
     RECT  89.555 269.395 89.965 269.885 ;
     RECT  113.075 269.395 113.96 269.885 ;
     RECT  17.94 269.085 24.04 270.2 ;
     RECT  40.04 268.25 44.94 270.2 ;
     RECT  58.26 268.595 65.1 270.2 ;
     RECT  80.04 268.245 86.7 270.2 ;
     RECT  98.58 267.825 105.42 270.2 ;
     RECT  71.795 269.815 72.205 270.305 ;
     RECT  155.315 268.6 155.725 270.305 ;
     RECT  142.74 266.355 143.34 270.8 ;
     RECT  150.42 266.845 151.02 270.8 ;
     RECT  158.1 268.6 158.7 270.8 ;
     RECT  189.78 267.685 190.38 270.8 ;
     RECT  205.14 267.685 205.74 270.8 ;
     RECT  212.82 268.6 213.42 270.8 ;
     RECT  220.5 268.105 221.1 270.8 ;
     RECT  228.18 267.265 228.78 270.8 ;
     RECT  232.98 268.6 233.58 270.8 ;
     RECT  240.66 266.355 241.26 270.8 ;
     RECT  142.26 270.6 143.34 271.2 ;
     RECT  149.94 270.6 151.02 271.2 ;
     RECT  157.62 270.6 158.7 271.2 ;
     RECT  188.34 270.6 190.38 271.2 ;
     RECT  203.7 270.6 205.74 271.2 ;
     RECT  211.38 270.6 213.42 271.2 ;
     RECT  219.06 270.6 221.1 271.2 ;
     RECT  226.74 270.6 228.78 271.2 ;
     RECT  232.98 270.6 235.02 271.2 ;
     RECT  240.66 270.6 242.7 271.2 ;
     RECT  104.34 270 105.42 271.34 ;
     RECT  64.02 270 65.1 271.76 ;
     RECT  54.995 271.915 55.405 272.405 ;
     RECT  232.115 271.915 232.525 272.405 ;
     RECT  76.98 268.245 77.58 272.575 ;
     RECT  84.18 270 86.7 272.575 ;
     RECT  17.94 270 19.98 272.995 ;
     RECT  71.8 270.105 72.2 272.995 ;
     RECT  75.535 272.375 77.58 272.995 ;
     RECT  75.535 272.795 77.585 273.065 ;
     RECT  84.175 272.375 86.7 273.065 ;
     RECT  17.94 272.795 19.985 273.485 ;
     RECT  23.695 272.795 24.305 273.485 ;
     RECT  69.775 272.795 72.2 273.485 ;
     RECT  75.54 272.865 77.585 273.485 ;
     RECT  118.36 162.295 122.12 273.795 ;
     RECT  106.835 273.595 107.245 274.085 ;
     RECT  118.355 273.595 122.12 274.085 ;
     RECT  139.955 273.595 140.365 274.085 ;
     RECT  98.58 270 99.18 274.215 ;
     RECT  98.58 274.015 101.005 274.505 ;
     RECT  147.635 274.435 148.045 274.925 ;
     RECT  113.56 269.685 113.96 275.055 ;
     RECT  165.3 268.105 165.9 275.055 ;
     RECT  113.555 274.855 113.965 275.345 ;
     RECT  165.3 274.855 166.765 275.345 ;
     RECT  64.02 271.56 64.62 275.475 ;
     RECT  125.56 269.265 127.5 275.475 ;
     RECT  63.155 275.275 64.62 275.765 ;
     RECT  125.555 275.275 127.5 275.765 ;
     RECT  26.195 275.695 26.605 276.185 ;
     RECT  194.195 275.695 194.605 276.185 ;
     RECT  44.34 270 44.94 276.355 ;
     RECT  35.7 269.085 36.3 276.4 ;
     RECT  41.455 276.155 42.065 276.4 ;
     RECT  84.66 272.865 86.7 276.4 ;
     RECT  119.32 273.885 122.12 276.735 ;
     RECT  84.66 276.2 87.66 276.775 ;
     RECT  35.22 276.2 36.3 276.8 ;
     RECT  84.655 276.575 87.66 276.8 ;
     RECT  41.28 276.2 42.065 276.82 ;
     RECT  40.98 276.62 42.065 276.845 ;
     RECT  44.335 276.155 44.945 276.845 ;
     RECT  119.315 276.535 122.12 277.025 ;
     RECT  23.7 273.285 24.3 277.045 ;
     RECT  26.195 275.985 26.6 277.045 ;
     RECT  52.5 269.085 53.1 277.045 ;
     RECT  55 272.205 55.4 277.045 ;
     RECT  87.06 276.6 87.66 277.045 ;
     RECT  89.56 269.685 89.96 277.045 ;
     RECT  104.34 271.14 104.94 277.045 ;
     RECT  106.84 273.885 107.24 277.045 ;
     RECT  132.18 268.6 132.78 277.1 ;
     RECT  135.64 269.265 136.04 277.1 ;
     RECT  194.2 275.985 194.605 277.1 ;
     RECT  198.9 268.6 199.5 277.1 ;
     RECT  13.24 172.665 14.12 277.155 ;
     RECT  69.78 273.285 72.2 277.155 ;
     RECT  120.28 276.825 122.12 277.155 ;
     RECT  180.66 268.945 181.26 277.155 ;
     RECT  69.78 276.955 73.645 277.2 ;
     RECT  75.54 273.285 76.14 277.2 ;
     RECT  40.98 276.645 41.88 277.22 ;
     RECT  29.46 268.245 30.06 277.235 ;
     RECT  58.26 270 58.86 277.235 ;
     RECT  23.7 276.845 26.6 277.245 ;
     RECT  52.5 276.845 55.4 277.245 ;
     RECT  63.16 275.565 64.62 277.245 ;
     RECT  69.78 277 76.14 277.245 ;
     RECT  87.06 276.845 89.96 277.245 ;
     RECT  98.58 274.305 101 277.245 ;
     RECT  104.34 276.845 107.24 277.245 ;
     RECT  81.295 276.575 81.905 277.265 ;
     RECT  84.655 276.6 85.265 277.265 ;
     RECT  73.235 277.045 76.14 277.4 ;
     RECT  29.46 277.035 32.36 277.435 ;
     RECT  58.26 277.035 61.16 277.435 ;
     RECT  17.94 273.285 18.54 277.44 ;
     RECT  23.7 277.045 24.3 277.44 ;
     RECT  29.46 277.235 30.06 277.44 ;
     RECT  35.22 276.6 35.82 277.44 ;
     RECT  40.98 277.02 41.58 277.44 ;
     RECT  46.74 269.085 47.34 277.44 ;
     RECT  52.5 277.045 53.1 277.44 ;
     RECT  58.26 277.235 58.86 277.44 ;
     RECT  64.02 277.045 64.62 277.44 ;
     RECT  69.78 277.045 70.38 277.44 ;
     RECT  75.54 277.2 76.14 277.44 ;
     RECT  81.3 277.065 81.9 277.44 ;
     RECT  87.06 277.045 87.66 277.44 ;
     RECT  92.82 269.085 93.42 277.44 ;
     RECT  98.58 277.045 99.18 277.44 ;
     RECT  104.34 277.045 104.94 277.44 ;
     RECT  13.24 276.955 14.125 277.445 ;
     RECT  73.235 277.2 73.645 277.445 ;
     RECT  120.28 276.955 122.125 277.445 ;
     RECT  179.795 276.955 181.26 277.445 ;
     RECT  139.96 273.885 140.36 277.96 ;
     RECT  142.26 271 142.86 277.96 ;
     RECT  147.64 274.725 148.04 277.96 ;
     RECT  149.94 271 150.54 277.96 ;
     RECT  155.32 270.105 155.72 277.96 ;
     RECT  157.62 271 158.22 277.96 ;
     RECT  232.12 272.205 232.52 277.96 ;
     RECT  234.42 271 235.02 277.96 ;
     RECT  188.34 271 188.94 278.105 ;
     RECT  242.1 271 242.7 278.15 ;
     RECT  126.04 275.565 127.5 278.16 ;
     RECT  132.18 276.9 136.04 278.16 ;
     RECT  139.96 277.76 142.86 278.16 ;
     RECT  147.64 277.76 150.54 278.16 ;
     RECT  155.32 277.76 158.22 278.16 ;
     RECT  165.3 275.145 166.76 278.16 ;
     RECT  179.8 277.245 181.26 278.16 ;
     RECT  194.2 276.9 199.5 278.16 ;
     RECT  232.12 277.76 235.02 278.16 ;
     RECT  41.17 277.24 41.58 278.285 ;
     RECT  132.18 277.96 135.18 278.34 ;
     RECT  196.02 277.96 199.5 278.34 ;
     RECT  239.8 277.95 242.7 278.35 ;
     RECT  126.9 277.96 127.5 278.355 ;
     RECT  134.58 278.14 135.18 278.355 ;
     RECT  142.26 277.96 142.86 278.355 ;
     RECT  149.94 277.96 150.54 278.355 ;
     RECT  157.62 277.96 158.22 278.355 ;
     RECT  165.3 277.96 165.9 278.355 ;
     RECT  172.98 268.6 173.58 278.355 ;
     RECT  180.66 277.96 181.26 278.355 ;
     RECT  187.475 277.905 188.94 278.355 ;
     RECT  196.02 278.14 196.62 278.355 ;
     RECT  203.7 271 204.3 278.355 ;
     RECT  211.38 271 211.98 278.355 ;
     RECT  219.06 271 219.66 278.355 ;
     RECT  226.74 271 227.34 278.355 ;
     RECT  234.42 277.96 235.02 278.355 ;
     RECT  242.1 278.15 242.7 278.355 ;
     RECT  187.475 278.155 187.885 278.395 ;
     RECT  248.92 245.745 249.32 278.415 ;
     RECT  18.13 277.24 18.54 278.705 ;
     RECT  248.915 278.215 249.325 278.705 ;
     RECT  46.93 277.24 47.34 279.125 ;
     RECT  226.74 278.155 227.15 279.125 ;
     RECT  35.315 277.24 35.725 279.545 ;
     RECT  211.38 278.155 211.79 279.545 ;
     RECT  31.96 277.235 32.36 279.675 ;
     RECT  31.955 279.475 32.365 279.965 ;
     RECT  203.7 278.155 204.11 279.965 ;
     RECT  81.4 277.24 81.8 280.095 ;
     RECT  120.28 277.245 120.68 280.095 ;
     RECT  81.395 279.895 81.805 280.385 ;
     RECT  120.275 279.895 120.685 280.385 ;
     RECT  60.76 277.235 61.16 280.935 ;
     RECT  239.8 278.15 240.2 280.935 ;
     RECT  60.755 280.735 61.165 281.225 ;
     RECT  239.795 280.735 240.205 281.225 ;
     RECT  13.24 277.245 13.64 281.355 ;
     RECT  173.08 278.155 173.48 281.355 ;
     RECT  13.235 281.155 13.645 281.645 ;
     RECT  173.075 281.155 173.485 281.645 ;
    LAYER Metal3 ;
     RECT  0.1 48.94 6.485 49.34 ;
     RECT  5.035 129.58 6.675 129.98 ;
     RECT  0.1 147.22 6.965 147.62 ;
     RECT  5.86 154.78 7.58 155.18 ;
     RECT  5.86 162.34 7.58 162.74 ;
     RECT  0.1 245.5 8.405 245.9 ;
     RECT  6.475 25.42 13.875 25.82 ;
     RECT  6.475 129.58 15.1 130.82 ;
     RECT  6.955 134.2 15.1 134.6 ;
     RECT  14.9 129.58 15.125 134.6 ;
     RECT  13.675 25.42 15.84 26.24 ;
     RECT  13.195 172.42 16.085 172.82 ;
     RECT  14.925 130.42 16.62 134.6 ;
     RECT  14.9 139.66 16.62 140.06 ;
     RECT  14.9 147.22 16.62 147.62 ;
     RECT  14.9 154.78 16.62 155.18 ;
     RECT  15.64 25.42 17.135 30.88 ;
     RECT  16.935 25.42 18.095 31.38 ;
     RECT  16.935 77.82 18.095 78.42 ;
     RECT  13.675 277 18.29 277.4 ;
     RECT  16.42 134.2 18.3 134.6 ;
     RECT  13.675 151.42 18.3 151.82 ;
     RECT  16.935 57.24 18.575 57.84 ;
     RECT  15.64 66.88 18.575 70.88 ;
     RECT  17.895 77.4 18.575 78.42 ;
     RECT  17.895 232.94 18.575 233.54 ;
     RECT  17.895 24.06 19.055 31.38 ;
     RECT  15.64 46.88 19.055 50.88 ;
     RECT  18.375 57.24 19.055 58.26 ;
     RECT  18.375 66.88 19.055 72.12 ;
     RECT  18.375 230.84 19.055 233.54 ;
     RECT  18.855 57.24 19.1 59.1 ;
     RECT  18.855 65.73 19.1 72.12 ;
     RECT  16.455 39.6 19.535 40.2 ;
     RECT  18.855 54.3 19.535 54.9 ;
     RECT  18.9 57.24 19.535 59.52 ;
     RECT  18.9 65.64 19.535 72.12 ;
     RECT  17.415 95.04 19.535 95.64 ;
     RECT  18.855 100.92 19.535 101.52 ;
     RECT  18.375 237.14 19.535 237.74 ;
     RECT  18.1 134.2 19.82 136.28 ;
     RECT  18.1 143.44 19.82 143.84 ;
     RECT  18.1 151 19.82 151.82 ;
     RECT  18.1 158.56 19.82 158.96 ;
     RECT  16.455 253.52 24.335 254.12 ;
     RECT  19.335 272.84 24.345 273.44 ;
     RECT  19.335 100.92 24.815 103.2 ;
     RECT  19.335 237.14 24.815 239.42 ;
     RECT  15.64 241.58 24.815 245.58 ;
     RECT  18.855 24.06 24.825 33.48 ;
     RECT  16.935 61.86 24.825 62.46 ;
     RECT  18.375 76.56 24.825 78.42 ;
     RECT  24.615 98.82 24.825 103.2 ;
     RECT  18.855 228.74 24.825 233.96 ;
     RECT  24.135 253.52 24.825 256.22 ;
     RECT  18.375 267.38 24.825 267.98 ;
     RECT  19.335 65.64 25.295 74.22 ;
     RECT  15.64 86.88 25.295 90.88 ;
     RECT  24.625 102.6 25.305 103.2 ;
     RECT  24.625 230.84 25.305 233.54 ;
     RECT  24.625 25.84 25.775 33.48 ;
     RECT  17.415 35.82 25.775 36.42 ;
     RECT  19.335 81.6 25.775 82.2 ;
     RECT  16.935 84.54 25.775 85.14 ;
     RECT  25.095 86.88 25.775 91.44 ;
     RECT  24.625 255.62 25.785 256.22 ;
     RECT  19.335 39.18 26.255 40.2 ;
     RECT  15.64 106.88 26.255 108.48 ;
     RECT  24.135 188 26.255 188.6 ;
     RECT  15.64 221.58 26.255 225.58 ;
     RECT  15.64 261.58 26.255 265.58 ;
     RECT  19.335 54.3 26.265 59.52 ;
     RECT  19.335 95.04 26.265 96.9 ;
     RECT  18.09 277 26.355 278.66 ;
     RECT  24.615 237.14 26.7 245.58 ;
     RECT  18.855 46.88 26.735 51.54 ;
     RECT  26.065 57.66 26.735 59.52 ;
     RECT  25.575 25.84 27.225 36.42 ;
     RECT  25.575 81.6 27.225 91.44 ;
     RECT  26.065 96.3 27.225 96.9 ;
     RECT  25.095 65.22 27.695 74.22 ;
     RECT  24.625 76.56 27.695 77.16 ;
     RECT  26.065 54.3 27.705 54.9 ;
     RECT  26.535 57.66 29.135 61.2 ;
     RECT  27.025 81.6 29.135 84.3 ;
     RECT  27.495 208.16 29.615 208.76 ;
     RECT  25.105 230.84 30.105 231.44 ;
     RECT  28.935 79.5 30.14 84.3 ;
     RECT  27.025 86.22 30.14 91.44 ;
     RECT  26.055 39.18 30.575 41.88 ;
     RECT  26.055 221.58 30.575 227.24 ;
     RECT  30.375 39.18 31.055 43.98 ;
     RECT  26.535 46.88 31.065 52.38 ;
     RECT  26.055 187.58 31.065 188.6 ;
     RECT  27.495 65.22 31.535 77.16 ;
     RECT  29.94 79.5 31.545 91.44 ;
     RECT  17.895 174.56 31.545 175.16 ;
     RECT  26.155 275.74 32.115 278.66 ;
     RECT  13.195 281.2 32.115 281.6 ;
     RECT  15.64 201.58 32.735 205.58 ;
     RECT  29.415 208.16 32.735 209.18 ;
     RECT  26.055 106.38 32.985 108.48 ;
     RECT  30.865 188 32.985 188.6 ;
     RECT  27.025 25.84 33.365 34.74 ;
     RECT  31.345 80.34 33.455 91.44 ;
     RECT  24.625 98.82 33.455 99.42 ;
     RECT  28.935 57.24 33.935 61.2 ;
     RECT  30.855 38.76 33.945 43.98 ;
     RECT  33.735 57.24 33.945 62.04 ;
     RECT  16.42 130.42 34.515 130.82 ;
     RECT  33.255 80.34 34.895 91.86 ;
     RECT  33.255 97.98 34.895 99.42 ;
     RECT  34.695 79.5 34.905 91.86 ;
     RECT  32.295 94.62 34.905 95.22 ;
     RECT  27.015 233.36 34.905 233.96 ;
     RECT  33.745 38.76 35.375 41.46 ;
     RECT  28.455 195.98 35.375 196.58 ;
     RECT  34.315 130 35.475 130.82 ;
     RECT  19.62 134.2 35.765 134.6 ;
     RECT  34.695 97.14 35.855 99.42 ;
     RECT  31.335 64.38 35.865 77.16 ;
     RECT  32.875 119.5 36 119.9 ;
     RECT  35.275 130 36 131.24 ;
     RECT  35.8 119.5 36.2 120.32 ;
     RECT  34.705 79.5 36.3 91.44 ;
     RECT  35.175 194.72 36.335 196.58 ;
     RECT  35.175 36.66 36.345 41.46 ;
     RECT  26.5 237.14 36.345 239 ;
     RECT  26.535 103.86 36.815 104.46 ;
     RECT  32.535 201.58 36.815 206.24 ;
     RECT  32.535 208.16 36.815 210.44 ;
     RECT  36.145 237.98 36.825 239 ;
     RECT  26.055 248.48 36.825 249.08 ;
     RECT  36.1 79.92 37.295 91.44 ;
     RECT  35.655 96.3 37.305 99.42 ;
     RECT  30.865 46.88 37.775 50.88 ;
     RECT  33.745 61.44 37.775 62.04 ;
     RECT  35.665 64.38 37.775 75.06 ;
     RECT  36.625 238.4 37.775 239 ;
     RECT  26.5 240.92 37.775 245.58 ;
     RECT  33.165 26.88 38.255 34.74 ;
     RECT  36.145 36.66 38.255 37.26 ;
     RECT  37.095 249.74 38.255 250.34 ;
     RECT  38.055 26.88 38.265 37.26 ;
     RECT  37.575 61.44 38.265 75.06 ;
     RECT  37.105 98.82 38.265 99.42 ;
     RECT  36.145 39.18 38.735 41.46 ;
     RECT  36.135 77.4 38.735 78 ;
     RECT  30.375 219.5 38.735 227.24 ;
     RECT  38.065 26.88 38.9 35.16 ;
     RECT  35.8 130 39.08 131.66 ;
     RECT  38.535 54.72 39.215 55.32 ;
     RECT  33.745 57.24 39.215 59.52 ;
     RECT  38.065 61.44 39.215 62.88 ;
     RECT  36.615 102.6 39.215 104.46 ;
     RECT  15.64 181.58 39.215 185.58 ;
     RECT  35.175 188.84 39.215 189.44 ;
     RECT  37.575 238.4 39.215 245.58 ;
     RECT  38.055 249.74 39.215 252.02 ;
     RECT  38.535 38.76 42.095 41.46 ;
     RECT  39.015 57.24 42.095 62.88 ;
     RECT  38.065 64.8 42.095 73.38 ;
     RECT  38.535 75.3 42.095 78 ;
     RECT  37.095 79.92 42.095 92.28 ;
     RECT  41.035 140.92 42.675 141.32 ;
     RECT  38.88 130.84 43.635 131.66 ;
     RECT  41.895 57.24 44.495 73.38 ;
     RECT  41.895 75.3 44.495 92.28 ;
     RECT  40.075 137.56 44.885 137.96 ;
     RECT  41.895 38.34 44.975 41.46 ;
     RECT  36 119.92 44.975 120.32 ;
     RECT  36.615 201.58 44.985 210.44 ;
     RECT  38.535 219.5 44.985 229.34 ;
     RECT  39.015 236.3 44.985 245.58 ;
     RECT  39.015 247.64 44.985 252.02 ;
     RECT  43.435 130 45.1 131.66 ;
     RECT  38.155 134.2 45.1 134.6 ;
     RECT  42.475 140.08 45.1 141.32 ;
     RECT  38.7 26.88 45.465 34.74 ;
     RECT  44.775 37.92 45.465 41.46 ;
     RECT  44.785 236.3 45.465 239 ;
     RECT  37.575 46.32 45.935 50.88 ;
     RECT  39.015 54.3 45.935 55.32 ;
     RECT  36.135 194.72 45.935 197 ;
     RECT  44.785 241.58 45.935 245.58 ;
     RECT  44.785 247.64 45.935 250.34 ;
     RECT  39.015 267.38 45.945 267.98 ;
     RECT  44.775 118.98 46.13 120.32 ;
     RECT  39.015 100.92 46.425 104.46 ;
     RECT  45.93 118.98 46.425 120.74 ;
     RECT  45.735 241.58 46.425 250.34 ;
     RECT  44.9 130 46.62 134.6 ;
     RECT  44.9 139.66 46.62 141.32 ;
     RECT  44.9 147.22 46.62 147.62 ;
     RECT  44.9 154.78 46.62 155.18 ;
     RECT  26.055 259.82 46.86 265.58 ;
     RECT  44.785 209.84 46.905 210.44 ;
     RECT  44.785 219.5 46.905 227.24 ;
     RECT  45.265 26.88 47.375 32.64 ;
     RECT  44.295 57.24 47.385 92.28 ;
     RECT  37.105 96.3 47.855 96.9 ;
     RECT  46.42 134.2 48.3 134.6 ;
     RECT  19.62 151.42 48.3 151.82 ;
     RECT  47.655 95.88 48.335 97.74 ;
     RECT  47.175 99.66 48.335 100.26 ;
     RECT  45.265 236.3 48.345 238.16 ;
     RECT  46.705 219.5 48.825 226.82 ;
     RECT  48.145 236.72 48.825 238.16 ;
     RECT  46.225 248.9 48.825 250.34 ;
     RECT  45.735 252.68 49.775 253.28 ;
     RECT  27.975 192.2 49.785 192.8 ;
     RECT  45.735 194.72 49.785 198.68 ;
     RECT  46.66 260.24 49.785 265.58 ;
     RECT  48.1 134.2 49.82 136.28 ;
     RECT  48.1 143.44 49.82 143.84 ;
     RECT  48.1 151 49.82 151.82 ;
     RECT  48.1 158.56 49.82 158.96 ;
     RECT  47.185 58.5 50.265 92.28 ;
     RECT  49.585 194.72 50.265 197 ;
     RECT  48.625 236.72 50.265 237.74 ;
     RECT  33.745 43.38 50.735 43.98 ;
     RECT  46.695 233.36 50.735 233.96 ;
     RECT  49.575 252.68 50.735 254.12 ;
     RECT  50.065 58.5 50.745 78.84 ;
     RECT  46.42 130 51.125 131.66 ;
     RECT  47.175 25.32 51.225 32.64 ;
     RECT  50.545 63.96 51.225 78.84 ;
     RECT  50.065 194.72 51.225 196.58 ;
     RECT  48.625 219.5 51.225 225.58 ;
     RECT  48.135 95.88 52.175 100.26 ;
     RECT  45.735 46.32 52.185 55.32 ;
     RECT  51.975 95.04 52.185 100.26 ;
     RECT  44.785 207.32 52.185 207.92 ;
     RECT  46.225 102.6 52.655 104.46 ;
     RECT  32.785 106.88 52.655 108.48 ;
     RECT  46.215 215.3 52.655 215.9 ;
     RECT  51.025 26.88 53.135 32.64 ;
     RECT  52.455 34.98 53.135 35.58 ;
     RECT  50.065 80.76 53.135 92.28 ;
     RECT  51.985 95.04 53.135 97.32 ;
     RECT  52.935 26.88 53.625 36 ;
     RECT  52.935 80.76 53.625 97.32 ;
     RECT  45.265 38.76 54.105 41.46 ;
     RECT  50.535 232.94 54.105 233.96 ;
     RECT  53.905 233.36 54.585 233.96 ;
     RECT  50.535 252.26 55.065 254.12 ;
     RECT  51.985 46.88 55.535 55.32 ;
     RECT  50.545 58.5 55.535 62.04 ;
     RECT  51.025 77.82 55.535 78.84 ;
     RECT  53.425 80.76 55.535 81.78 ;
     RECT  55.335 46.88 55.545 62.04 ;
     RECT  52.455 102.6 55.545 108.48 ;
     RECT  46.215 230 55.545 230.6 ;
     RECT  53.415 192.2 56.025 192.8 ;
     RECT  51.025 195.98 56.495 196.58 ;
     RECT  55.335 77.82 56.505 81.78 ;
     RECT  55.345 103.44 56.505 108.48 ;
     RECT  50.065 236.72 56.505 237.32 ;
     RECT  54.865 252.26 56.505 253.28 ;
     RECT  50.925 130.84 56.595 131.66 ;
     RECT  13.675 125.8 56.885 126.2 ;
     RECT  53.905 38.76 56.975 41.04 ;
     RECT  48.625 248.9 56.985 249.5 ;
     RECT  56.305 77.82 57.42 81.36 ;
     RECT  55.345 46.88 57.465 57.42 ;
     RECT  56.295 194.72 57.935 196.58 ;
     RECT  39.015 181.58 57.98 189.44 ;
     RECT  53.425 83.7 58.415 97.32 ;
     RECT  51.985 99.66 58.415 100.26 ;
     RECT  46.225 241.58 58.415 245.58 ;
     RECT  56.305 252.26 58.415 252.86 ;
     RECT  56.775 38.76 58.425 41.46 ;
     RECT  57.735 194.72 58.425 197 ;
     RECT  55.345 60.18 58.895 62.04 ;
     RECT  57.78 181.58 58.905 191.96 ;
     RECT  58.225 194.72 58.905 195.32 ;
     RECT  52.455 215.3 58.905 216.32 ;
     RECT  53.425 26.88 59.375 34.32 ;
     RECT  58.225 39.18 59.375 41.46 ;
     RECT  50.535 43.38 59.375 44.4 ;
     RECT  51.025 63.96 59.375 75.9 ;
     RECT  57.22 77.82 59.375 80.52 ;
     RECT  57.735 233.36 59.375 233.96 ;
     RECT  57.735 249.32 59.375 249.92 ;
     RECT  33.255 256.04 59.375 256.64 ;
     RECT  58.215 83.7 59.385 100.26 ;
     RECT  58.705 188 59.385 191.96 ;
     RECT  52.455 210.26 59.385 210.86 ;
     RECT  58.215 251.84 59.385 252.86 ;
     RECT  46.225 119.92 59.475 120.74 ;
     RECT  59.185 188 59.865 191.54 ;
     RECT  59.175 39.18 61.775 44.4 ;
     RECT  59.185 95.46 62.265 100.26 ;
     RECT  31.915 275.74 63.315 281.6 ;
     RECT  59.185 83.7 64.175 92.7 ;
     RECT  62.065 95.46 64.175 97.32 ;
     RECT  59.665 188 64.22 191.12 ;
     RECT  59.175 193.88 64.22 194.48 ;
     RECT  59.175 26.16 64.665 36.42 ;
     RECT  59.175 248.48 64.665 249.92 ;
     RECT  56.395 129.58 65.045 131.66 ;
     RECT  58.695 59.76 65.135 62.04 ;
     RECT  59.175 63.96 65.135 80.52 ;
     RECT  63.975 83.7 65.135 97.32 ;
     RECT  62.065 99.24 65.135 100.26 ;
     RECT  64.935 83.7 65.145 100.26 ;
     RECT  64.02 188 65.145 194.48 ;
     RECT  59.175 232.94 65.625 233.96 ;
     RECT  57.265 56.82 66.095 57.42 ;
     RECT  64.935 59.34 66.095 80.52 ;
     RECT  58.705 181.58 66.095 186.08 ;
     RECT  64.945 188 66.095 192.8 ;
     RECT  64.935 236.3 66.095 236.9 ;
     RECT  58.215 240.08 66.095 245.58 ;
     RECT  59.185 251.84 66.095 252.44 ;
     RECT  64.845 129.58 66.485 131.24 ;
     RECT  61.575 38.76 66.575 44.4 ;
     RECT  57.265 46.88 66.575 54.9 ;
     RECT  65.895 56.82 66.575 80.52 ;
     RECT  44.785 201.58 66.575 205.58 ;
     RECT  66.375 38.76 66.585 54.9 ;
     RECT  59.175 256.04 66.585 257.48 ;
     RECT  66.375 201.58 66.62 207.08 ;
     RECT  64.465 26.16 67.1 34.74 ;
     RECT  53.995 16.18 67.155 16.58 ;
     RECT  65.415 196.4 67.535 197 ;
     RECT  65.895 251.84 67.535 253.28 ;
     RECT  65.895 236.3 67.58 245.58 ;
     RECT  66.375 56.82 68.015 81.78 ;
     RECT  64.945 83.7 68.015 99.84 ;
     RECT  66.385 38.76 68.025 53.22 ;
     RECT  67.335 251.84 68.025 254.12 ;
     RECT  58.705 215.72 68.255 216.32 ;
     RECT  66.285 130 68.405 131.24 ;
     RECT  65.425 232.94 68.495 233.54 ;
     RECT  68.055 214.88 68.975 216.32 ;
     RECT  66.385 256.04 68.985 257.06 ;
     RECT  66.9 26.16 69.455 35.16 ;
     RECT  67.815 56.82 69.455 99.84 ;
     RECT  67.825 38.76 69.465 44.4 ;
     RECT  67.825 252.68 69.465 254.12 ;
     RECT  54.955 271.96 69.935 272.36 ;
     RECT  65.895 181.58 69.945 192.8 ;
     RECT  67.335 196.4 69.945 197.42 ;
     RECT  67.38 236.3 70.425 246.56 ;
     RECT  69.255 26.16 70.905 36.42 ;
     RECT  69.265 253.52 71.385 254.12 ;
     RECT  66.42 201.58 71.615 207.5 ;
     RECT  66.615 209.42 71.615 210.02 ;
     RECT  68.775 214.46 71.625 216.32 ;
     RECT  69.265 39.18 71.855 44.4 ;
     RECT  69.745 188 71.865 192.8 ;
     RECT  69.255 267.8 71.955 268.4 ;
     RECT  69.735 271.96 71.955 273.44 ;
     RECT  68.205 130 72.725 130.4 ;
     RECT  69.255 56.82 72.825 100.26 ;
     RECT  68.785 256.04 73.305 256.64 ;
     RECT  49.585 261.58 73.775 265.58 ;
     RECT  70.705 26.16 73.785 36 ;
     RECT  71.665 191.36 74.265 192.8 ;
     RECT  71.415 201.58 74.265 210.02 ;
     RECT  71.425 214.88 74.265 216.32 ;
     RECT  46.42 140.08 74.645 141.32 ;
     RECT  72.625 56.82 74.745 81.36 ;
     RECT  69.745 196.82 74.745 197.42 ;
     RECT  74.065 201.58 74.745 209.6 ;
     RECT  59.275 118.24 74.93 120.74 ;
     RECT  49.62 134.2 75.1 134.6 ;
     RECT  74.445 140.08 75.1 140.48 ;
     RECT  74.545 57.24 76.185 81.36 ;
     RECT  74.065 215.72 76.185 216.32 ;
     RECT  74.9 132.1 76.62 134.6 ;
     RECT  74.9 139.66 76.62 140.48 ;
     RECT  74.9 147.22 76.62 147.62 ;
     RECT  74.9 154.78 76.62 155.18 ;
     RECT  73.585 26.16 76.665 32.22 ;
     RECT  67.825 46.88 76.665 53.22 ;
     RECT  74.545 201.58 76.665 207.92 ;
     RECT  70.225 236.3 76.665 245.58 ;
     RECT  64.465 249.32 76.665 249.92 ;
     RECT  56.305 103.86 77.135 108.48 ;
     RECT  75.985 59.76 77.145 81.36 ;
     RECT  76.465 46.88 77.625 52.38 ;
     RECT  76.465 236.3 77.625 239.84 ;
     RECT  71.755 267.8 77.625 273.44 ;
     RECT  76.465 26.16 78.105 31.8 ;
     RECT  68.295 232.94 78.105 234.38 ;
     RECT  76.42 134.2 78.3 134.6 ;
     RECT  49.62 151.42 78.3 151.82 ;
     RECT  75.985 57.24 78.575 57.84 ;
     RECT  76.945 59.76 78.575 72.96 ;
     RECT  77.425 267.8 78.575 273.02 ;
     RECT  76.945 75.72 78.585 81.36 ;
     RECT  76.465 207.32 78.585 207.92 ;
     RECT  77.905 232.94 78.585 233.54 ;
     RECT  77.425 237.56 78.585 239.84 ;
     RECT  77.905 26.88 79.055 31.8 ;
     RECT  73.585 34.14 79.055 36 ;
     RECT  78.385 75.72 79.065 78.84 ;
     RECT  78.855 26.88 79.535 36 ;
     RECT  78.865 75.72 79.535 78.42 ;
     RECT  72.625 83.28 79.535 100.26 ;
     RECT  76.935 102.6 79.535 108.48 ;
     RECT  69.745 181.58 79.535 185.58 ;
     RECT  71.655 39.18 79.545 44.82 ;
     RECT  78.375 57.24 79.545 72.96 ;
     RECT  79.335 83.28 79.545 108.48 ;
     RECT  78.1 134.2 79.82 136.28 ;
     RECT  78.1 143.44 79.82 143.84 ;
     RECT  78.1 151 79.82 151.82 ;
     RECT  78.1 158.56 79.82 158.96 ;
     RECT  77.425 46.88 81.935 51.96 ;
     RECT  66.955 16.18 84.335 17 ;
     RECT  76.465 241.58 84.335 245.58 ;
     RECT  84.135 15.24 84.53 17 ;
     RECT  79.345 83.28 84.815 101.52 ;
     RECT  79.345 103.86 84.815 108.48 ;
     RECT  78.375 267.38 84.825 273.02 ;
     RECT  79.345 39.18 85.295 44.4 ;
     RECT  81.735 46.32 85.295 51.96 ;
     RECT  79.345 57.24 85.295 57.84 ;
     RECT  84.615 83.28 85.785 108.48 ;
     RECT  84.625 267.38 85.785 272.36 ;
     RECT  78.385 237.98 85.82 239.84 ;
     RECT  84.135 241.58 85.82 248.24 ;
     RECT  85.62 237.98 86.255 248.24 ;
     RECT  85.575 253.1 86.255 253.7 ;
     RECT  79.345 59.76 86.265 72.96 ;
     RECT  85.585 84.12 86.265 108.48 ;
     RECT  85.095 56.82 86.735 57.84 ;
     RECT  86.065 59.76 86.735 71.7 ;
     RECT  79.335 74.88 86.735 78.42 ;
     RECT  86.055 253.1 86.735 254.12 ;
     RECT  78.385 80.76 88.175 81.36 ;
     RECT  85.095 39.18 88.185 51.96 ;
     RECT  86.535 73.62 88.185 78.42 ;
     RECT  86.065 86.88 88.655 108.48 ;
     RECT  86.055 237.56 88.655 248.24 ;
     RECT  88.455 237.14 89.135 248.24 ;
     RECT  87.985 73.62 89.145 78 ;
     RECT  88.455 86.88 89.145 109.92 ;
     RECT  79.335 26.88 89.615 37.26 ;
     RECT  88.945 102.6 89.625 109.92 ;
     RECT  85.585 267.8 89.625 272.36 ;
     RECT  86.535 56.82 90.105 71.7 ;
     RECT  88.945 74.88 90.105 78 ;
     RECT  89.905 75.72 90.14 78 ;
     RECT  87.975 80.76 90.585 81.78 ;
     RECT  89.905 64.8 91.065 71.7 ;
     RECT  88.945 86.88 91.065 100.26 ;
     RECT  89.415 24.9 91.535 37.26 ;
     RECT  87.985 40.02 91.535 51.96 ;
     RECT  86.065 84.12 91.535 85.14 ;
     RECT  90.385 80.76 91.545 81.36 ;
     RECT  91.335 24.9 92.015 51.96 ;
     RECT  90.865 86.88 92.025 99.84 ;
     RECT  79.335 180.86 92.025 185.58 ;
     RECT  88.935 237.14 92.025 249.08 ;
     RECT  91.335 83.28 92.495 85.14 ;
     RECT  91.825 86.88 92.495 98.58 ;
     RECT  86.535 252.68 92.495 254.12 ;
     RECT  91.815 24.9 92.505 53.22 ;
     RECT  92.305 37.5 92.975 53.22 ;
     RECT  89.905 56.82 92.975 59.94 ;
     RECT  89.905 61.86 92.975 62.88 ;
     RECT  89.425 269.44 92.975 272.36 ;
     RECT  92.305 24.9 92.985 35.58 ;
     RECT  91.825 247.64 92.985 249.08 ;
     RECT  90.865 65.22 93.455 71.7 ;
     RECT  89.94 75.72 93.455 78.42 ;
     RECT  91.825 237.14 93.465 245.58 ;
     RECT  93.255 65.22 93.935 72.96 ;
     RECT  93.255 75.72 93.935 80.52 ;
     RECT  73.575 260.24 93.945 265.58 ;
     RECT  93.735 65.22 94.415 80.52 ;
     RECT  92.295 83.28 94.415 98.58 ;
     RECT  92.775 37.5 94.425 62.88 ;
     RECT  89.425 103.02 94.425 109.92 ;
     RECT  94.225 37.5 94.905 62.46 ;
     RECT  94.215 65.22 94.905 100.26 ;
     RECT  92.785 25.32 95.385 35.58 ;
     RECT  94.705 65.22 95.385 82.2 ;
     RECT  93.745 260.66 95.385 265.58 ;
     RECT  92.295 251.84 95.865 254.12 ;
     RECT  95.185 65.64 96.345 82.2 ;
     RECT  94.705 84.12 96.345 100.26 ;
     RECT  96.145 84.12 96.78 91.86 ;
     RECT  94.705 37.5 96.825 61.62 ;
     RECT  96.145 81.6 96.825 82.2 ;
     RECT  96.145 96.3 96.825 100.26 ;
     RECT  93.265 237.14 96.825 239.42 ;
     RECT  95.665 252.26 96.825 254.12 ;
     RECT  96.58 84.12 97.295 84.72 ;
     RECT  71.665 188 97.295 188.6 ;
     RECT  95.185 25.32 97.305 35.16 ;
     RECT  96.625 37.5 97.305 41.46 ;
     RECT  96.625 44.64 97.305 61.62 ;
     RECT  96.145 65.64 97.305 74.22 ;
     RECT  96.625 96.3 97.305 97.32 ;
     RECT  97.105 46.88 97.785 61.62 ;
     RECT  96.58 86.88 97.785 91.86 ;
     RECT  97.095 188 97.785 189.02 ;
     RECT  97.585 46.88 98.22 59.94 ;
     RECT  91.825 181.58 98.255 185.58 ;
     RECT  97.105 37.5 98.265 41.04 ;
     RECT  98.02 52.62 98.265 58.68 ;
     RECT  97.105 65.64 98.265 72.96 ;
     RECT  94.225 103.86 98.265 109.92 ;
     RECT  96.625 252.26 98.265 253.7 ;
     RECT  98.065 37.5 98.745 39.78 ;
     RECT  98.065 57.24 98.745 58.68 ;
     RECT  96.145 76.14 98.745 78.42 ;
     RECT  97.095 83.28 98.745 84.72 ;
     RECT  97.105 96.72 98.745 97.32 ;
     RECT  98.065 104.7 98.745 109.92 ;
     RECT  95.185 261.58 99.215 265.58 ;
     RECT  97.105 25.32 99.225 31.38 ;
     RECT  98.545 77.82 99.225 78.42 ;
     RECT  98.545 83.28 99.225 83.88 ;
     RECT  96.625 237.56 99.225 238.16 ;
     RECT  92.785 248.48 99.225 249.08 ;
     RECT  99.025 25.32 99.705 30.88 ;
     RECT  97.105 34.56 99.705 35.16 ;
     RECT  98.545 37.5 99.705 38.1 ;
     RECT  98.065 52.62 99.705 55.32 ;
     RECT  98.065 66.88 99.705 72.96 ;
     RECT  96.625 99.66 99.705 100.26 ;
     RECT  98.545 58.08 100.185 58.68 ;
     RECT  92.775 268.64 100.755 272.36 ;
     RECT  63.115 275.32 100.755 281.6 ;
     RECT  95.655 19.86 101.145 20.46 ;
     RECT  98.545 106.88 102.585 109.92 ;
     RECT  100.555 268.64 104.985 281.6 ;
     RECT  79.62 134.2 105.1 134.6 ;
     RECT  76.42 140.08 105.1 140.48 ;
     RECT  99.505 26.88 105.32 30.88 ;
     RECT  98.02 46.88 105.32 50.88 ;
     RECT  99.505 66.88 105.32 70.88 ;
     RECT  97.585 86.88 105.32 90.88 ;
     RECT  102.385 106.88 105.32 108.48 ;
     RECT  74.73 118.24 105.8 121.16 ;
     RECT  99.015 261.58 105.945 266.3 ;
     RECT  98.055 181.58 106.425 187.76 ;
     RECT  99.015 258.98 106.425 259.58 ;
     RECT  104.9 132.1 106.62 134.6 ;
     RECT  104.9 139.66 106.62 140.48 ;
     RECT  104.9 147.22 106.62 147.62 ;
     RECT  104.9 154.78 106.62 155.18 ;
     RECT  60.235 171.58 106.995 171.98 ;
     RECT  106.225 181.58 107.72 185.58 ;
     RECT  76.465 201.58 107.72 205.58 ;
     RECT  51.025 221.58 107.72 225.58 ;
     RECT  93.265 241.58 107.72 245.58 ;
     RECT  105.745 261.58 107.72 265.58 ;
     RECT  106.42 134.2 108.3 134.6 ;
     RECT  79.62 151.42 108.3 151.82 ;
     RECT  108.1 134.2 109.82 136.28 ;
     RECT  108.1 143.44 109.82 143.84 ;
     RECT  108.1 151 109.82 151.82 ;
     RECT  108.1 158.56 109.82 158.96 ;
     RECT  109.62 151.42 111.315 151.82 ;
     RECT  111.115 151.42 112.275 153.085 ;
     RECT  112.075 151.42 112.565 153.505 ;
     RECT  104.785 269.44 112.565 281.6 ;
     RECT  112.365 269.44 113.525 272.36 ;
     RECT  106.795 171.58 114.005 172.82 ;
     RECT  113.805 172.415 114.675 172.82 ;
     RECT  112.365 274.9 114.675 281.6 ;
     RECT  114.475 172.415 114.965 172.825 ;
     RECT  114.475 274.475 114.965 281.6 ;
     RECT  113.035 158.14 118.515 158.54 ;
     RECT  113.325 269.86 118.515 272.36 ;
     RECT  114.765 274.48 118.515 281.6 ;
     RECT  118.315 157.715 118.805 158.54 ;
     RECT  118.315 269.855 118.805 281.6 ;
     RECT  91.435 115.3 119.475 115.7 ;
     RECT  119.275 19.115 119.765 19.525 ;
     RECT  119.275 115.295 119.765 115.705 ;
     RECT  77.995 176.2 120.245 176.6 ;
     RECT  84.33 14.5 121.875 17 ;
     RECT  119.565 19.12 121.875 19.52 ;
     RECT  119.565 115.3 122.355 115.7 ;
     RECT  106.42 140.08 122.355 140.48 ;
     RECT  122.155 115.295 122.645 115.705 ;
     RECT  122.155 140.08 122.645 140.905 ;
     RECT  122.445 140.08 123.125 140.9 ;
     RECT  121.195 28.78 124.275 29.18 ;
     RECT  78.955 129.58 124.755 129.98 ;
     RECT  118.605 269.86 124.755 281.6 ;
     RECT  124.555 129.58 125.045 132.08 ;
     RECT  125.035 240.88 125.28 241.28 ;
     RECT  125.08 240.88 125.525 241.7 ;
     RECT  109.62 134.2 126.485 134.6 ;
     RECT  125.325 241.3 126.485 241.7 ;
     RECT  122.925 140.5 126.675 140.9 ;
     RECT  105.6 118.66 126.965 121.16 ;
     RECT  126.52 60.16 127.535 64.16 ;
     RECT  120.235 162.34 129.6 162.74 ;
     RECT  127.335 60.16 129.935 65.82 ;
     RECT  129.4 202.96 129.935 206.96 ;
     RECT  129.4 242.96 129.935 246.96 ;
     RECT  129.735 179.46 130.415 180.06 ;
     RECT  129.4 222.96 130.415 226.96 ;
     RECT  126.765 118.66 130.805 120.32 ;
     RECT  130.215 177.36 130.895 180.48 ;
     RECT  129.4 182.96 130.895 186.96 ;
     RECT  129.735 240.78 130.895 246.96 ;
     RECT  130.695 182.4 131.375 186.96 ;
     RECT  130.215 190.38 131.375 190.98 ;
     RECT  129.735 202.96 131.375 207.78 ;
     RECT  130.215 222.96 131.375 229.62 ;
     RECT  131.175 171.9 131.42 172.5 ;
     RECT  130.695 176.52 131.855 180.48 ;
     RECT  131.175 182.4 131.855 188.04 ;
     RECT  131.175 190.38 131.855 191.82 ;
     RECT  130.215 195.42 131.855 196.02 ;
     RECT  131.175 201.72 131.855 209.04 ;
     RECT  126.855 213.06 131.855 213.66 ;
     RECT  131.22 171.9 131.865 172.92 ;
     RECT  131.175 222.3 132.335 229.62 ;
     RECT  131.655 175.68 132.345 180.48 ;
     RECT  131.655 182.4 132.345 191.82 ;
     RECT  131.665 172.32 132.815 172.92 ;
     RECT  131.655 212.22 132.815 213.66 ;
     RECT  130.695 239.94 132.815 246.96 ;
     RECT  131.655 194.58 132.825 196.02 ;
     RECT  132.615 239.52 132.86 246.96 ;
     RECT  118.605 157.72 133.205 158.54 ;
     RECT  130.695 168.96 133.295 169.56 ;
     RECT  132.615 211.8 133.295 213.66 ;
     RECT  132.135 222.3 133.295 230.88 ;
     RECT  132.145 182.96 133.305 191.82 ;
     RECT  131.655 201.3 133.785 209.04 ;
     RECT  131.655 217.26 133.785 217.86 ;
     RECT  112.365 151.42 134.88 153.5 ;
     RECT  124.845 131.68 135.1 132.08 ;
     RECT  126.475 140.08 135.1 140.9 ;
     RECT  133.095 211.8 135.695 214.5 ;
     RECT  124.935 109.32 135.705 109.92 ;
     RECT  124.555 269.02 136.085 281.6 ;
     RECT  124.075 28.78 136.565 30.02 ;
     RECT  134.9 131.68 136.62 132.5 ;
     RECT  134.9 139.66 136.62 140.9 ;
     RECT  134.68 151.295 136.99 153.5 ;
     RECT  129.735 59.34 137.135 65.82 ;
     RECT  126.52 100.16 137.135 104.16 ;
     RECT  132.615 106.38 137.135 106.98 ;
     RECT  135.015 87.06 137.145 87.66 ;
     RECT  136.935 58.92 137.625 65.82 ;
     RECT  132.625 194.58 137.66 195.6 ;
     RECT  126.52 80.16 138.095 84.16 ;
     RECT  136.935 98.4 138.095 106.98 ;
     RECT  132.615 172.32 138.095 173.76 ;
     RECT  132.145 175.68 138.095 177.96 ;
     RECT  133.095 222.3 138.095 232.98 ;
     RECT  137.46 194.16 138.54 195.6 ;
     RECT  133.585 201.3 138.575 208.2 ;
     RECT  135.495 211.8 138.575 214.92 ;
     RECT  132.66 238.68 138.575 246.96 ;
     RECT  133.105 182.96 138.585 190.98 ;
     RECT  138.375 201.3 138.585 214.92 ;
     RECT  135.975 68.16 139.055 68.76 ;
     RECT  129.4 162.34 139.055 166.96 ;
     RECT  133.095 168.96 139.055 169.98 ;
     RECT  137.895 172.32 139.055 177.96 ;
     RECT  137.895 220.62 139.055 232.98 ;
     RECT  138.375 238.68 139.055 248.1 ;
     RECT  138.855 68.16 139.065 69.18 ;
     RECT  132.145 179.88 139.065 180.48 ;
     RECT  138.385 182.96 139.065 190.14 ;
     RECT  133.095 197.94 139.065 198.54 ;
     RECT  138.865 182.96 139.545 189.3 ;
     RECT  138.1 128.32 139.82 128.72 ;
     RECT  138.1 135.88 139.82 136.28 ;
     RECT  138.34 194.16 139.98 195.18 ;
     RECT  138.855 216.42 140.015 217.86 ;
     RECT  138.855 219.78 140.015 232.98 ;
     RECT  138.385 201.3 140.025 214.5 ;
     RECT  137.425 59.34 140.06 65.82 ;
     RECT  138.855 162.34 140.405 169.98 ;
     RECT  135.885 269.86 140.405 281.6 ;
     RECT  135.015 93.78 140.495 94.38 ;
     RECT  137.895 96.72 140.495 106.98 ;
     RECT  138.855 238.68 140.495 248.52 ;
     RECT  139.86 59.34 140.505 66.24 ;
     RECT  139.825 202.96 140.505 214.5 ;
     RECT  136.42 131.68 140.885 132.08 ;
     RECT  130.215 71.94 140.975 72.54 ;
     RECT  140.295 93.78 140.985 106.98 ;
     RECT  139.335 49.26 141.455 49.86 ;
     RECT  139.345 182.96 141.455 188.04 ;
     RECT  140.305 209.7 141.455 214.5 ;
     RECT  139.815 216.42 141.455 232.98 ;
     RECT  140.305 60.16 141.465 66.24 ;
     RECT  141.255 209.7 141.465 233.82 ;
     RECT  141.265 210.54 141.9 233.82 ;
     RECT  137.895 78.66 141.935 84.16 ;
     RECT  140.785 98.4 141.945 106.98 ;
     RECT  141.7 233.22 141.945 233.82 ;
     RECT  141.735 77.82 142.415 84.16 ;
     RECT  141.7 210.54 142.86 230.88 ;
     RECT  141.265 60.16 142.895 65.82 ;
     RECT  140.205 162.96 142.895 169.98 ;
     RECT  138.855 171.9 142.895 177.96 ;
     RECT  136.455 55.14 142.905 55.74 ;
     RECT  140.775 71.1 142.905 72.54 ;
     RECT  142.215 77.82 142.905 84.72 ;
     RECT  141.745 98.4 142.905 104.88 ;
     RECT  142.66 210.54 143.385 218.7 ;
     RECT  141.255 181.98 143.855 188.04 ;
     RECT  143.185 210.54 143.855 214.5 ;
     RECT  141.255 49.26 143.865 50.7 ;
     RECT  143.655 209.7 143.865 214.5 ;
     RECT  133.005 158.14 144.245 158.54 ;
     RECT  143.655 181.98 144.335 190.14 ;
     RECT  143.185 217.26 144.345 218.7 ;
     RECT  142.695 59.34 144.815 65.82 ;
     RECT  139.78 194.58 144.815 195.18 ;
     RECT  142.66 222.96 144.815 230.88 ;
     RECT  142.705 77.82 144.825 78.42 ;
     RECT  143.665 209.7 144.825 211.14 ;
     RECT  140.295 238.26 145.295 248.94 ;
     RECT  141.735 250.86 145.295 251.46 ;
     RECT  142.705 71.1 145.305 71.7 ;
     RECT  142.695 162.96 145.74 177.96 ;
     RECT  140.305 202.96 145.775 206.96 ;
     RECT  144.145 218.1 145.785 218.7 ;
     RECT  125.995 34.66 146.165 35.06 ;
     RECT  143.175 56.4 146.265 57.42 ;
     RECT  144.615 194.58 146.745 195.6 ;
     RECT  126.52 40.16 147.215 44.16 ;
     RECT  129.4 262.96 147.215 266.96 ;
     RECT  143.665 50.1 147.225 50.7 ;
     RECT  146.545 195 147.225 195.6 ;
     RECT  145.575 201.3 147.225 206.96 ;
     RECT  146.055 220.62 147.695 221.22 ;
     RECT  143.655 255.48 147.695 256.08 ;
     RECT  140.785 93.78 147.705 95.64 ;
     RECT  140.205 274.48 148.085 281.6 ;
     RECT  147.505 94.62 148.185 95.64 ;
     RECT  145.54 171.9 148.185 177.96 ;
     RECT  145.575 197.94 148.655 198.54 ;
     RECT  147.015 52.62 149.135 53.22 ;
     RECT  147.495 220.2 149.135 221.22 ;
     RECT  144.615 222.96 149.135 232.98 ;
     RECT  144.625 209.7 149.145 210.3 ;
     RECT  147.015 38.34 149.615 44.16 ;
     RECT  148.935 52.62 149.615 54.06 ;
     RECT  148.455 197.52 149.615 198.54 ;
     RECT  147.025 202.96 149.615 206.96 ;
     RECT  145.095 238.26 149.615 251.46 ;
     RECT  149.415 236.16 149.625 251.46 ;
     RECT  149.415 201.72 150.095 206.96 ;
     RECT  149.415 52.62 150.105 54.9 ;
     RECT  144.615 59.34 150.105 66.66 ;
     RECT  138.865 68.58 150.105 69.18 ;
     RECT  140.775 258.42 150.105 259.02 ;
     RECT  136.79 152.26 150.485 153.5 ;
     RECT  147.985 176.1 150.575 177.96 ;
     RECT  149.415 197.52 150.575 198.96 ;
     RECT  150.375 176.1 150.585 179.22 ;
     RECT  143.665 213.06 151.055 213.66 ;
     RECT  147.015 262.2 151.055 266.96 ;
     RECT  145.54 162.96 152.015 169.98 ;
     RECT  147.985 171.9 152.015 174.18 ;
     RECT  151.815 162.96 152.025 174.18 ;
     RECT  149.895 201.72 152.025 209.04 ;
     RECT  142.695 160.56 152.495 161.16 ;
     RECT  150.375 197.1 152.505 198.96 ;
     RECT  150.855 194.58 152.975 195.18 ;
     RECT  152.775 194.16 152.985 195.18 ;
     RECT  151.825 201.72 153.455 208.2 ;
     RECT  151.825 162.96 153.465 171.66 ;
     RECT  150.285 152.68 154.035 153.5 ;
     RECT  153.835 151.295 154.995 153.5 ;
     RECT  121.675 14.5 155.765 19.52 ;
     RECT  140.205 269.86 155.765 272.36 ;
     RECT  152.295 159.3 155.855 161.16 ;
     RECT  153.265 162.96 155.855 169.98 ;
     RECT  152.785 194.16 155.855 194.76 ;
     RECT  152.305 197.52 155.855 198.96 ;
     RECT  148.455 71.94 155.865 72.54 ;
     RECT  154.795 151.295 156.19 154.76 ;
     RECT  149.905 52.62 156.335 54.48 ;
     RECT  146.065 56.82 156.335 57.42 ;
     RECT  147.495 87.48 156.345 88.08 ;
     RECT  155.655 194.16 156.345 198.96 ;
     RECT  156.135 52.62 156.825 57.42 ;
     RECT  156.625 52.62 157.305 53.22 ;
     RECT  149.905 60.16 157.775 66.66 ;
     RECT  149.895 74.88 157.785 75.48 ;
     RECT  151.825 173.58 158.255 174.18 ;
     RECT  150.385 176.1 158.255 176.7 ;
     RECT  153.255 201.3 158.255 208.2 ;
     RECT  149.425 236.16 158.255 248.94 ;
     RECT  149.425 250.86 158.255 251.46 ;
     RECT  157.575 59.34 158.735 66.66 ;
     RECT  144.135 181.98 158.735 192.24 ;
     RECT  156.145 194.16 158.735 198.12 ;
     RECT  158.055 201.3 158.745 208.62 ;
     RECT  150.855 212.22 158.745 213.66 ;
     RECT  148.935 220.2 158.745 232.98 ;
     RECT  152.775 258 158.745 258.6 ;
     RECT  158.545 202.96 158.9 208.62 ;
     RECT  136.365 29.62 159.215 30.02 ;
     RECT  150.385 178.62 159.215 179.22 ;
     RECT  158.535 181.98 159.215 198.96 ;
     RECT  155.99 152.68 159.605 154.76 ;
     RECT  158.545 213.06 159.695 213.66 ;
     RECT  158.545 220.62 159.695 232.98 ;
     RECT  156.615 68.58 159.705 69.18 ;
     RECT  158.055 173.58 159.705 176.7 ;
     RECT  159.015 88.32 160.175 88.92 ;
     RECT  156.625 55.98 160.185 56.58 ;
     RECT  158.7 202.96 160.185 208.2 ;
     RECT  159.495 220.62 160.185 233.82 ;
     RECT  158.055 236.16 160.185 251.46 ;
     RECT  148.935 34.56 160.655 35.16 ;
     RECT  158.535 58.92 160.655 66.66 ;
     RECT  160.455 57.24 160.665 66.66 ;
     RECT  159.985 241.62 160.665 251.46 ;
     RECT  159.975 71.94 161.135 72.54 ;
     RECT  159.015 178.62 161.145 198.96 ;
     RECT  142.705 98.4 161.615 104.16 ;
     RECT  159.495 213.06 162.095 214.5 ;
     RECT  159.985 236.16 162.095 239.7 ;
     RECT  159.505 173.58 162.585 175.86 ;
     RECT  160.945 196.26 162.585 198.96 ;
     RECT  159.985 230.28 162.585 233.82 ;
     RECT  161.895 213.06 163.055 214.92 ;
     RECT  159.985 220.62 163.055 226.96 ;
     RECT  162.385 175.26 163.065 175.86 ;
     RECT  162.385 196.26 163.065 198.54 ;
     RECT  160.465 57.24 163.1 65.82 ;
     RECT  150.855 261.78 163.535 266.96 ;
     RECT  162.9 57.24 163.545 66.24 ;
     RECT  160.935 69.42 163.545 70.02 ;
     RECT  160.945 178.62 163.545 193.92 ;
     RECT  159.405 154.36 163.635 154.76 ;
     RECT  160.935 71.94 164.015 72.96 ;
     RECT  155.655 159.3 164.015 169.98 ;
     RECT  163.345 189.96 164.015 193.92 ;
     RECT  162.865 196.26 164.015 196.86 ;
     RECT  162.855 219.78 164.015 226.96 ;
     RECT  162.385 230.28 164.015 232.98 ;
     RECT  142.705 80.16 164.495 84.72 ;
     RECT  163.345 178.62 164.495 188.04 ;
     RECT  163.815 189.96 164.505 196.86 ;
     RECT  163.815 219.78 164.975 232.98 ;
     RECT  160.465 242.96 164.975 251.46 ;
     RECT  164.775 218.1 165.02 232.98 ;
     RECT  136.42 140.08 165.1 140.9 ;
     RECT  159.015 29.62 165.455 31.38 ;
     RECT  160.455 34.56 165.455 35.58 ;
     RECT  164.295 79.5 165.455 84.72 ;
     RECT  165.255 29.62 165.945 35.58 ;
     RECT  164.295 177.78 165.945 188.04 ;
     RECT  162.855 210.96 165.945 214.92 ;
     RECT  165.255 79.5 166.415 85.56 ;
     RECT  159.975 87.48 166.415 88.92 ;
     RECT  164.9 132.1 166.62 132.5 ;
     RECT  147.885 274.9 166.805 281.6 ;
     RECT  163.815 159.3 166.895 171.24 ;
     RECT  164.82 217.68 166.905 232.98 ;
     RECT  164.9 139.66 166.995 140.9 ;
     RECT  130.605 118.66 167.285 119.48 ;
     RECT  163.815 71.52 167.375 72.96 ;
     RECT  163.335 105.96 167.375 106.56 ;
     RECT  164.305 194.58 167.375 196.86 ;
     RECT  164.295 258.42 167.375 259.02 ;
     RECT  166.215 79.5 167.385 88.92 ;
     RECT  167.175 258 167.385 259.02 ;
     RECT  163.345 57.24 167.855 57.84 ;
     RECT  159.985 202.96 167.855 207.78 ;
     RECT  166.705 219.78 167.865 229.2 ;
     RECT  166.795 137.98 167.955 140.9 ;
     RECT  167.755 137.98 168.245 141.32 ;
     RECT  168.045 137.98 168.3 138.38 ;
     RECT  161.415 97.56 168.335 104.16 ;
     RECT  165.745 177.78 168.335 179.22 ;
     RECT  165.745 181.98 168.335 188.04 ;
     RECT  167.655 202.96 168.335 208.62 ;
     RECT  167.175 71.52 168.345 73.38 ;
     RECT  168.135 177.78 168.345 188.04 ;
     RECT  165.745 29.62 168.725 31.38 ;
     RECT  168.145 177.78 168.815 178.38 ;
     RECT  168.145 180.3 168.815 188.04 ;
     RECT  164.305 189.96 168.815 192.24 ;
     RECT  168.135 201.72 168.815 208.62 ;
     RECT  165.745 210.96 168.815 214.5 ;
     RECT  164.775 242.96 168.815 251.88 ;
     RECT  163.335 261.78 168.815 268.26 ;
     RECT  149.415 37.92 168.825 44.16 ;
     RECT  168.145 72.36 168.825 73.38 ;
     RECT  167.185 80.16 168.825 88.92 ;
     RECT  167.175 194.58 168.825 198.96 ;
     RECT  168.615 201.72 168.825 214.5 ;
     RECT  147.985 94.62 169.295 95.22 ;
     RECT  161.895 235.74 169.295 239.7 ;
     RECT  168.525 30.36 169.305 31.38 ;
     RECT  168.625 80.16 169.305 88.08 ;
     RECT  169.095 94.2 169.305 95.22 ;
     RECT  147.495 254.64 169.305 256.08 ;
     RECT  163.345 60.16 169.74 66.24 ;
     RECT  167.655 56.82 169.775 57.84 ;
     RECT  169.54 60.16 169.775 65.82 ;
     RECT  167.665 222.96 169.785 229.2 ;
     RECT  168.1 128.32 169.82 128.72 ;
     RECT  168.1 135.88 169.82 138.38 ;
     RECT  169.095 235.74 170.735 240.12 ;
     RECT  167.185 258 170.735 258.6 ;
     RECT  166.695 159.3 170.745 172.5 ;
     RECT  167.665 220.62 170.745 221.22 ;
     RECT  169.585 222.96 170.745 228.78 ;
     RECT  168.615 176.52 171.215 178.38 ;
     RECT  168.615 180.3 171.705 192.24 ;
     RECT  168.625 201.72 171.705 213.66 ;
     RECT  171.505 202.14 172.175 213.66 ;
     RECT  170.535 235.74 172.175 240.54 ;
     RECT  168.615 242.46 172.175 251.88 ;
     RECT  171.505 180.3 172.185 180.9 ;
     RECT  171.975 235.74 172.185 251.88 ;
     RECT  171.015 174.42 172.655 178.38 ;
     RECT  171.505 182.96 172.665 192.24 ;
     RECT  168.625 195 172.665 198.96 ;
     RECT  171.985 249.18 173.135 251.88 ;
     RECT  169.105 255.06 173.135 256.08 ;
     RECT  166.605 275.74 173.525 281.6 ;
     RECT  172.465 182.96 173.625 187.62 ;
     RECT  172.465 196.26 173.625 198.96 ;
     RECT  168.625 40.16 175.055 44.16 ;
     RECT  169.575 56.82 175.055 65.82 ;
     RECT  169.62 137.98 175.155 138.38 ;
     RECT  168.045 140.5 175.445 141.32 ;
     RECT  169.105 80.16 175.535 85.56 ;
     RECT  168.135 97.14 175.535 104.16 ;
     RECT  167.175 105.96 175.535 107.82 ;
     RECT  169.105 87.48 175.545 88.08 ;
     RECT  175.335 97.14 175.545 107.82 ;
     RECT  172.455 76.56 176.015 77.16 ;
     RECT  171.975 202.14 176.025 214.5 ;
     RECT  175.345 97.14 176.505 106.56 ;
     RECT  168.625 72.78 176.975 73.38 ;
     RECT  165.745 33.3 176.985 35.58 ;
     RECT  176.775 71.94 177.02 73.38 ;
     RECT  175.335 79.08 177.455 85.56 ;
     RECT  170.055 45.9 177.465 46.5 ;
     RECT  176.82 71.94 177.465 74.22 ;
     RECT  170.545 222.96 177.935 228.36 ;
     RECT  174.855 38.34 177.945 44.16 ;
     RECT  177.265 73.62 177.945 74.22 ;
     RECT  175.825 202.14 178.38 208.62 ;
     RECT  178.18 202.14 178.415 208.2 ;
     RECT  178.215 201.72 178.425 208.2 ;
     RECT  176.785 33.3 178.46 34.74 ;
     RECT  175.335 52.62 178.46 53.22 ;
     RECT  172.455 174.42 178.895 178.8 ;
     RECT  172.935 218.1 178.895 218.7 ;
     RECT  166.705 232.38 178.895 232.98 ;
     RECT  178.695 231.96 179.375 232.98 ;
     RECT  174.855 56.4 179.385 65.82 ;
     RECT  175.825 210.96 179.385 214.5 ;
     RECT  172.465 189.54 179.42 192.24 ;
     RECT  176.305 97.14 179.865 105.72 ;
     RECT  178.695 174.42 179.865 179.64 ;
     RECT  175.245 140.92 179.955 141.32 ;
     RECT  167.085 118.66 180.245 119.06 ;
     RECT  172.935 249.18 180.335 256.08 ;
     RECT  170.535 258 180.335 259.44 ;
     RECT  178.26 32.88 180.345 34.74 ;
     RECT  169.105 30.36 180.815 30.96 ;
     RECT  179.665 179.04 180.815 179.64 ;
     RECT  173.425 182.96 180.815 186.96 ;
     RECT  179.22 188.7 180.815 192.24 ;
     RECT  180.145 33.72 180.825 34.74 ;
     RECT  171.985 235.74 180.825 246.96 ;
     RECT  169.105 94.2 181.295 94.8 ;
     RECT  178.695 216.42 181.295 218.7 ;
     RECT  179.185 59.34 181.305 65.82 ;
     RECT  178.26 52.62 181.775 53.64 ;
     RECT  179.185 56.4 181.775 57.42 ;
     RECT  168.615 261.78 181.775 268.68 ;
     RECT  175.815 76.14 181.785 77.16 ;
     RECT  180.135 249.18 181.785 259.44 ;
     RECT  181.575 56.4 182.265 58.26 ;
     RECT  177.735 222.96 182.265 230.04 ;
     RECT  177.255 79.08 182.735 87.66 ;
     RECT  182.065 56.82 183.225 58.26 ;
     RECT  170.545 159.3 183.225 171.24 ;
     RECT  183.025 57.66 183.695 58.26 ;
     RECT  181.105 60.16 183.695 65.82 ;
     RECT  178.225 201.72 184.175 206.96 ;
     RECT  181.095 216.42 184.185 220.38 ;
     RECT  179.175 231.96 184.185 233.4 ;
     RECT  183.985 232.8 184.655 233.4 ;
     RECT  180.625 236.16 184.655 246.96 ;
     RECT  181.585 249.18 184.655 252.72 ;
     RECT  180.615 182.96 185.135 192.24 ;
     RECT  183.975 201.3 185.135 206.96 ;
     RECT  173.425 196.26 185.615 198.12 ;
     RECT  184.455 232.8 185.615 252.72 ;
     RECT  181.585 254.64 185.615 259.44 ;
     RECT  184.935 200.88 186.095 206.96 ;
     RECT  185.415 232.8 186.14 259.44 ;
     RECT  174.955 136.72 186.195 138.38 ;
     RECT  179.755 140.5 186.195 141.32 ;
     RECT  179.185 210.96 186.575 213.66 ;
     RECT  182.535 77.82 186.585 87.66 ;
     RECT  179.665 174.84 186.585 176.7 ;
     RECT  184.935 182.4 186.585 192.24 ;
     RECT  186.375 210.96 186.585 214.5 ;
     RECT  163.435 152.26 186.675 154.76 ;
     RECT  180.615 179.04 187.055 180.06 ;
     RECT  186.385 182.4 187.055 186.96 ;
     RECT  183.025 160.14 187.065 171.24 ;
     RECT  181.095 94.2 187.545 95.22 ;
     RECT  182.535 106.38 187.545 106.98 ;
     RECT  155.565 14.5 187.635 17.42 ;
     RECT  186.855 179.04 188.015 186.96 ;
     RECT  185.415 194.58 188.025 198.12 ;
     RECT  183.985 216.84 188.025 220.38 ;
     RECT  185.94 231.96 188.025 259.44 ;
     RECT  180.625 33.72 188.505 34.32 ;
     RECT  186.385 189.96 188.505 192.24 ;
     RECT  186.385 213.06 188.505 214.5 ;
     RECT  187.345 94.62 188.975 95.22 ;
     RECT  179.665 97.14 188.975 104.16 ;
     RECT  186.865 170.64 188.975 171.24 ;
     RECT  182.065 222.96 188.975 228.78 ;
     RECT  181.575 52.62 188.985 54.06 ;
     RECT  187.825 195 188.985 198.12 ;
     RECT  187.825 231.96 188.985 233.4 ;
     RECT  186.865 160.14 189.465 168.72 ;
     RECT  183.495 57.66 189.935 65.82 ;
     RECT  186.385 77.82 189.935 85.56 ;
     RECT  183.975 68.58 189.945 69.18 ;
     RECT  188.775 94.62 189.945 104.16 ;
     RECT  188.305 189.96 190.38 191.4 ;
     RECT  189.735 56.4 190.415 65.82 ;
     RECT  185.895 200.46 190.415 206.96 ;
     RECT  186.855 209.7 190.415 210.3 ;
     RECT  190.215 56.4 190.425 66.24 ;
     RECT  190.215 200.46 190.425 210.3 ;
     RECT  188.775 222.3 191.375 228.78 ;
     RECT  188.785 232.8 191.375 233.4 ;
     RECT  187.825 239.94 191.375 259.44 ;
     RECT  181.575 261.78 191.375 269.1 ;
     RECT  188.305 213.9 191.385 214.5 ;
     RECT  187.825 216.84 191.385 218.7 ;
     RECT  189.265 160.56 191.855 168.72 ;
     RECT  188.775 170.64 191.855 172.5 ;
     RECT  188.785 195 191.855 197.7 ;
     RECT  191.655 193.32 192.335 197.7 ;
     RECT  191.175 221.88 192.335 228.78 ;
     RECT  186.385 174.84 192.345 175.44 ;
     RECT  191.185 217.26 192.345 218.7 ;
     RECT  189.745 95.46 192.815 104.16 ;
     RECT  190.18 189.96 192.815 190.98 ;
     RECT  191.655 160.56 192.825 172.5 ;
     RECT  192.145 218.1 192.825 218.7 ;
     RECT  191.175 239.94 192.825 269.1 ;
     RECT  190.225 200.46 193.26 209.04 ;
     RECT  192.615 189.12 193.295 190.98 ;
     RECT  193.06 201.3 193.295 209.04 ;
     RECT  192.135 221.04 193.295 228.78 ;
     RECT  187.825 236.16 193.295 236.76 ;
     RECT  192.625 161.4 193.305 172.5 ;
     RECT  193.095 201.3 193.305 210.3 ;
     RECT  192.135 193.32 193.785 198.54 ;
     RECT  192.625 250.86 193.785 269.1 ;
     RECT  186.475 151.42 194.45 154.76 ;
     RECT  173.325 275.74 194.645 281.18 ;
     RECT  183.975 72.36 195.215 72.96 ;
     RECT  192.615 95.46 195.215 105.72 ;
     RECT  187.435 14.5 195.605 19.52 ;
     RECT  189.735 77.4 195.695 85.56 ;
     RECT  190.225 56.4 195.705 57 ;
     RECT  195.015 93.78 195.705 105.72 ;
     RECT  193.105 201.3 196.185 207.78 ;
     RECT  194.9 132.1 196.62 132.5 ;
     RECT  190.225 59.34 196.665 66.24 ;
     RECT  196.465 59.34 197.625 64.98 ;
     RECT  195.495 75.3 197.625 85.56 ;
     RECT  192.615 214.74 198.095 215.34 ;
     RECT  192.625 239.94 198.095 248.52 ;
     RECT  180.615 30.36 198.105 31.8 ;
     RECT  195.015 71.94 198.105 72.96 ;
     RECT  185.995 136.72 198.3 141.32 ;
     RECT  187.815 178.62 198.575 186.96 ;
     RECT  193.095 188.7 198.575 190.98 ;
     RECT  195.015 68.58 198.585 69.18 ;
     RECT  193.585 194.58 198.585 198.54 ;
     RECT  195.985 201.72 198.585 207.78 ;
     RECT  193.095 220.62 198.585 229.62 ;
     RECT  191.175 231.96 198.585 233.4 ;
     RECT  195.405 14.92 198.675 19.52 ;
     RECT  198.375 178.62 199.065 190.98 ;
     RECT  198.385 221.88 199.065 229.62 ;
     RECT  198.385 231.96 199.065 232.98 ;
     RECT  193.585 261.78 199.5 269.1 ;
     RECT  197.895 239.94 199.535 248.94 ;
     RECT  198.385 195.42 199.545 197.28 ;
     RECT  193.105 161.82 199.58 172.5 ;
     RECT  198.1 128.32 199.82 128.72 ;
     RECT  198.1 135.88 199.82 141.32 ;
     RECT  193.585 250.86 200.015 259.44 ;
     RECT  198.865 178.62 200.025 186.96 ;
     RECT  198.865 190.38 200.025 190.98 ;
     RECT  193.105 209.7 200.025 210.3 ;
     RECT  199.815 175.68 200.495 176.28 ;
     RECT  197.425 76.14 200.505 85.56 ;
     RECT  199.345 196.26 200.505 197.28 ;
     RECT  198.385 201.72 200.505 206.96 ;
     RECT  199.3 261.78 200.505 268.26 ;
     RECT  200.305 77.82 200.985 85.56 ;
     RECT  195.505 93.78 200.985 104.16 ;
     RECT  200.305 196.68 200.985 197.28 ;
     RECT  197.895 212.64 201.455 215.34 ;
     RECT  199.815 217.26 201.455 217.86 ;
     RECT  198.865 231.96 201.455 232.56 ;
     RECT  198.865 222.96 201.465 229.62 ;
     RECT  201.255 231.96 201.465 233.4 ;
     RECT  200.785 77.82 201.945 84.16 ;
     RECT  199.38 159.72 202.425 172.5 ;
     RECT  199.815 250.86 202.425 259.86 ;
     RECT  148.075 125.8 202.805 126.2 ;
     RECT  200.305 262.96 202.895 268.26 ;
     RECT  201.745 79.5 202.905 84.16 ;
     RECT  200.785 95.46 202.905 104.16 ;
     RECT  201.255 212.64 202.905 217.86 ;
     RECT  199.335 238.68 202.94 248.94 ;
     RECT  202.225 250.86 202.94 256.08 ;
     RECT  194.445 277.42 203.24 281.18 ;
     RECT  198.475 14.92 203.765 21.2 ;
     RECT  201.265 222.96 204.335 229.2 ;
     RECT  199.825 179.46 204.815 186.96 ;
     RECT  202.74 238.68 204.815 256.08 ;
     RECT  202.225 258 204.815 259.86 ;
     RECT  202.225 159.72 205.295 170.82 ;
     RECT  202.705 212.64 205.305 217.44 ;
     RECT  204.615 238.68 205.305 259.86 ;
     RECT  205.105 212.64 205.775 217.02 ;
     RECT  202.705 98.82 205.785 104.16 ;
     RECT  204.615 179.04 206.255 186.96 ;
     RECT  202.695 188.7 206.255 189.3 ;
     RECT  200.305 202.96 206.255 206.96 ;
     RECT  201.265 232.38 206.255 233.4 ;
     RECT  193.095 235.74 206.255 236.76 ;
     RECT  206.055 179.04 206.735 189.3 ;
     RECT  206.535 179.04 206.745 190.56 ;
     RECT  205.105 257.58 206.745 259.86 ;
     RECT  197.425 59.34 207.215 64.16 ;
     RECT  203.565 17.02 207.315 21.2 ;
     RECT  197.905 31.2 207.705 31.8 ;
     RECT  188.785 52.62 207.705 53.22 ;
     RECT  207.015 58.92 207.705 64.16 ;
     RECT  197.905 72.36 207.705 72.96 ;
     RECT  202.705 95.46 207.705 96.06 ;
     RECT  205.105 238.68 207.705 255.66 ;
     RECT  206.545 179.04 208.175 180.48 ;
     RECT  206.055 202.96 208.175 208.2 ;
     RECT  205.575 210.54 208.175 217.02 ;
     RECT  207.505 238.68 208.185 239.28 ;
     RECT  207.505 242.04 208.185 255.66 ;
     RECT  177.745 40.16 208.52 44.16 ;
     RECT  207.505 60.16 208.52 64.16 ;
     RECT  202.705 80.16 208.52 84.16 ;
     RECT  205.585 100.16 208.52 104.16 ;
     RECT  200.295 175.26 208.655 176.28 ;
     RECT  207.975 178.62 208.665 180.48 ;
     RECT  189.355 118.66 208.755 119.06 ;
     RECT  207.115 17.02 209.045 21.62 ;
     RECT  208.555 118.655 209.045 119.065 ;
     RECT  208.455 175.26 209.135 176.7 ;
     RECT  207.985 242.04 209.145 251.46 ;
     RECT  206.055 232.38 209.625 236.76 ;
     RECT  194.25 149.74 210.005 154.76 ;
     RECT  204.135 221.04 210.105 229.2 ;
     RECT  177.835 25 210.965 25.4 ;
     RECT  208.465 178.62 211.055 179.64 ;
     RECT  206.545 182.4 211.055 190.56 ;
     RECT  210.375 240.36 211.535 240.96 ;
     RECT  208.945 242.96 211.535 251.46 ;
     RECT  206.545 257.58 211.535 259.02 ;
     RECT  210.855 178.62 212.025 180.06 ;
     RECT  207.975 202.96 212.025 217.02 ;
     RECT  209.905 221.88 212.025 229.2 ;
     RECT  208.845 20.8 212.405 21.62 ;
     RECT  199.915 107.74 212.405 108.14 ;
     RECT  208.935 174.84 212.975 176.7 ;
     RECT  211.825 179.04 212.975 180.06 ;
     RECT  210.855 182.4 212.975 190.98 ;
     RECT  211.335 240.36 212.975 251.46 ;
     RECT  207.985 253.38 212.975 255.66 ;
     RECT  212.775 179.04 213.455 190.98 ;
     RECT  209.425 236.16 213.945 236.76 ;
     RECT  212.775 219.78 215.855 220.38 ;
     RECT  211.825 222.3 215.855 229.2 ;
     RECT  213.255 155.1 218.255 155.7 ;
     RECT  205.095 158.88 218.255 172.5 ;
     RECT  202.695 199.2 218.255 199.8 ;
     RECT  172.555 115.72 218.645 116.12 ;
     RECT  213.255 179.04 218.745 191.4 ;
     RECT  211.825 202.96 218.745 209.04 ;
     RECT  212.775 239.94 218.745 255.66 ;
     RECT  211.335 257.58 218.745 259.86 ;
     RECT  218.545 202.96 219.215 207.78 ;
     RECT  218.545 182.4 219.225 191.4 ;
     RECT  203.04 277.84 219.51 281.18 ;
     RECT  212.205 20.8 219.605 21.2 ;
     RECT  209.805 149.74 219.605 153.08 ;
     RECT  209.425 232.38 219.695 234.24 ;
     RECT  215.655 219.78 219.705 229.2 ;
     RECT  219.025 182.96 220.175 191.4 ;
     RECT  219.495 193.32 220.175 193.92 ;
     RECT  202.695 262.2 220.185 268.26 ;
     RECT  211.825 212.64 220.655 217.02 ;
     RECT  219.975 182.96 221.135 193.92 ;
     RECT  218.055 196.68 221.135 199.8 ;
     RECT  219.015 202.14 221.135 207.78 ;
     RECT  219.015 209.7 221.135 210.3 ;
     RECT  220.455 212.64 221.135 217.86 ;
     RECT  218.055 155.1 221.145 172.5 ;
     RECT  218.545 239.94 221.615 247.68 ;
     RECT  218.545 250.02 221.615 254.4 ;
     RECT  221.415 239.94 222.105 254.4 ;
     RECT  219.495 232.38 222.585 236.34 ;
     RECT  219.405 151 223.055 153.08 ;
     RECT  220.945 155.1 223.055 171.24 ;
     RECT  219.505 220.62 223.065 229.2 ;
     RECT  222.385 235.74 223.065 236.34 ;
     RECT  220.935 182.96 223.545 210.3 ;
     RECT  221.905 249.18 223.545 254.4 ;
     RECT  219.985 262.2 223.545 267.42 ;
     RECT  220.935 212.22 223.98 217.86 ;
     RECT  222.855 151 224.015 171.24 ;
     RECT  223.78 216.42 224.025 217.86 ;
     RECT  221.905 239.94 224.025 246.96 ;
     RECT  223.345 253.38 224.025 254.4 ;
     RECT  223.815 151 224.405 172.5 ;
     RECT  223.345 200.88 224.46 210.3 ;
     RECT  224.205 154.68 224.495 172.5 ;
     RECT  212.775 174.42 224.495 176.7 ;
     RECT  222.385 232.38 224.54 232.98 ;
     RECT  224.34 232.38 224.94 233.4 ;
     RECT  223.825 216.42 224.985 217.02 ;
     RECT  208.845 17.02 225.1 17.42 ;
     RECT  211.915 50.62 225.1 51.02 ;
     RECT  208.845 118.66 225.1 119.06 ;
     RECT  209.515 132.94 225.1 133.34 ;
     RECT  224.205 151 225.845 151.82 ;
     RECT  223.825 242.46 225.935 246.96 ;
     RECT  223.345 249.18 225.935 251.46 ;
     RECT  223.825 239.94 226.415 240.54 ;
     RECT  225.735 242.46 226.415 251.46 ;
     RECT  223.825 253.38 226.415 253.98 ;
     RECT  224.9 17.02 226.62 19.1 ;
     RECT  224.9 26.26 226.62 26.66 ;
     RECT  224.9 33.82 226.62 34.22 ;
     RECT  224.9 41.38 226.62 41.78 ;
     RECT  224.9 48.94 226.62 51.02 ;
     RECT  224.9 56.5 226.62 56.9 ;
     RECT  224.9 64.06 226.62 64.46 ;
     RECT  224.9 71.62 226.62 72.02 ;
     RECT  224.9 79.18 226.62 79.58 ;
     RECT  224.9 86.74 226.62 87.14 ;
     RECT  224.9 94.3 226.62 94.7 ;
     RECT  224.9 101.86 226.62 102.26 ;
     RECT  224.9 109.42 226.62 109.82 ;
     RECT  224.9 116.98 226.62 119.06 ;
     RECT  224.9 124.54 226.62 124.94 ;
     RECT  224.9 132.1 226.62 133.34 ;
     RECT  218.545 258 226.905 259.86 ;
     RECT  219.31 278.68 227.19 281.18 ;
     RECT  224.26 202.14 227.375 210.3 ;
     RECT  224.295 154.68 227.385 176.7 ;
     RECT  223.345 182.96 227.865 197.7 ;
     RECT  226.215 239.94 227.865 253.98 ;
     RECT  226.705 258 227.865 259.44 ;
     RECT  223.345 262.96 227.865 267.42 ;
     RECT  226.42 17.02 228.3 17.42 ;
     RECT  226.42 50.62 228.3 51.02 ;
     RECT  219.115 83.8 228.3 84.2 ;
     RECT  226.42 118.66 228.3 119.06 ;
     RECT  199.62 136.72 228.3 141.32 ;
     RECT  227.185 174 228.335 176.7 ;
     RECT  227.175 201.72 228.335 210.3 ;
     RECT  223.78 212.22 228.345 214.5 ;
     RECT  227.665 239.94 228.345 247.68 ;
     RECT  228.145 213.48 228.815 214.5 ;
     RECT  218.545 179.04 228.825 180.06 ;
     RECT  227.665 190.38 228.825 197.7 ;
     RECT  228.145 242.46 229.785 247.68 ;
     RECT  228.1 14.92 229.82 17.42 ;
     RECT  228.1 22.48 229.82 22.88 ;
     RECT  228.1 30.04 229.82 30.44 ;
     RECT  228.1 37.6 229.82 38 ;
     RECT  228.1 45.16 229.82 45.56 ;
     RECT  228.1 50.62 229.82 53.12 ;
     RECT  228.1 60.28 229.82 60.68 ;
     RECT  228.1 67.84 229.82 68.24 ;
     RECT  228.1 75.4 229.82 75.8 ;
     RECT  228.1 82.96 229.82 84.2 ;
     RECT  228.1 90.52 229.82 90.92 ;
     RECT  228.1 98.08 229.82 98.48 ;
     RECT  228.1 105.64 229.82 106.04 ;
     RECT  228.1 113.2 229.82 113.6 ;
     RECT  228.1 118.66 229.82 121.16 ;
     RECT  228.1 128.32 229.82 128.72 ;
     RECT  228.1 135.88 229.82 141.32 ;
     RECT  228.625 179.46 230.265 180.06 ;
     RECT  227.665 250.86 230.265 253.98 ;
     RECT  225.645 151 230.645 151.4 ;
     RECT  228.625 193.32 230.735 197.7 ;
     RECT  227.665 258.84 230.735 259.44 ;
     RECT  227.185 154.68 230.745 171.24 ;
     RECT  228.615 213.48 230.745 214.92 ;
     RECT  222.865 220.62 230.745 226.96 ;
     RECT  228.145 239.94 230.745 240.54 ;
     RECT  230.535 258.42 230.745 259.44 ;
     RECT  230.065 250.86 231.225 251.46 ;
     RECT  228.135 174 231.705 177.12 ;
     RECT  228.625 190.38 232.185 190.98 ;
     RECT  155.565 271.96 232.565 272.36 ;
     RECT  231.505 174 232.665 176.7 ;
     RECT  230.065 253.38 232.665 253.98 ;
     RECT  232.465 174.42 233.145 176.7 ;
     RECT  228.135 201.3 233.145 210.3 ;
     RECT  229.585 242.46 233.145 246.96 ;
     RECT  230.545 213.9 233.58 214.92 ;
     RECT  230.545 162.24 233.625 171.24 ;
     RECT  232.945 175.26 233.625 176.7 ;
     RECT  230.535 193.32 233.625 198.54 ;
     RECT  233.38 213.9 233.625 214.5 ;
     RECT  230.545 220.62 233.625 221.22 ;
     RECT  230.545 258.42 233.625 259.02 ;
     RECT  204.235 143.86 238.325 144.26 ;
     RECT  230.545 154.68 238.905 159.9 ;
     RECT  233.425 193.32 238.905 195.6 ;
     RECT  233.425 197.94 238.905 198.54 ;
     RECT  238.705 156.78 239.385 159.9 ;
     RECT  238.705 195 239.385 195.6 ;
     RECT  232.945 201.3 239.865 206.96 ;
     RECT  226.99 280.78 240.245 281.18 ;
     RECT  239.185 156.78 240.345 159.48 ;
     RECT  233.425 162.96 240.345 171.24 ;
     RECT  232.945 209.7 240.345 210.3 ;
     RECT  224.74 232.8 240.345 233.4 ;
     RECT  240.145 156.78 240.825 157.38 ;
     RECT  240.145 168.96 240.825 171.24 ;
     RECT  240.625 168.96 241.305 169.56 ;
     RECT  240.145 162.96 241.64 166.96 ;
     RECT  227.665 182.96 241.64 186.96 ;
     RECT  239.665 202.96 241.64 206.96 ;
     RECT  230.545 222.96 241.64 226.96 ;
     RECT  232.945 242.96 241.64 246.96 ;
     RECT  227.665 262.96 241.64 266.96 ;
     RECT  226.42 132.94 242.165 133.34 ;
     RECT  229.62 136.72 246.965 141.32 ;
     RECT  246.765 136.72 248.885 140.9 ;
     RECT  229.62 17.02 250.805 17.42 ;
     RECT  229.62 50.62 250.805 51.02 ;
     RECT  229.62 83.8 250.805 84.2 ;
     RECT  229.62 118.66 250.805 119.06 ;
     RECT  248.685 136.72 250.805 137.12 ;
     RECT  248.685 140.08 250.805 140.48 ;
     RECT  251.275 114.04 251.52 114.44 ;
     RECT  251.275 15.76 251.765 16.58 ;
     RECT  251.32 114.04 251.765 114.86 ;
     RECT  251.565 16.18 257.66 16.58 ;
     RECT  251.275 48.94 257.66 49.34 ;
     RECT  251.275 81.7 257.66 82.1 ;
     RECT  251.565 114.46 257.66 114.86 ;
     RECT  251.275 147.22 257.66 147.62 ;
     RECT  249.355 179.98 257.66 180.38 ;
     RECT  250.795 212.74 257.66 213.14 ;
     RECT  247.435 245.5 257.66 245.9 ;
     RECT  248.875 278.26 257.66 278.66 ;
    LAYER Metal4 ;
     RECT  119.32 19.075 119.72 115.745 ;
     RECT  208.6 19.075 209 119.105 ;
     RECT  122.2 115.255 122.6 140.945 ;
     RECT  104.86 14.8 109.86 152.835 ;
     RECT  104.86 152.635 111.56 153.255 ;
     RECT  5.82 154.66 7.62 170.42 ;
     RECT  118.36 157.675 118.76 270.305 ;
     RECT  104.86 153.055 112.52 274.085 ;
     RECT  112.12 273.885 112.52 274.505 ;
     RECT  114.52 172.375 114.92 274.925 ;
     RECT  14.86 14.8 19.86 280.04 ;
     RECT  44.86 14.8 49.86 280.04 ;
     RECT  74.86 14.8 79.86 280.04 ;
     RECT  104.86 273.885 109.86 280.04 ;
     RECT  134.86 14.8 139.86 280.04 ;
     RECT  164.86 14.8 169.86 280.04 ;
     RECT  194.86 14.8 199.86 280.04 ;
     RECT  224.86 14.8 229.86 280.04 ;
  END
END mdll
END LIBRARY
